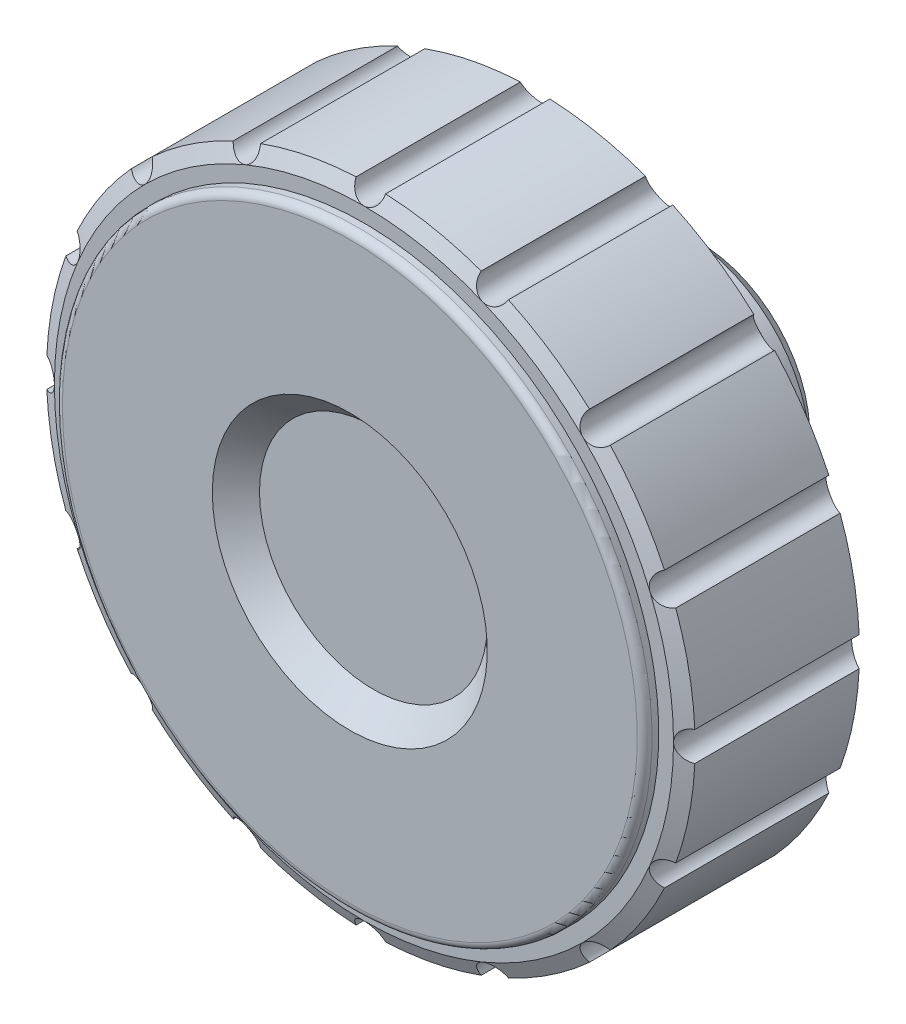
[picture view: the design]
ISO-10303-21;
HEADER;
FILE_DESCRIPTION(('STEP AP214'),'2;1');
FILE_NAME('part.step','',(''),(''),'','','');
FILE_SCHEMA(('AUTOMOTIVE_DESIGN { 1 0 10303 214 1 1 1 1 }'));
ENDSEC;
DATA;
#1=APPLICATION_CONTEXT('core data for automotive mechanical design processes');
#2=APPLICATION_PROTOCOL_DEFINITION('international standard','automotive_design',2000,#1);
#3=PRODUCT_CONTEXT('',#1,'mechanical');
#4=PRODUCT('Part','Part','',(#3));
#5=PRODUCT_RELATED_PRODUCT_CATEGORY('part','',(#4));
#6=PRODUCT_DEFINITION_FORMATION('','',#4);
#7=PRODUCT_DEFINITION_CONTEXT('part definition',#1,'design');
#8=PRODUCT_DEFINITION('design','',#6,#7);
#9=PRODUCT_DEFINITION_SHAPE('','',#8);
#10=(LENGTH_UNIT() NAMED_UNIT(*) SI_UNIT(.MILLI.,.METRE.));
#11=(NAMED_UNIT(*) PLANE_ANGLE_UNIT() SI_UNIT($,.RADIAN.));
#12=(NAMED_UNIT(*) SI_UNIT($,.STERADIAN.) SOLID_ANGLE_UNIT());
#13=UNCERTAINTY_MEASURE_WITH_UNIT(LENGTH_MEASURE(1.E-05),#10,'distance_accuracy_value','');
#14=(GEOMETRIC_REPRESENTATION_CONTEXT(3) GLOBAL_UNCERTAINTY_ASSIGNED_CONTEXT((#13)) GLOBAL_UNIT_ASSIGNED_CONTEXT((#10,
#11,#12)) REPRESENTATION_CONTEXT('',''));
#15=CARTESIAN_POINT('',(0.,0.,0.));
#16=DIRECTION('',(0.,0.,1.));
#17=DIRECTION('',(1.,0.,0.));
#18=AXIS2_PLACEMENT_3D('',#15,#16,#17);
#19=CARTESIAN_POINT('',(0.,4.,0.3));
#20=DIRECTION('',(0.,0.,-1.));
#21=DIRECTION('',(-1.,0.,0.));
#22=AXIS2_PLACEMENT_3D('',#19,#20,#21);
#23=PLANE('',#22);
#24=CARTESIAN_POINT('',(0.,0.,0.3));
#25=DIRECTION('',(0.,0.,-1.));
#26=DIRECTION('',(-1.,0.,0.));
#27=AXIS2_PLACEMENT_3D('',#24,#25,#26);
#28=CIRCLE('',#27,7.5);
#29=CARTESIAN_POINT('',(-7.5,0.,0.3));
#30=VERTEX_POINT('',#29);
#31=EDGE_CURVE('E690',#30,#30,#28,.T.);
#32=ORIENTED_EDGE('',*,*,#31,.T.);
#33=EDGE_LOOP('',(#32));
#34=FACE_BOUND('',#33,.T.);
#35=CARTESIAN_POINT('',(0.,0.,0.3));
#36=DIRECTION('',(0.,0.,-1.));
#37=DIRECTION('',(-1.,0.,0.));
#38=AXIS2_PLACEMENT_3D('',#35,#36,#37);
#39=CIRCLE('',#38,5.5);
#40=CARTESIAN_POINT('',(-5.5,0.,0.3));
#41=VERTEX_POINT('',#40);
#42=EDGE_CURVE('E2560',#41,#41,#39,.T.);
#43=ORIENTED_EDGE('',*,*,#42,.F.);
#44=EDGE_LOOP('',(#43));
#45=FACE_BOUND('',#44,.T.);
#46=ADVANCED_FACE('F14',(#34,#45),#23,.T.);
#47=CARTESIAN_POINT('',(0.,0.,10.96));
#48=DIRECTION('',(0.,0.,1.));
#49=DIRECTION('',(1.,0.,0.));
#50=AXIS2_PLACEMENT_3D('',#47,#48,#49);
#51=CONICAL_SURFACE('',#50,21.,1.13446401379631);
#52=CARTESIAN_POINT('',(0.,0.,11.4263076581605));
#53=DIRECTION('',(0.,0.,1.));
#54=DIRECTION('',(1.,0.,0.));
#55=AXIS2_PLACEMENT_3D('',#52,#53,#54);
#56=CIRCLE('',#55,22.0000000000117);
#57=CARTESIAN_POINT('',(14.833354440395,16.247202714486,11.4263076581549));
#58=VERTEX_POINT('',#57);
#59=CARTESIAN_POINT('',(9.3339790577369,19.921767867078,11.4263076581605));
#60=VERTEX_POINT('',#59);
#61=EDGE_CURVE('E805',#58,#60,#56,.T.);
#62=ORIENTED_EDGE('',*,*,#61,.F.);
#63=CARTESIAN_POINT('',(16.247402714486,14.8335456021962,11.4264366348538));
#64=CARTESIAN_POINT('',(16.2033896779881,14.7914358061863,11.398044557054));
#65=CARTESIAN_POINT('',(16.1555050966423,14.7533846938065,11.3695868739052));
#66=CARTESIAN_POINT('',(16.0532128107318,14.6863698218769,11.3132933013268));
#67=CARTESIAN_POINT('',(15.9987883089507,14.657430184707,11.2854592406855));
#68=CARTESIAN_POINT('',(15.8848006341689,14.6098067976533,11.2312852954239));
#69=CARTESIAN_POINT('',(15.8252302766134,14.5911376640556,11.2049475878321));
#70=CARTESIAN_POINT('',(15.7026960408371,14.5651390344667,11.1547661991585));
#71=CARTESIAN_POINT('',(15.639735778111,14.5577976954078,11.1309199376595));
#72=CARTESIAN_POINT('',(15.5157836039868,14.5553561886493,11.0879134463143));
#73=CARTESIAN_POINT('',(15.4548693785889,14.5596154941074,11.068569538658));
#74=CARTESIAN_POINT('',(15.333731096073,14.5795174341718,11.0339223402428));
#75=CARTESIAN_POINT('',(15.2735066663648,14.5951535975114,11.0186167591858));
#76=CARTESIAN_POINT('',(15.1621664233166,14.6356102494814,10.9942454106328));
#77=CARTESIAN_POINT('',(15.1107514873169,14.6593183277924,10.9846991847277));
#78=CARTESIAN_POINT('',(15.0122230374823,14.7154368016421,10.9700755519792));
#79=CARTESIAN_POINT('',(14.965106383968,14.7478407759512,10.9649948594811));
#80=CARTESIAN_POINT('',(14.8808692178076,14.8171371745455,10.9598350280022));
#81=CARTESIAN_POINT('',(14.8432324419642,14.8533746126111,10.9593514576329));
#82=CARTESIAN_POINT('',(14.7741351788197,14.9311724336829,10.9623566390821));
#83=CARTESIAN_POINT('',(14.7426735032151,14.9727317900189,10.965844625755));
#84=CARTESIAN_POINT('',(14.6875017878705,15.0587090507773,10.976473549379));
#85=CARTESIAN_POINT('',(14.6636089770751,15.1030224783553,10.9835155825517));
#86=CARTESIAN_POINT('',(14.6229025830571,15.1941749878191,11.0008840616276));
#87=CARTESIAN_POINT('',(14.6060900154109,15.2410144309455,11.0112109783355));
#88=CARTESIAN_POINT('',(14.5791223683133,15.3380152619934,11.0352479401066));
#89=CARTESIAN_POINT('',(14.5692840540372,15.3882329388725,11.049084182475));
#90=CARTESIAN_POINT('',(14.5573491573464,15.4887851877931,11.0793729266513));
#91=CARTESIAN_POINT('',(14.5552544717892,15.5391197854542,11.0958260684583));
#92=CARTESIAN_POINT('',(14.5586504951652,15.6431771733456,11.1323714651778));
#93=CARTESIAN_POINT('',(14.5648229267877,15.6968097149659,11.1526563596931));
#94=CARTESIAN_POINT('',(14.5854442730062,15.8017175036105,11.1950912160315));
#95=CARTESIAN_POINT('',(14.5999002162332,15.8529907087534,11.2172427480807));
#96=CARTESIAN_POINT('',(14.6382676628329,15.9569609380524,11.2650435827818));
#97=CARTESIAN_POINT('',(14.6629647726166,16.0093079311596,11.2908232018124));
#98=CARTESIAN_POINT('',(14.7207120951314,16.1086190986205,11.34316742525));
#99=CARTESIAN_POINT('',(14.7537491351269,16.1555915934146,11.3697307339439));
#100=CARTESIAN_POINT('',(14.8043214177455,16.2158335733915,11.4063769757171));
#101=CARTESIAN_POINT('',(14.8186842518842,16.2318614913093,11.4164124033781));
#102=CARTESIAN_POINT('',(14.8335456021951,16.247402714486,11.4264366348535));
#103=B_SPLINE_CURVE_WITH_KNOTS('',3,(#63,#64,#65,#66,#67,#68,#69,#70,#71,#72,#73,#74,#75,#76,
#77,#78,#79,#80,#81,#82,#83,#84,#85,#86,#87,#88,#89,#90,#91,#92,#93,#94,#95,#96,#97,#98,#99,
#100,#101,#102),.UNSPECIFIED.,.F.,.F.,(4,2,2,2,2,2,2,2,2,2,2,2,2,2,2,2,2,2,2,4),(0.,
0.201422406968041,0.403373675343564,0.605611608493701,0.807637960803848,0.998738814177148,
1.18973105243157,1.36104276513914,1.53222832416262,1.68819769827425,1.84413702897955,
1.99595814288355,2.14780102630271,2.30616203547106,2.46456183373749,2.63686071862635,
2.80930601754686,2.99859361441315,3.18758408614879,3.25877905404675),.UNSPECIFIED.);
#104=CARTESIAN_POINT('',(14.8492424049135,14.8492424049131,10.9599999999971));
#105=VERTEX_POINT('',#104);
#106=EDGE_CURVE('E562',#105,#58,#103,.T.);
#107=ORIENTED_EDGE('',*,*,#106,.F.);
#108=CARTESIAN_POINT('',(0.,0.,10.96));
#109=DIRECTION('',(0.,0.,-1.));
#110=DIRECTION('',(-1.,0.,0.));
#111=AXIS2_PLACEMENT_3D('',#108,#109,#110);
#112=CIRCLE('',#111,21.);
#113=CARTESIAN_POINT('',(8.03635207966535,19.4014701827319,10.9599999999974));
#114=VERTEX_POINT('',#113);
#115=EDGE_CURVE('E745',#114,#105,#112,.T.);
#116=ORIENTED_EDGE('',*,*,#115,.F.);
#117=CARTESIAN_POINT('',(9.3341790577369,19.9222215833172,11.4265388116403));
#118=CARTESIAN_POINT('',(9.30964258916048,19.8664672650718,11.3981461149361));
#119=CARTESIAN_POINT('',(9.27997543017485,19.8129803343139,11.3696873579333));
#120=CARTESIAN_POINT('',(9.21113560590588,19.7119044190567,11.313390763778));
#121=CARTESIAN_POINT('',(9.17193820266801,19.6643312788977,11.28555475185));
#122=CARTESIAN_POINT('',(9.08486965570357,19.5766923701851,11.231375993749));
#123=CARTESIAN_POINT('',(9.0369862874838,19.5366373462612,11.2050354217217));
#124=CARTESIAN_POINT('',(8.9337430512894,19.4657037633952,11.1548473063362));
#125=CARTESIAN_POINT('',(8.87839105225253,19.4348156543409,11.1309971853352));
#126=CARTESIAN_POINT('',(8.76481700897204,19.3851008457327,11.0879815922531));
#127=CARTESIAN_POINT('',(8.70691181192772,19.3657124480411,11.068632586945));
#128=CARTESIAN_POINT('',(8.58738031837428,19.3377165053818,11.0339746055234));
#129=CARTESIAN_POINT('',(8.52575615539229,19.3291028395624,11.0186633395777));
#130=CARTESIAN_POINT('',(8.4074052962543,19.3238482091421,10.9942807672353));
#131=CARTESIAN_POINT('',(8.35082820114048,19.3260650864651,10.984729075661));
#132=CARTESIAN_POINT('',(8.2383156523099,19.3401859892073,10.9700946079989));
#133=CARTESIAN_POINT('',(8.1823797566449,19.3520828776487,10.9650085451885));
#134=CARTESIAN_POINT('',(8.07802564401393,19.3838508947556,10.9598389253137));
#135=CARTESIAN_POINT('',(8.02938120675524,19.4029189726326,10.9593507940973));
#136=CARTESIAN_POINT('',(7.93576018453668,19.4483378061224,10.9623472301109));
#137=CARTESIAN_POINT('',(7.89078289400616,19.4746871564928,10.9658310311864));
#138=CARTESIAN_POINT('',(7.80689701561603,19.5329937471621,10.9764520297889));
#139=CARTESIAN_POINT('',(7.76785937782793,19.56478422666,10.9834901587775));
#140=CARTESIAN_POINT('',(7.69535702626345,19.6334088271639,11.0008512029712));
#141=CARTESIAN_POINT('',(7.66189311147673,19.6702436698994,11.0111745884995));
#142=CARTESIAN_POINT('',(7.59984488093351,19.749529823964,11.0352044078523));
#143=CARTESIAN_POINT('',(7.57153143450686,19.7921542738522,11.0490369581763));
#144=CARTESIAN_POINT('',(7.52201140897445,19.8804748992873,11.0793187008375));
#145=CARTESIAN_POINT('',(7.50080657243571,19.9261718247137,11.0957685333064));
#146=CARTESIAN_POINT('',(7.46410726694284,20.0235987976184,11.1323071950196));
#147=CARTESIAN_POINT('',(7.449276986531,20.075506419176,11.1525886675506));
#148=CARTESIAN_POINT('',(7.42816422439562,20.1803123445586,11.1950171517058));
#149=CARTESIAN_POINT('',(7.42188901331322,20.23321145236,11.2171657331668));
#150=CARTESIAN_POINT('',(7.41752793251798,20.343944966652,11.2649610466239));
#151=CARTESIAN_POINT('',(7.42030180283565,20.4017567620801,11.2907381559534));
#152=CARTESIAN_POINT('',(7.43562621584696,20.5156056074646,11.3430780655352));
#153=CARTESIAN_POINT('',(7.44816142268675,20.5716452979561,11.3696395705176));
#154=CARTESIAN_POINT('',(7.47182855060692,20.6467005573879,11.4063055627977));
#155=CARTESIAN_POINT('',(7.47897691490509,20.6670487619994,11.4163622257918));
#156=CARTESIAN_POINT('',(7.48677485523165,20.687137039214,11.4264076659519));
#157=B_SPLINE_CURVE_WITH_KNOTS('',3,(#117,#118,#119,#120,#121,#122,#123,#124,#125,#126,#127,
#128,#129,#130,#131,#132,#133,#134,#135,#136,#137,#138,#139,#140,#141,#142,#143,#144,#145,#146,
#147,#148,#149,#150,#151,#152,#153,#154,#155,#156),.UNSPECIFIED.,.F.,.F.,(4,2,2,2,2,2,2,2,2,2,2,
2,2,2,2,2,2,2,2,4),(0.,0.20142757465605,0.403383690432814,0.605626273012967,0.807657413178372,
0.99876840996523,1.18977079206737,1.36109333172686,1.53228967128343,1.68826466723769,
1.84420958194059,1.99602979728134,2.14787175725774,2.30622670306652,2.46462043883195,
2.6369102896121,2.80934647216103,2.99862495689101,3.1876066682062,3.25895217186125),.UNSPECIFIED.);
#158=EDGE_CURVE('E980',#60,#114,#157,.T.);
#159=ORIENTED_EDGE('',*,*,#158,.F.);
#160=EDGE_LOOP('',(#62,#107,#116,#159));
#161=FACE_BOUND('',#160,.T.);
#162=ADVANCED_FACE('F413',(#161),#51,.T.);
#163=CARTESIAN_POINT('',(7.4866972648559,20.686937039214,11.426307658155));
#164=VERTEX_POINT('',#163);
#165=EDGE_CURVE('E571',#114,#164,#157,.T.);
#166=ORIENTED_EDGE('',*,*,#165,.F.);
#167=CARTESIAN_POINT('',(6.40111010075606E-13,20.9999999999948,10.9599999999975));
#168=VERTEX_POINT('',#167);
#169=EDGE_CURVE('E744',#168,#114,#112,.T.);
#170=ORIENTED_EDGE('',*,*,#169,.F.);
#171=CARTESIAN_POINT('',(0.999746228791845,21.977472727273,11.4264009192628));
#172=CARTESIAN_POINT('',(0.998395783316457,21.9165753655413,11.3980090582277));
#173=CARTESIAN_POINT('',(0.991437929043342,21.8558106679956,11.3695517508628));
#174=CARTESIAN_POINT('',(0.966484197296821,21.7360950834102,11.3132592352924));
#175=CARTESIAN_POINT('',(0.948459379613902,21.6771493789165,11.2854258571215));
#176=CARTESIAN_POINT('',(0.90152444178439,21.5628770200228,11.231253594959));
#177=CARTESIAN_POINT('',(0.872598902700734,21.5075556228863,11.204916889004));
#178=CARTESIAN_POINT('',(0.804330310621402,21.4025322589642,11.1547378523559));
#179=CARTESIAN_POINT('',(0.764998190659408,21.3528244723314,11.1308929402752));
#180=CARTESIAN_POINT('',(0.679071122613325,21.2634574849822,11.0878896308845));
#181=CARTESIAN_POINT('',(0.632984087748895,21.2234001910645,11.0685475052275));
#182=CARTESIAN_POINT('',(0.533249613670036,21.1518232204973,11.0339040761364));
#183=CARTESIAN_POINT('',(0.479606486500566,21.1202987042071,11.0186004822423));
#184=CARTESIAN_POINT('',(0.372267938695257,21.0701845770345,10.9942330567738));
#185=CARTESIAN_POINT('',(0.319147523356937,21.0505968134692,10.9846887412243));
#186=CARTESIAN_POINT('',(0.209795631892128,21.0206162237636,10.9700688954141));
#187=CARTESIAN_POINT('',(0.153566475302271,21.0102166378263,10.9649900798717));
#188=CARTESIAN_POINT('',(0.0450029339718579,20.9996589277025,10.9598336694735));
#189=CARTESIAN_POINT('',(-0.00723343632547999,20.9986727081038,10.9593516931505));
#190=CARTESIAN_POINT('',(-0.111102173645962,21.0048311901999,10.9623599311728));
#191=CARTESIAN_POINT('',(-0.162734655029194,21.0119743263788,10.9658493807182));
#192=CARTESIAN_POINT('',(-0.262539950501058,21.0337628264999,10.9764810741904));
#193=CARTESIAN_POINT('',(-0.310768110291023,21.0482051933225,10.9835244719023));
#194=CARTESIAN_POINT('',(-0.404004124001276,21.083881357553,11.0008955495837));
#195=CARTESIAN_POINT('',(-0.4490115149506,21.1051161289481,11.0112237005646));
#196=CARTESIAN_POINT('',(-0.536667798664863,21.1546422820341,11.0352631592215));
#197=CARTESIAN_POINT('',(-0.579132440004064,21.1831975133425,11.0491006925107));
#198=CARTESIAN_POINT('',(-0.658669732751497,21.2458646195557,11.0793918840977));
#199=CARTESIAN_POINT('',(-0.695741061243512,21.2799778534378,11.0958461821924));
#200=CARTESIAN_POINT('',(-0.766915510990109,21.3559639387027,11.1323939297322));
#201=CARTESIAN_POINT('',(-0.800472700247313,21.3982550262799,11.1526800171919));
#202=CARTESIAN_POINT('',(-0.860067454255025,21.4870224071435,11.1951171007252));
#203=CARTESIAN_POINT('',(-0.886098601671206,21.533502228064,11.2172696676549));
#204=CARTESIAN_POINT('',(-0.93248090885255,21.6341545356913,11.2650724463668));
#205=CARTESIAN_POINT('',(-0.952029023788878,21.6886349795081,11.2908529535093));
#206=CARTESIAN_POINT('',(-0.981412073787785,21.7996956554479,11.3431986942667));
#207=CARTESIAN_POINT('',(-0.991262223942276,21.8562724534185,11.3697626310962));
#208=CARTESIAN_POINT('',(-0.998090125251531,21.9345827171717,11.4063866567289));
#209=CARTESIAN_POINT('',(-0.999264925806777,21.9560235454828,11.4163993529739));
#210=CARTESIAN_POINT('',(-0.999746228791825,21.977472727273,11.4264009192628));
#211=B_SPLINE_CURVE_WITH_KNOTS('',3,(#171,#172,#173,#174,#175,#176,#177,#178,#179,#180,#181,
#182,#183,#184,#185,#186,#187,#188,#189,#190,#191,#192,#193,#194,#195,#196,#197,#198,#199,#200,
#201,#202,#203,#204,#205,#206,#207,#208,#209,#210),.UNSPECIFIED.,.F.,.F.,(4,2,2,2,2,2,2,2,2,2,2,
2,2,2,2,2,2,2,2,4),(0.,0.201420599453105,0.403370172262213,0.60560647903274,0.807631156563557,
0.998728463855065,1.18971715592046,1.36102508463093,1.53220687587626,1.68817428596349,
1.84411166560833,1.99593309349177,2.14777630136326,2.30613943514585,2.46454134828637,
2.63684336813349,2.80929187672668,2.99858276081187,3.18757619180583,3.25861009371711),.UNSPECIFIED.);
#212=CARTESIAN_POINT('',(0.999741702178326,21.977272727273,11.4263076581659));
#213=VERTEX_POINT('',#212);
#214=EDGE_CURVE('E972',#213,#168,#211,.T.);
#215=ORIENTED_EDGE('',*,*,#214,.F.);
#216=CARTESIAN_POINT('',(0.,0.,11.4263076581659));
#217=DIRECTION('',(0.,0.,1.));
#218=DIRECTION('',(1.,0.,0.));
#219=AXIS2_PLACEMENT_3D('',#216,#217,#218);
#220=CIRCLE('',#219,22.0000000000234);
#221=EDGE_CURVE('E803',#164,#213,#220,.T.);
#222=ORIENTED_EDGE('',*,*,#221,.F.);
#223=EDGE_LOOP('',(#166,#170,#215,#222));
#224=FACE_BOUND('',#223,.T.);
#225=ADVANCED_FACE('F419',(#224),#51,.T.);
#226=CARTESIAN_POINT('',(16.247202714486,14.833354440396,11.4263076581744));
#227=VERTEX_POINT('',#226);
#228=EDGE_CURVE('E1006',#227,#105,#103,.T.);
#229=ORIENTED_EDGE('',*,*,#228,.F.);
#230=CARTESIAN_POINT('',(0.,0.,11.4263076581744));
#231=DIRECTION('',(0.,0.,1.));
#232=DIRECTION('',(1.,0.,0.));
#233=AXIS2_PLACEMENT_3D('',#230,#231,#232);
#234=CIRCLE('',#233,22.0000000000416);
#235=CARTESIAN_POINT('',(19.921767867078,9.3339790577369,11.4263076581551));
#236=VERTEX_POINT('',#235);
#237=EDGE_CURVE('E807',#236,#227,#234,.T.);
#238=ORIENTED_EDGE('',*,*,#237,.F.);
#239=CARTESIAN_POINT('',(20.687137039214,7.48677485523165,11.4264076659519));
#240=CARTESIAN_POINT('',(20.6303586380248,7.46471723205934,11.3980157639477));
#241=CARTESIAN_POINT('',(20.5715568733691,7.44789094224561,11.3695583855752));
#242=CARTESIAN_POINT('',(20.4514048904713,7.42513027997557,11.3132656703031));
#243=CARTESIAN_POINT('',(20.3900483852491,7.4192246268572,11.2854321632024));
#244=CARTESIAN_POINT('',(20.2665131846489,7.41885498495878,11.2312595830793));
#245=CARTESIAN_POINT('',(20.2043334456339,7.42440725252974,11.2049226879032));
#246=CARTESIAN_POINT('',(20.0811788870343,7.44728679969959,11.1547432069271));
#247=CARTESIAN_POINT('',(20.0202028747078,7.46460175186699,11.1308980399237));
#248=CARTESIAN_POINT('',(19.9047549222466,7.50978719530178,11.0878941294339));
#249=CARTESIAN_POINT('',(19.8501095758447,7.53703611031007,11.0685516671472));
#250=CARTESIAN_POINT('',(19.7458132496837,7.60178616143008,11.0339075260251));
#251=CARTESIAN_POINT('',(19.696159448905,7.63928146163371,11.0186035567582));
#252=CARTESIAN_POINT('',(19.608782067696,7.71927057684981,10.9942353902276));
#253=CARTESIAN_POINT('',(19.5703563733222,7.76085116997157,10.9846907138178));
#254=CARTESIAN_POINT('',(19.500809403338,7.85040550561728,10.9700701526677));
#255=CARTESIAN_POINT('',(19.4696827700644,7.89837451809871,10.9649909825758));
#256=CARTESIAN_POINT('',(19.4183819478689,7.99463357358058,10.9598339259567));
#257=CARTESIAN_POINT('',(19.3974801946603,8.04251614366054,10.9593516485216));
#258=CARTESIAN_POINT('',(19.3634198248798,8.14083495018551,10.9623593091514));
#259=CARTESIAN_POINT('',(19.3502597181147,8.19127069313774,10.9658484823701));
#260=CARTESIAN_POINT('',(19.3321946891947,8.29181681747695,10.9764796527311));
#261=CARTESIAN_POINT('',(19.3270810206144,8.3419006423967,10.9835227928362));
#262=CARTESIAN_POINT('',(19.3243605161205,8.44169217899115,11.0008933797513));
#263=CARTESIAN_POINT('',(19.326754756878,8.49139983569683,11.0112212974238));
#264=CARTESIAN_POINT('',(19.338965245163,8.59133660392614,11.0352602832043));
#265=CARTESIAN_POINT('',(19.3490957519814,8.64149646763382,11.0490975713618));
#266=CARTESIAN_POINT('',(19.3765538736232,8.73896118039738,11.0793883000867));
#267=CARTESIAN_POINT('',(19.3938832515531,8.78626532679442,11.0958423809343));
#268=CARTESIAN_POINT('',(19.4368468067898,8.88110089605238,11.1323896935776));
#269=CARTESIAN_POINT('',(19.4630763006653,8.92828800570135,11.1526755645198));
#270=CARTESIAN_POINT('',(19.5222795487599,9.01731665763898,11.1951122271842));
#271=CARTESIAN_POINT('',(19.5552590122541,9.0591536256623,11.2172645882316));
#272=CARTESIAN_POINT('',(19.6304986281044,9.14052389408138,11.2650669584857));
#273=CARTESIAN_POINT('',(19.673350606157,9.17943314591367,11.2908472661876));
#274=CARTESIAN_POINT('',(19.7647116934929,9.24908159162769,11.3431926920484));
#275=CARTESIAN_POINT('',(19.8132118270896,9.27983350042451,11.3697565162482));
#276=CARTESIAN_POINT('',(19.8830391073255,9.31615818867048,11.4064285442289));
#277=CARTESIAN_POINT('',(19.9024925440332,9.32549047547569,11.4164893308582));
#278=CARTESIAN_POINT('',(19.9222215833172,9.3341790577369,11.4265388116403));
#279=B_SPLINE_CURVE_WITH_KNOTS('',3,(#239,#240,#241,#242,#243,#244,#245,#246,#247,#248,#249,
#250,#251,#252,#253,#254,#255,#256,#257,#258,#259,#260,#261,#262,#263,#264,#265,#266,#267,#268,
#269,#270,#271,#272,#273,#274,#275,#276,#277,#278),.UNSPECIFIED.,.F.,.F.,(4,2,2,2,2,2,2,2,2,2,2,
2,2,2,2,2,2,2,2,4),(0.,0.201420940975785,0.403370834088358,0.605607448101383,0.807632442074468,
0.998730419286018,1.18971978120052,1.36102842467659,1.53221092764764,1.68817870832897,
1.84411645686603,1.9959378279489,2.14778097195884,2.30614369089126,2.46454521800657,
2.63684671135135,2.80929454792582,2.99858451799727,3.18757768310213,3.25895226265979),.UNSPECIFIED.);
#280=CARTESIAN_POINT('',(19.4014701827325,8.03635207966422,10.9599999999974));
#281=VERTEX_POINT('',#280);
#282=EDGE_CURVE('E553',#281,#236,#279,.T.);
#283=ORIENTED_EDGE('',*,*,#282,.F.);
#284=EDGE_CURVE('E747',#105,#281,#112,.T.);
#285=ORIENTED_EDGE('',*,*,#284,.F.);
#286=EDGE_LOOP('',(#229,#238,#283,#285));
#287=FACE_BOUND('',#286,.T.);
#288=ADVANCED_FACE('F2171',(#287),#51,.T.);
#289=CARTESIAN_POINT('',(20.686937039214,7.4866972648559,11.4263076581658));
#290=VERTEX_POINT('',#289);
#291=EDGE_CURVE('E1017',#290,#281,#279,.T.);
#292=ORIENTED_EDGE('',*,*,#291,.F.);
#293=CARTESIAN_POINT('',(0.,0.,11.4263076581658));
#294=DIRECTION('',(0.,0.,1.));
#295=DIRECTION('',(1.,0.,0.));
#296=AXIS2_PLACEMENT_3D('',#293,#294,#295);
#297=CIRCLE('',#296,22.0000000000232);
#298=CARTESIAN_POINT('',(21.977272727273,0.99974170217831,11.4263076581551));
#299=VERTEX_POINT('',#298);
#300=EDGE_CURVE('E809',#299,#290,#297,.T.);
#301=ORIENTED_EDGE('',*,*,#300,.F.);
#302=CARTESIAN_POINT('',(21.977472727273,-0.999746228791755,11.4264009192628));
#303=CARTESIAN_POINT('',(21.9165753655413,-0.998395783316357,11.3980090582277));
#304=CARTESIAN_POINT('',(21.8558106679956,-0.991437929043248,11.3695517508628));
#305=CARTESIAN_POINT('',(21.7360950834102,-0.966484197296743,11.3132592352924));
#306=CARTESIAN_POINT('',(21.6771493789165,-0.948459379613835,11.2854258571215));
#307=CARTESIAN_POINT('',(21.5628770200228,-0.901524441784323,11.231253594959));
#308=CARTESIAN_POINT('',(21.5075556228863,-0.872598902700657,11.204916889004));
#309=CARTESIAN_POINT('',(21.4025322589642,-0.804330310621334,11.1547378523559));
#310=CARTESIAN_POINT('',(21.3528244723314,-0.764998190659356,11.1308929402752));
#311=CARTESIAN_POINT('',(21.2634574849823,-0.67907112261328,11.0878896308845));
#312=CARTESIAN_POINT('',(21.2234001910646,-0.632984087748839,11.0685475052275));
#313=CARTESIAN_POINT('',(21.1518232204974,-0.533249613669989,11.0339040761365));
#314=CARTESIAN_POINT('',(21.1202987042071,-0.47960648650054,11.0186004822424));
#315=CARTESIAN_POINT('',(21.0701845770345,-0.372267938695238,10.9942330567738));
#316=CARTESIAN_POINT('',(21.0505968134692,-0.319147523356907,10.9846887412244));
#317=CARTESIAN_POINT('',(21.0206162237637,-0.2097956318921,10.9700688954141));
#318=CARTESIAN_POINT('',(21.0102166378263,-0.153566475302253,10.9649900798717));
#319=CARTESIAN_POINT('',(20.9996589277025,-0.0450029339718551,10.9598336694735));
#320=CARTESIAN_POINT('',(20.9986727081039,0.00723343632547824,10.9593516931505));
#321=CARTESIAN_POINT('',(21.0048311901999,0.111102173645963,10.9623599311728));
#322=CARTESIAN_POINT('',(21.0119743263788,0.162734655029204,10.9658493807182));
#323=CARTESIAN_POINT('',(21.0337628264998,0.262539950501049,10.9764810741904));
#324=CARTESIAN_POINT('',(21.0482051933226,0.310768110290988,10.9835244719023));
#325=CARTESIAN_POINT('',(21.083881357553,0.404004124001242,11.0008955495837));
#326=CARTESIAN_POINT('',(21.105116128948,0.449011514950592,11.0112237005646));
#327=CARTESIAN_POINT('',(21.1546422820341,0.536667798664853,11.0352631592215));
#328=CARTESIAN_POINT('',(21.1831975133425,0.579132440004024,11.0491006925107));
#329=CARTESIAN_POINT('',(21.2458646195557,0.658669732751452,11.0793918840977));
#330=CARTESIAN_POINT('',(21.2799778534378,0.695741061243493,11.0958461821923));
#331=CARTESIAN_POINT('',(21.3559639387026,0.766915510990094,11.1323939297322));
#332=CARTESIAN_POINT('',(21.3982550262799,0.800472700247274,11.1526800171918));
#333=CARTESIAN_POINT('',(21.4870224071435,0.860067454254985,11.1951171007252));
#334=CARTESIAN_POINT('',(21.5335022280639,0.886098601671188,11.2172696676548));
#335=CARTESIAN_POINT('',(21.6341545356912,0.932480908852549,11.2650724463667));
#336=CARTESIAN_POINT('',(21.688634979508,0.952029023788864,11.2908529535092));
#337=CARTESIAN_POINT('',(21.7996956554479,0.981412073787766,11.3431986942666));
#338=CARTESIAN_POINT('',(21.8562724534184,0.991262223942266,11.3697626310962));
#339=CARTESIAN_POINT('',(21.9345827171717,0.998090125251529,11.4063866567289));
#340=CARTESIAN_POINT('',(21.9560235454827,0.999264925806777,11.4163993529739));
#341=CARTESIAN_POINT('',(21.977472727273,0.999746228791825,11.4264009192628));
#342=B_SPLINE_CURVE_WITH_KNOTS('',3,(#302,#303,#304,#305,#306,#307,#308,#309,#310,#311,#312,
#313,#314,#315,#316,#317,#318,#319,#320,#321,#322,#323,#324,#325,#326,#327,#328,#329,#330,#331,
#332,#333,#334,#335,#336,#337,#338,#339,#340,#341),.UNSPECIFIED.,.F.,.F.,(4,2,2,2,2,2,2,2,2,2,2,
2,2,2,2,2,2,2,2,4),(0.,0.201420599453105,0.403370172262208,0.605606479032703,0.807631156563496,
0.998728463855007,1.1897171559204,1.36102508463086,1.53220687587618,1.6881742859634,
1.84411166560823,1.99593309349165,2.14777630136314,2.30613943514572,2.46454134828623,
2.63684336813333,2.8092918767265,2.99858276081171,3.18757619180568,3.25861009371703),.UNSPECIFIED.);
#343=CARTESIAN_POINT('',(20.9999999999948,-5.97058321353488E-13,10.9599999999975));
#344=VERTEX_POINT('',#343);
#345=EDGE_CURVE('E544',#344,#299,#342,.T.);
#346=ORIENTED_EDGE('',*,*,#345,.F.);
#347=EDGE_CURVE('E750',#281,#344,#112,.T.);
#348=ORIENTED_EDGE('',*,*,#347,.F.);
#349=EDGE_LOOP('',(#292,#301,#346,#348));
#350=FACE_BOUND('',#349,.T.);
#351=ADVANCED_FACE('F2182',(#350),#51,.T.);
#352=CARTESIAN_POINT('',(-0.99974170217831,21.977272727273,11.4263076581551));
#353=VERTEX_POINT('',#352);
#354=EDGE_CURVE('E580',#168,#353,#211,.T.);
#355=ORIENTED_EDGE('',*,*,#354,.F.);
#356=CARTESIAN_POINT('',(-8.03635207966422,19.4014701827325,10.9599999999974));
#357=VERTEX_POINT('',#356);
#358=EDGE_CURVE('E653',#357,#168,#112,.T.);
#359=ORIENTED_EDGE('',*,*,#358,.F.);
#360=CARTESIAN_POINT('',(-7.48677485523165,20.687137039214,11.4264076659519));
#361=CARTESIAN_POINT('',(-7.46471723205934,20.6303586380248,11.3980157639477));
#362=CARTESIAN_POINT('',(-7.4478909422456,20.5715568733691,11.3695583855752));
#363=CARTESIAN_POINT('',(-7.42513027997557,20.4514048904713,11.3132656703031));
#364=CARTESIAN_POINT('',(-7.4192246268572,20.3900483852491,11.2854321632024));
#365=CARTESIAN_POINT('',(-7.41885498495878,20.2665131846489,11.2312595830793));
#366=CARTESIAN_POINT('',(-7.42440725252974,20.2043334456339,11.2049226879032));
#367=CARTESIAN_POINT('',(-7.44728679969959,20.0811788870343,11.1547432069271));
#368=CARTESIAN_POINT('',(-7.46460175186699,20.0202028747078,11.1308980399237));
#369=CARTESIAN_POINT('',(-7.50978719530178,19.9047549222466,11.0878941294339));
#370=CARTESIAN_POINT('',(-7.53703611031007,19.8501095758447,11.0685516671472));
#371=CARTESIAN_POINT('',(-7.60178616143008,19.7458132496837,11.0339075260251));
#372=CARTESIAN_POINT('',(-7.63928146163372,19.696159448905,11.0186035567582));
#373=CARTESIAN_POINT('',(-7.71927057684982,19.608782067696,10.9942353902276));
#374=CARTESIAN_POINT('',(-7.76085116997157,19.5703563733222,10.9846907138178));
#375=CARTESIAN_POINT('',(-7.85040550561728,19.500809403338,10.9700701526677));
#376=CARTESIAN_POINT('',(-7.89837451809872,19.4696827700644,10.9649909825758));
#377=CARTESIAN_POINT('',(-7.99463357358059,19.4183819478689,10.9598339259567));
#378=CARTESIAN_POINT('',(-8.04251614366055,19.3974801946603,10.9593516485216));
#379=CARTESIAN_POINT('',(-8.14083495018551,19.3634198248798,10.9623593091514));
#380=CARTESIAN_POINT('',(-8.19127069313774,19.3502597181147,10.9658484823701));
#381=CARTESIAN_POINT('',(-8.29181681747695,19.3321946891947,10.9764796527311));
#382=CARTESIAN_POINT('',(-8.3419006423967,19.3270810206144,10.9835227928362));
#383=CARTESIAN_POINT('',(-8.44169217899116,19.3243605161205,11.0008933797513));
#384=CARTESIAN_POINT('',(-8.49139983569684,19.326754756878,11.0112212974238));
#385=CARTESIAN_POINT('',(-8.59133660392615,19.338965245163,11.0352602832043));
#386=CARTESIAN_POINT('',(-8.64149646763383,19.3490957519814,11.0490975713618));
#387=CARTESIAN_POINT('',(-8.73896118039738,19.3765538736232,11.0793883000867));
#388=CARTESIAN_POINT('',(-8.78626532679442,19.3938832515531,11.0958423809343));
#389=CARTESIAN_POINT('',(-8.88110089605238,19.4368468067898,11.1323896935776));
#390=CARTESIAN_POINT('',(-8.92828800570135,19.4630763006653,11.1526755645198));
#391=CARTESIAN_POINT('',(-9.01731665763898,19.5222795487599,11.1951122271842));
#392=CARTESIAN_POINT('',(-9.0591536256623,19.5552590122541,11.2172645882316));
#393=CARTESIAN_POINT('',(-9.14052389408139,19.6304986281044,11.2650669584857));
#394=CARTESIAN_POINT('',(-9.17943314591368,19.673350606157,11.2908472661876));
#395=CARTESIAN_POINT('',(-9.2490815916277,19.7647116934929,11.3431926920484));
#396=CARTESIAN_POINT('',(-9.27983350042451,19.8132118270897,11.3697565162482));
#397=CARTESIAN_POINT('',(-9.31615818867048,19.8830391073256,11.4064285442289));
#398=CARTESIAN_POINT('',(-9.32549047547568,19.9024925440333,11.4164893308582));
#399=CARTESIAN_POINT('',(-9.3341790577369,19.9222215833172,11.4265388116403));
#400=B_SPLINE_CURVE_WITH_KNOTS('',3,(#360,#361,#362,#363,#364,#365,#366,#367,#368,#369,#370,
#371,#372,#373,#374,#375,#376,#377,#378,#379,#380,#381,#382,#383,#384,#385,#386,#387,#388,#389,
#390,#391,#392,#393,#394,#395,#396,#397,#398,#399),.UNSPECIFIED.,.F.,.F.,(4,2,2,2,2,2,2,2,2,2,2,
2,2,2,2,2,2,2,2,4),(0.,0.201420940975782,0.403370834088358,0.605607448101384,0.807632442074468,
0.998730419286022,1.18971978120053,1.3610284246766,1.53221092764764,1.68817870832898,
1.84411645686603,1.9959378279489,2.14778097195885,2.30614369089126,2.46454521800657,
2.63684671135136,2.80929454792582,2.99858451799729,3.18757768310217,3.25895226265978),.UNSPECIFIED.);
#401=CARTESIAN_POINT('',(-7.4866972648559,20.686937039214,11.4263076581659));
#402=VERTEX_POINT('',#401);
#403=EDGE_CURVE('E594',#402,#357,#400,.T.);
#404=ORIENTED_EDGE('',*,*,#403,.F.);
#405=CARTESIAN_POINT('',(0.,0.,11.4263076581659));
#406=DIRECTION('',(0.,0.,1.));
#407=DIRECTION('',(1.,0.,0.));
#408=AXIS2_PLACEMENT_3D('',#405,#406,#407);
#409=CIRCLE('',#408,22.0000000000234);
#410=EDGE_CURVE('E741',#353,#402,#409,.T.);
#411=ORIENTED_EDGE('',*,*,#410,.F.);
#412=EDGE_LOOP('',(#355,#359,#404,#411));
#413=FACE_BOUND('',#412,.T.);
#414=ADVANCED_FACE('F740',(#413),#51,.T.);
#415=CARTESIAN_POINT('',(21.977272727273,-0.999741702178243,11.4263076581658));
#416=VERTEX_POINT('',#415);
#417=EDGE_CURVE('E1043',#416,#344,#342,.T.);
#418=ORIENTED_EDGE('',*,*,#417,.F.);
#419=CARTESIAN_POINT('',(0.,0.,11.4263076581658));
#420=DIRECTION('',(0.,0.,1.));
#421=DIRECTION('',(1.,0.,0.));
#422=AXIS2_PLACEMENT_3D('',#419,#420,#421);
#423=CIRCLE('',#422,22.0000000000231);
#424=CARTESIAN_POINT('',(20.686937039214,-7.4866972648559,11.426307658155));
#425=VERTEX_POINT('',#424);
#426=EDGE_CURVE('E811',#425,#416,#423,.T.);
#427=ORIENTED_EDGE('',*,*,#426,.F.);
#428=CARTESIAN_POINT('',(19.9222215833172,-9.334179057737,11.4265388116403));
#429=CARTESIAN_POINT('',(19.8664672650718,-9.30964258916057,11.3981461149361));
#430=CARTESIAN_POINT('',(19.8129803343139,-9.27997543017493,11.3696873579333));
#431=CARTESIAN_POINT('',(19.7119044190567,-9.21113560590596,11.313390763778));
#432=CARTESIAN_POINT('',(19.6643312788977,-9.17193820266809,11.28555475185));
#433=CARTESIAN_POINT('',(19.5766923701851,-9.08486965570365,11.231375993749));
#434=CARTESIAN_POINT('',(19.5366373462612,-9.03698628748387,11.2050354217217));
#435=CARTESIAN_POINT('',(19.4657037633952,-8.93374305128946,11.1548473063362));
#436=CARTESIAN_POINT('',(19.4348156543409,-8.87839105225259,11.1309971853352));
#437=CARTESIAN_POINT('',(19.3851008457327,-8.7648170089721,11.0879815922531));
#438=CARTESIAN_POINT('',(19.3657124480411,-8.70691181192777,11.068632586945));
#439=CARTESIAN_POINT('',(19.3377165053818,-8.58738031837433,11.0339746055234));
#440=CARTESIAN_POINT('',(19.3291028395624,-8.52575615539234,11.0186633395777));
#441=CARTESIAN_POINT('',(19.323848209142,-8.40740529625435,10.9942807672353));
#442=CARTESIAN_POINT('',(19.3260650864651,-8.35082820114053,10.9847290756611));
#443=CARTESIAN_POINT('',(19.3401859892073,-8.23831565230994,10.9700946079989));
#444=CARTESIAN_POINT('',(19.3520828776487,-8.18237975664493,10.9650085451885));
#445=CARTESIAN_POINT('',(19.3838508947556,-8.07802564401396,10.9598389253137));
#446=CARTESIAN_POINT('',(19.4029189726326,-8.02938120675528,10.9593507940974));
#447=CARTESIAN_POINT('',(19.4483378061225,-7.93576018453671,10.9623472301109));
#448=CARTESIAN_POINT('',(19.4746871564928,-7.89078289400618,10.9658310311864));
#449=CARTESIAN_POINT('',(19.5329937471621,-7.80689701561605,10.9764520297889));
#450=CARTESIAN_POINT('',(19.56478422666,-7.76785937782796,10.9834901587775));
#451=CARTESIAN_POINT('',(19.6334088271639,-7.69535702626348,11.0008512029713));
#452=CARTESIAN_POINT('',(19.6702436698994,-7.66189311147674,11.0111745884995));
#453=CARTESIAN_POINT('',(19.749529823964,-7.59984488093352,11.0352044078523));
#454=CARTESIAN_POINT('',(19.7921542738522,-7.57153143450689,11.0490369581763));
#455=CARTESIAN_POINT('',(19.8804748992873,-7.52201140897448,11.0793187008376));
#456=CARTESIAN_POINT('',(19.9261718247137,-7.50080657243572,11.0957685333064));
#457=CARTESIAN_POINT('',(20.0235987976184,-7.46410726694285,11.1323071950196));
#458=CARTESIAN_POINT('',(20.075506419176,-7.44927698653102,11.1525886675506));
#459=CARTESIAN_POINT('',(20.1803123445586,-7.42816422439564,11.1950171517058));
#460=CARTESIAN_POINT('',(20.23321145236,-7.42188901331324,11.2171657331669));
#461=CARTESIAN_POINT('',(20.343944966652,-7.41752793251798,11.2649610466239));
#462=CARTESIAN_POINT('',(20.4017567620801,-7.42030180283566,11.2907381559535));
#463=CARTESIAN_POINT('',(20.5156056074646,-7.43562621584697,11.3430780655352));
#464=CARTESIAN_POINT('',(20.5716452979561,-7.44816142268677,11.3696395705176));
#465=CARTESIAN_POINT('',(20.646700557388,-7.47182855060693,11.4063055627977));
#466=CARTESIAN_POINT('',(20.6670487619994,-7.4789769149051,11.4163622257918));
#467=CARTESIAN_POINT('',(20.687137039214,-7.48677485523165,11.4264076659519));
#468=B_SPLINE_CURVE_WITH_KNOTS('',3,(#428,#429,#430,#431,#432,#433,#434,#435,#436,#437,#438,
#439,#440,#441,#442,#443,#444,#445,#446,#447,#448,#449,#450,#451,#452,#453,#454,#455,#456,#457,
#458,#459,#460,#461,#462,#463,#464,#465,#466,#467),.UNSPECIFIED.,.F.,.F.,(4,2,2,2,2,2,2,2,2,2,2,
2,2,2,2,2,2,2,2,4),(0.,0.201427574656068,0.403383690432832,0.605626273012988,0.807657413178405,
0.998768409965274,1.18977079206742,1.36109333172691,1.5322896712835,1.68826466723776,
1.84420958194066,1.99602979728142,2.14787175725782,2.30622670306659,2.46462043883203,
2.63691028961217,2.80934647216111,2.99862495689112,3.18760666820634,3.25895217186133),.UNSPECIFIED.);
#469=CARTESIAN_POINT('',(19.4014701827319,-8.03635207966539,10.9599999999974));
#470=VERTEX_POINT('',#469);
#471=EDGE_CURVE('E535',#470,#425,#468,.T.);
#472=ORIENTED_EDGE('',*,*,#471,.F.);
#473=EDGE_CURVE('E753',#344,#470,#112,.T.);
#474=ORIENTED_EDGE('',*,*,#473,.F.);
#475=EDGE_LOOP('',(#418,#427,#472,#474));
#476=FACE_BOUND('',#475,.T.);
#477=ADVANCED_FACE('F2201',(#476),#51,.T.);
#478=CARTESIAN_POINT('',(19.921767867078,-9.333979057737,11.4263076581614));
#479=VERTEX_POINT('',#478);
#480=EDGE_CURVE('E1054',#479,#470,#468,.T.);
#481=ORIENTED_EDGE('',*,*,#480,.F.);
#482=CARTESIAN_POINT('',(0.,0.,11.4263076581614));
#483=DIRECTION('',(0.,0.,1.));
#484=DIRECTION('',(1.,0.,0.));
#485=AXIS2_PLACEMENT_3D('',#482,#483,#484);
#486=CIRCLE('',#485,22.0000000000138);
#487=CARTESIAN_POINT('',(16.247202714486,-14.833354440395,11.4263076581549));
#488=VERTEX_POINT('',#487);
#489=EDGE_CURVE('E813',#488,#479,#486,.T.);
#490=ORIENTED_EDGE('',*,*,#489,.F.);
#491=CARTESIAN_POINT('',(14.8335456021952,-16.247402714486,11.4264366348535));
#492=CARTESIAN_POINT('',(14.7914358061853,-16.2033896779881,11.3980445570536));
#493=CARTESIAN_POINT('',(14.7533846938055,-16.1555050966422,11.3695868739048));
#494=CARTESIAN_POINT('',(14.686369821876,-16.0532128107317,11.3132933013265));
#495=CARTESIAN_POINT('',(14.6574301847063,-15.9987883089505,11.2854592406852));
#496=CARTESIAN_POINT('',(14.6098067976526,-15.8848006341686,11.2312852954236));
#497=CARTESIAN_POINT('',(14.591137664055,-15.8252302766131,11.2049475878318));
#498=CARTESIAN_POINT('',(14.5651390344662,-15.7026960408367,11.1547661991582));
#499=CARTESIAN_POINT('',(14.5577976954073,-15.6397357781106,11.1309199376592));
#500=CARTESIAN_POINT('',(14.5553561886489,-15.5157836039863,11.087913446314));
#501=CARTESIAN_POINT('',(14.5596154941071,-15.4548693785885,11.0685695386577));
#502=CARTESIAN_POINT('',(14.5795174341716,-15.3337310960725,11.0339223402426));
#503=CARTESIAN_POINT('',(14.5951535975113,-15.2735066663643,11.0186167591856));
#504=CARTESIAN_POINT('',(14.6356102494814,-15.1621664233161,10.9942454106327));
#505=CARTESIAN_POINT('',(14.6593183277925,-15.1107514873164,10.9846991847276));
#506=CARTESIAN_POINT('',(14.7154368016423,-15.0122230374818,10.9700755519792));
#507=CARTESIAN_POINT('',(14.7478407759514,-14.9651063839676,10.964994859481));
#508=CARTESIAN_POINT('',(14.8171371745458,-14.8808692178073,10.9598350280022));
#509=CARTESIAN_POINT('',(14.8533746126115,-14.8432324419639,10.9593514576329));
#510=CARTESIAN_POINT('',(14.9311724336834,-14.7741351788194,10.9623566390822));
#511=CARTESIAN_POINT('',(14.9727317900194,-14.7426735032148,10.9658446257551));
#512=CARTESIAN_POINT('',(15.0587090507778,-14.6875017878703,10.9764735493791));
#513=CARTESIAN_POINT('',(15.1030224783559,-14.663608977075,10.9835155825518));
#514=CARTESIAN_POINT('',(15.1941749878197,-14.6229025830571,11.0008840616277));
#515=CARTESIAN_POINT('',(15.2410144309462,-14.6060900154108,11.0112109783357));
#516=CARTESIAN_POINT('',(15.3380152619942,-14.5791223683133,11.0352479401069));
#517=CARTESIAN_POINT('',(15.3882329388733,-14.5692840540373,11.0490841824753));
#518=CARTESIAN_POINT('',(15.488785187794,-14.5573491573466,11.0793729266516));
#519=CARTESIAN_POINT('',(15.5391197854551,-14.5552544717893,11.0958260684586));
#520=CARTESIAN_POINT('',(15.6431771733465,-14.5586504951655,11.1323714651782));
#521=CARTESIAN_POINT('',(15.6968097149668,-14.564822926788,11.1526563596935));
#522=CARTESIAN_POINT('',(15.8017175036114,-14.5854442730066,11.195091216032));
#523=CARTESIAN_POINT('',(15.8529907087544,-14.5999002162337,11.2172427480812));
#524=CARTESIAN_POINT('',(15.9569609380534,-14.6382676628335,11.2650435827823));
#525=CARTESIAN_POINT('',(16.0093079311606,-14.6629647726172,11.2908232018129));
#526=CARTESIAN_POINT('',(16.1086190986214,-14.7207120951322,11.3431674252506));
#527=CARTESIAN_POINT('',(16.1555915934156,-14.7537491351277,11.3697307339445));
#528=CARTESIAN_POINT('',(16.2158335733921,-14.8043214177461,11.4063769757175));
#529=CARTESIAN_POINT('',(16.2318614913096,-14.8186842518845,11.4164124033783));
#530=CARTESIAN_POINT('',(16.247402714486,-14.8335456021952,11.4264366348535));
#531=B_SPLINE_CURVE_WITH_KNOTS('',3,(#491,#492,#493,#494,#495,#496,#497,#498,#499,#500,#501,
#502,#503,#504,#505,#506,#507,#508,#509,#510,#511,#512,#513,#514,#515,#516,#517,#518,#519,#520,
#521,#522,#523,#524,#525,#526,#527,#528,#529,#530),.UNSPECIFIED.,.F.,.F.,(4,2,2,2,2,2,2,2,2,2,2,
2,2,2,2,2,2,2,2,4),(0.,0.201422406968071,0.403373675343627,0.605611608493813,0.807637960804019,
0.998738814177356,1.18973105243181,1.3610427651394,1.53222832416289,1.68819769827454,
1.84413702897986,1.99595814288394,2.14780102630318,2.30616203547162,2.46456183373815,
2.63686071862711,2.80930601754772,2.99859361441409,3.18758408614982,3.25877905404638),.UNSPECIFIED.);
#532=CARTESIAN_POINT('',(14.8492424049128,-14.8492424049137,10.9599999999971));
#533=VERTEX_POINT('',#532);
#534=EDGE_CURVE('E526',#533,#488,#531,.T.);
#535=ORIENTED_EDGE('',*,*,#534,.F.);
#536=EDGE_CURVE('E756',#470,#533,#112,.T.);
#537=ORIENTED_EDGE('',*,*,#536,.F.);
#538=EDGE_LOOP('',(#481,#490,#535,#537));
#539=FACE_BOUND('',#538,.T.);
#540=ADVANCED_FACE('F2209',(#539),#51,.T.);
#541=CARTESIAN_POINT('',(-9.3339790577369,19.921767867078,11.4263076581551));
#542=VERTEX_POINT('',#541);
#543=EDGE_CURVE('E588',#357,#542,#400,.T.);
#544=ORIENTED_EDGE('',*,*,#543,.F.);
#545=CARTESIAN_POINT('',(-14.8492424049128,14.8492424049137,10.9599999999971));
#546=VERTEX_POINT('',#545);
#547=EDGE_CURVE('E649',#546,#357,#112,.T.);
#548=ORIENTED_EDGE('',*,*,#547,.F.);
#549=CARTESIAN_POINT('',(-14.8335456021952,16.247402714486,11.4264366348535));
#550=CARTESIAN_POINT('',(-14.7914358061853,16.2033896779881,11.3980445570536));
#551=CARTESIAN_POINT('',(-14.7533846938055,16.1555050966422,11.3695868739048));
#552=CARTESIAN_POINT('',(-14.686369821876,16.0532128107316,11.3132933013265));
#553=CARTESIAN_POINT('',(-14.6574301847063,15.9987883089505,11.2854592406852));
#554=CARTESIAN_POINT('',(-14.6098067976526,15.8848006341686,11.2312852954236));
#555=CARTESIAN_POINT('',(-14.5911376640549,15.825230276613,11.2049475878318));
#556=CARTESIAN_POINT('',(-14.5651390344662,15.7026960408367,11.1547661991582));
#557=CARTESIAN_POINT('',(-14.5577976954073,15.6397357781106,11.1309199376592));
#558=CARTESIAN_POINT('',(-14.5553561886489,15.5157836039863,11.087913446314));
#559=CARTESIAN_POINT('',(-14.5596154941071,15.4548693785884,11.0685695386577));
#560=CARTESIAN_POINT('',(-14.5795174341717,15.3337310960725,11.0339223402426));
#561=CARTESIAN_POINT('',(-14.5951535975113,15.2735066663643,11.0186167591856));
#562=CARTESIAN_POINT('',(-14.6356102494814,15.162166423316,10.9942454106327));
#563=CARTESIAN_POINT('',(-14.6593183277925,15.1107514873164,10.9846991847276));
#564=CARTESIAN_POINT('',(-14.7154368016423,15.0122230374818,10.9700755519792));
#565=CARTESIAN_POINT('',(-14.7478407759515,14.9651063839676,10.964994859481));
#566=CARTESIAN_POINT('',(-14.8171371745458,14.8808692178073,10.9598350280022));
#567=CARTESIAN_POINT('',(-14.8533746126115,14.8432324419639,10.9593514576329));
#568=CARTESIAN_POINT('',(-14.9311724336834,14.7741351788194,10.9623566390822));
#569=CARTESIAN_POINT('',(-14.9727317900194,14.7426735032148,10.9658446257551));
#570=CARTESIAN_POINT('',(-15.0587090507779,14.6875017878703,10.9764735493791));
#571=CARTESIAN_POINT('',(-15.1030224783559,14.663608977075,10.9835155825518));
#572=CARTESIAN_POINT('',(-15.1941749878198,14.622902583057,11.0008840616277));
#573=CARTESIAN_POINT('',(-15.2410144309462,14.6060900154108,11.0112109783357));
#574=CARTESIAN_POINT('',(-15.3380152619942,14.5791223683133,11.0352479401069));
#575=CARTESIAN_POINT('',(-15.3882329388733,14.5692840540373,11.0490841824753));
#576=CARTESIAN_POINT('',(-15.488785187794,14.5573491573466,11.0793729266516));
#577=CARTESIAN_POINT('',(-15.5391197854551,14.5552544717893,11.0958260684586));
#578=CARTESIAN_POINT('',(-15.6431771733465,14.5586504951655,11.1323714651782));
#579=CARTESIAN_POINT('',(-15.6968097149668,14.564822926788,11.1526563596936));
#580=CARTESIAN_POINT('',(-15.8017175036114,14.5854442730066,11.195091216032));
#581=CARTESIAN_POINT('',(-15.8529907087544,14.5999002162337,11.2172427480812));
#582=CARTESIAN_POINT('',(-15.9569609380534,14.6382676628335,11.2650435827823));
#583=CARTESIAN_POINT('',(-16.0093079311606,14.6629647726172,11.2908232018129));
#584=CARTESIAN_POINT('',(-16.1086190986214,14.7207120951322,11.3431674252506));
#585=CARTESIAN_POINT('',(-16.1555915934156,14.7537491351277,11.3697307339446));
#586=CARTESIAN_POINT('',(-16.2158335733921,14.8043214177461,11.4063769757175));
#587=CARTESIAN_POINT('',(-16.2318614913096,14.8186842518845,11.4164124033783));
#588=CARTESIAN_POINT('',(-16.247402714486,14.8335456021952,11.4264366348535));
#589=B_SPLINE_CURVE_WITH_KNOTS('',3,(#549,#550,#551,#552,#553,#554,#555,#556,#557,#558,#559,
#560,#561,#562,#563,#564,#565,#566,#567,#568,#569,#570,#571,#572,#573,#574,#575,#576,#577,#578,
#579,#580,#581,#582,#583,#584,#585,#586,#587,#588),.UNSPECIFIED.,.F.,.F.,(4,2,2,2,2,2,2,2,2,2,2,
2,2,2,2,2,2,2,2,4),(0.,0.201422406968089,0.403373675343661,0.605611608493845,0.807637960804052,
0.998738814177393,1.18973105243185,1.36104276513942,1.53222832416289,1.68819769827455,
1.84413702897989,1.99595814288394,2.14780102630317,2.30616203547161,2.46456183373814,
2.63686071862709,2.8093060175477,2.99859361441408,3.18758408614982,3.25877905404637),.UNSPECIFIED.);
#590=CARTESIAN_POINT('',(-14.833354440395,16.247202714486,11.4263076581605));
#591=VERTEX_POINT('',#590);
#592=EDGE_CURVE('E347',#591,#546,#589,.T.);
#593=ORIENTED_EDGE('',*,*,#592,.F.);
#594=CARTESIAN_POINT('',(0.,0.,11.4263076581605));
#595=DIRECTION('',(0.,0.,1.));
#596=DIRECTION('',(1.,0.,0.));
#597=AXIS2_PLACEMENT_3D('',#594,#595,#596);
#598=CIRCLE('',#597,22.0000000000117);
#599=EDGE_CURVE('E800',#542,#591,#598,.T.);
#600=ORIENTED_EDGE('',*,*,#599,.F.);
#601=EDGE_LOOP('',(#544,#548,#593,#600));
#602=FACE_BOUND('',#601,.T.);
#603=ADVANCED_FACE('F650',(#602),#51,.T.);
#604=CARTESIAN_POINT('',(14.833354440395,-16.247202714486,11.4263076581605));
#605=VERTEX_POINT('',#604);
#606=EDGE_CURVE('E1080',#605,#533,#531,.T.);
#607=ORIENTED_EDGE('',*,*,#606,.F.);
#608=CARTESIAN_POINT('',(0.,0.,11.4263076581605));
#609=DIRECTION('',(0.,0.,1.));
#610=DIRECTION('',(1.,0.,0.));
#611=AXIS2_PLACEMENT_3D('',#608,#609,#610);
#612=CIRCLE('',#611,22.0000000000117);
#613=CARTESIAN_POINT('',(9.3339790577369,-19.921767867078,11.4263076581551));
#614=VERTEX_POINT('',#613);
#615=EDGE_CURVE('E815',#614,#605,#612,.T.);
#616=ORIENTED_EDGE('',*,*,#615,.F.);
#617=CARTESIAN_POINT('',(7.48677485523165,-20.687137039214,11.4264076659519));
#618=CARTESIAN_POINT('',(7.46471723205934,-20.6303586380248,11.3980157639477));
#619=CARTESIAN_POINT('',(7.44789094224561,-20.5715568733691,11.3695583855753));
#620=CARTESIAN_POINT('',(7.42513027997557,-20.4514048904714,11.3132656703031));
#621=CARTESIAN_POINT('',(7.4192246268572,-20.3900483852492,11.2854321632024));
#622=CARTESIAN_POINT('',(7.41885498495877,-20.2665131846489,11.2312595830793));
#623=CARTESIAN_POINT('',(7.42440725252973,-20.2043334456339,11.2049226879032));
#624=CARTESIAN_POINT('',(7.44728679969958,-20.0811788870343,11.1547432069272));
#625=CARTESIAN_POINT('',(7.46460175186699,-20.0202028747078,11.1308980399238));
#626=CARTESIAN_POINT('',(7.50978719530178,-19.9047549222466,11.0878941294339));
#627=CARTESIAN_POINT('',(7.53703611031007,-19.8501095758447,11.0685516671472));
#628=CARTESIAN_POINT('',(7.60178616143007,-19.7458132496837,11.0339075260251));
#629=CARTESIAN_POINT('',(7.63928146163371,-19.696159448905,11.0186035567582));
#630=CARTESIAN_POINT('',(7.71927057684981,-19.608782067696,10.9942353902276));
#631=CARTESIAN_POINT('',(7.76085116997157,-19.5703563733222,10.9846907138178));
#632=CARTESIAN_POINT('',(7.85040550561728,-19.500809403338,10.9700701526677));
#633=CARTESIAN_POINT('',(7.89837451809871,-19.4696827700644,10.9649909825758));
#634=CARTESIAN_POINT('',(7.99463357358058,-19.4183819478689,10.9598339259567));
#635=CARTESIAN_POINT('',(8.04251614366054,-19.3974801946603,10.9593516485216));
#636=CARTESIAN_POINT('',(8.1408349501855,-19.3634198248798,10.9623593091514));
#637=CARTESIAN_POINT('',(8.19127069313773,-19.3502597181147,10.9658484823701));
#638=CARTESIAN_POINT('',(8.29181681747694,-19.3321946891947,10.9764796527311));
#639=CARTESIAN_POINT('',(8.34190064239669,-19.3270810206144,10.9835227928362));
#640=CARTESIAN_POINT('',(8.44169217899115,-19.3243605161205,11.0008933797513));
#641=CARTESIAN_POINT('',(8.49139983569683,-19.326754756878,11.0112212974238));
#642=CARTESIAN_POINT('',(8.59133660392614,-19.338965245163,11.0352602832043));
#643=CARTESIAN_POINT('',(8.64149646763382,-19.3490957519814,11.0490975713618));
#644=CARTESIAN_POINT('',(8.73896118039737,-19.3765538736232,11.0793883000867));
#645=CARTESIAN_POINT('',(8.78626532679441,-19.3938832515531,11.0958423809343));
#646=CARTESIAN_POINT('',(8.88110089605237,-19.4368468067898,11.1323896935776));
#647=CARTESIAN_POINT('',(8.92828800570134,-19.4630763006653,11.1526755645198));
#648=CARTESIAN_POINT('',(9.01731665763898,-19.5222795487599,11.1951122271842));
#649=CARTESIAN_POINT('',(9.0591536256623,-19.5552590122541,11.2172645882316));
#650=CARTESIAN_POINT('',(9.14052389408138,-19.6304986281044,11.2650669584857));
#651=CARTESIAN_POINT('',(9.17943314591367,-19.673350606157,11.2908472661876));
#652=CARTESIAN_POINT('',(9.24908159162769,-19.7647116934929,11.3431926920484));
#653=CARTESIAN_POINT('',(9.27983350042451,-19.8132118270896,11.3697565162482));
#654=CARTESIAN_POINT('',(9.31615818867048,-19.8830391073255,11.4064285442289));
#655=CARTESIAN_POINT('',(9.32549047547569,-19.9024925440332,11.4164893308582));
#656=CARTESIAN_POINT('',(9.3341790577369,-19.9222215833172,11.4265388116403));
#657=B_SPLINE_CURVE_WITH_KNOTS('',3,(#617,#618,#619,#620,#621,#622,#623,#624,#625,#626,#627,
#628,#629,#630,#631,#632,#633,#634,#635,#636,#637,#638,#639,#640,#641,#642,#643,#644,#645,#646,
#647,#648,#649,#650,#651,#652,#653,#654,#655,#656),.UNSPECIFIED.,.F.,.F.,(4,2,2,2,2,2,2,2,2,2,2,
2,2,2,2,2,2,2,2,4),(0.,0.201420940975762,0.403370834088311,0.60560744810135,0.807632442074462,
0.998730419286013,1.18971978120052,1.36102842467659,1.53221092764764,1.68817870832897,
1.84411645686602,1.9959378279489,2.14778097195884,2.30614369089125,2.46454521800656,
2.63684671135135,2.80929454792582,2.99858451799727,3.18757768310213,3.25895226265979),.UNSPECIFIED.);
#658=CARTESIAN_POINT('',(8.03635207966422,-19.4014701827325,10.9599999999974));
#659=VERTEX_POINT('',#658);
#660=EDGE_CURVE('E517',#659,#614,#657,.T.);
#661=ORIENTED_EDGE('',*,*,#660,.F.);
#662=EDGE_CURVE('E759',#533,#659,#112,.T.);
#663=ORIENTED_EDGE('',*,*,#662,.F.);
#664=EDGE_LOOP('',(#607,#616,#661,#663));
#665=FACE_BOUND('',#664,.T.);
#666=ADVANCED_FACE('F1183',(#665),#51,.T.);
#667=CARTESIAN_POINT('',(7.48669726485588,-20.686937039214,11.4263076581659));
#668=VERTEX_POINT('',#667);
#669=EDGE_CURVE('E1091',#668,#659,#657,.T.);
#670=ORIENTED_EDGE('',*,*,#669,.F.);
#671=CARTESIAN_POINT('',(0.,0.,11.4263076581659));
#672=DIRECTION('',(0.,0.,1.));
#673=DIRECTION('',(1.,0.,0.));
#674=AXIS2_PLACEMENT_3D('',#671,#672,#673);
#675=CIRCLE('',#674,22.0000000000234);
#676=CARTESIAN_POINT('',(0.99974170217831,-21.977272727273,11.4263076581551));
#677=VERTEX_POINT('',#676);
#678=EDGE_CURVE('E817',#677,#668,#675,.T.);
#679=ORIENTED_EDGE('',*,*,#678,.F.);
#680=CARTESIAN_POINT('',(-0.999746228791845,-21.977472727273,11.4264009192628));
#681=CARTESIAN_POINT('',(-0.998395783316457,-21.9165753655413,11.3980090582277));
#682=CARTESIAN_POINT('',(-0.991437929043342,-21.8558106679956,11.3695517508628));
#683=CARTESIAN_POINT('',(-0.966484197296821,-21.7360950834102,11.3132592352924));
#684=CARTESIAN_POINT('',(-0.948459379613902,-21.6771493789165,11.2854258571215));
#685=CARTESIAN_POINT('',(-0.90152444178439,-21.5628770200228,11.231253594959));
#686=CARTESIAN_POINT('',(-0.872598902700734,-21.5075556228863,11.204916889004));
#687=CARTESIAN_POINT('',(-0.804330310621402,-21.4025322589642,11.1547378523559));
#688=CARTESIAN_POINT('',(-0.764998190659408,-21.3528244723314,11.1308929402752));
#689=CARTESIAN_POINT('',(-0.679071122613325,-21.2634574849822,11.0878896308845));
#690=CARTESIAN_POINT('',(-0.632984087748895,-21.2234001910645,11.0685475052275));
#691=CARTESIAN_POINT('',(-0.533249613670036,-21.1518232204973,11.0339040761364));
#692=CARTESIAN_POINT('',(-0.479606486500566,-21.1202987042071,11.0186004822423));
#693=CARTESIAN_POINT('',(-0.372267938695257,-21.0701845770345,10.9942330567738));
#694=CARTESIAN_POINT('',(-0.319147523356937,-21.0505968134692,10.9846887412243));
#695=CARTESIAN_POINT('',(-0.209795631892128,-21.0206162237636,10.9700688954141));
#696=CARTESIAN_POINT('',(-0.153566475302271,-21.0102166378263,10.9649900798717));
#697=CARTESIAN_POINT('',(-0.0450029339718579,-20.9996589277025,10.9598336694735));
#698=CARTESIAN_POINT('',(0.00723343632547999,-20.9986727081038,10.9593516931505));
#699=CARTESIAN_POINT('',(0.111102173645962,-21.0048311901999,10.9623599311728));
#700=CARTESIAN_POINT('',(0.162734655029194,-21.0119743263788,10.9658493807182));
#701=CARTESIAN_POINT('',(0.262539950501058,-21.0337628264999,10.9764810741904));
#702=CARTESIAN_POINT('',(0.310768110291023,-21.0482051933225,10.9835244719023));
#703=CARTESIAN_POINT('',(0.404004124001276,-21.083881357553,11.0008955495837));
#704=CARTESIAN_POINT('',(0.4490115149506,-21.1051161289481,11.0112237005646));
#705=CARTESIAN_POINT('',(0.536667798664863,-21.1546422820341,11.0352631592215));
#706=CARTESIAN_POINT('',(0.579132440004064,-21.1831975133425,11.0491006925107));
#707=CARTESIAN_POINT('',(0.658669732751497,-21.2458646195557,11.0793918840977));
#708=CARTESIAN_POINT('',(0.695741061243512,-21.2799778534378,11.0958461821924));
#709=CARTESIAN_POINT('',(0.766915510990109,-21.3559639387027,11.1323939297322));
#710=CARTESIAN_POINT('',(0.800472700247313,-21.3982550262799,11.1526800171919));
#711=CARTESIAN_POINT('',(0.860067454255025,-21.4870224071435,11.1951171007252));
#712=CARTESIAN_POINT('',(0.886098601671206,-21.533502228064,11.2172696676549));
#713=CARTESIAN_POINT('',(0.93248090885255,-21.6341545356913,11.2650724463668));
#714=CARTESIAN_POINT('',(0.952029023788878,-21.6886349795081,11.2908529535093));
#715=CARTESIAN_POINT('',(0.981412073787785,-21.7996956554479,11.3431986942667));
#716=CARTESIAN_POINT('',(0.991262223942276,-21.8562724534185,11.3697626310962));
#717=CARTESIAN_POINT('',(0.998090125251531,-21.9345827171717,11.4063866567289));
#718=CARTESIAN_POINT('',(0.999264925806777,-21.9560235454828,11.4163993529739));
#719=CARTESIAN_POINT('',(0.999746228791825,-21.977472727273,11.4264009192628));
#720=B_SPLINE_CURVE_WITH_KNOTS('',3,(#680,#681,#682,#683,#684,#685,#686,#687,#688,#689,#690,
#691,#692,#693,#694,#695,#696,#697,#698,#699,#700,#701,#702,#703,#704,#705,#706,#707,#708,#709,
#710,#711,#712,#713,#714,#715,#716,#717,#718,#719),.UNSPECIFIED.,.F.,.F.,(4,2,2,2,2,2,2,2,2,2,2,
2,2,2,2,2,2,2,2,4),(0.,0.201420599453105,0.403370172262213,0.60560647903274,0.807631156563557,
0.998728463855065,1.18971715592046,1.36102508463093,1.53220687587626,1.68817428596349,
1.84411166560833,1.99593309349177,2.14777630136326,2.30613943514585,2.46454134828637,
2.63684336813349,2.80929187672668,2.99858276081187,3.18757619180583,3.25861009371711),.UNSPECIFIED.);
#721=CARTESIAN_POINT('',(-6.40111010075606E-13,-20.9999999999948,10.9599999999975));
#722=VERTEX_POINT('',#721);
#723=EDGE_CURVE('E508',#722,#677,#720,.T.);
#724=ORIENTED_EDGE('',*,*,#723,.F.);
#725=EDGE_CURVE('E762',#659,#722,#112,.T.);
#726=ORIENTED_EDGE('',*,*,#725,.F.);
#727=EDGE_LOOP('',(#670,#679,#724,#726));
#728=FACE_BOUND('',#727,.T.);
#729=ADVANCED_FACE('F1178',(#728),#51,.T.);
#730=CARTESIAN_POINT('',(-16.247202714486,14.833354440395,11.4263076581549));
#731=VERTEX_POINT('',#730);
#732=EDGE_CURVE('E355',#546,#731,#589,.T.);
#733=ORIENTED_EDGE('',*,*,#732,.F.);
#734=CARTESIAN_POINT('',(-19.4014701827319,8.0363520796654,10.9599999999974));
#735=VERTEX_POINT('',#734);
#736=EDGE_CURVE('E643',#735,#546,#112,.T.);
#737=ORIENTED_EDGE('',*,*,#736,.F.);
#738=CARTESIAN_POINT('',(-19.9222215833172,9.334179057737,11.4265388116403));
#739=CARTESIAN_POINT('',(-19.8664672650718,9.30964258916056,11.3981461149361));
#740=CARTESIAN_POINT('',(-19.8129803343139,9.27997543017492,11.3696873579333));
#741=CARTESIAN_POINT('',(-19.7119044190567,9.21113560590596,11.313390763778));
#742=CARTESIAN_POINT('',(-19.6643312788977,9.1719382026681,11.28555475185));
#743=CARTESIAN_POINT('',(-19.576692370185,9.08486965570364,11.231375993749));
#744=CARTESIAN_POINT('',(-19.5366373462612,9.03698628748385,11.2050354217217));
#745=CARTESIAN_POINT('',(-19.4657037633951,8.93374305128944,11.1548473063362));
#746=CARTESIAN_POINT('',(-19.4348156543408,8.87839105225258,11.1309971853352));
#747=CARTESIAN_POINT('',(-19.3851008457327,8.76481700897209,11.0879815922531));
#748=CARTESIAN_POINT('',(-19.3657124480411,8.70691181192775,11.068632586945));
#749=CARTESIAN_POINT('',(-19.3377165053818,8.58738031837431,11.0339746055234));
#750=CARTESIAN_POINT('',(-19.3291028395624,8.52575615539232,11.0186633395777));
#751=CARTESIAN_POINT('',(-19.323848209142,8.40740529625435,10.9942807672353));
#752=CARTESIAN_POINT('',(-19.3260650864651,8.35082820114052,10.9847290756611));
#753=CARTESIAN_POINT('',(-19.3401859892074,8.23831565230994,10.9700946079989));
#754=CARTESIAN_POINT('',(-19.3520828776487,8.18237975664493,10.9650085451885));
#755=CARTESIAN_POINT('',(-19.3838508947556,8.07802564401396,10.9598389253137));
#756=CARTESIAN_POINT('',(-19.4029189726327,8.02938120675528,10.9593507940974));
#757=CARTESIAN_POINT('',(-19.4483378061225,7.93576018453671,10.9623472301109));
#758=CARTESIAN_POINT('',(-19.4746871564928,7.89078289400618,10.9658310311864));
#759=CARTESIAN_POINT('',(-19.5329937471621,7.80689701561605,10.9764520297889));
#760=CARTESIAN_POINT('',(-19.56478422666,7.76785937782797,10.9834901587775));
#761=CARTESIAN_POINT('',(-19.6334088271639,7.69535702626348,11.0008512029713));
#762=CARTESIAN_POINT('',(-19.6702436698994,7.66189311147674,11.0111745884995));
#763=CARTESIAN_POINT('',(-19.749529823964,7.59984488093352,11.0352044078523));
#764=CARTESIAN_POINT('',(-19.7921542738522,7.5715314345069,11.0490369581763));
#765=CARTESIAN_POINT('',(-19.8804748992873,7.52201140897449,11.0793187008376));
#766=CARTESIAN_POINT('',(-19.9261718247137,7.50080657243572,11.0957685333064));
#767=CARTESIAN_POINT('',(-20.0235987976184,7.46410726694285,11.1323071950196));
#768=CARTESIAN_POINT('',(-20.075506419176,7.44927698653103,11.1525886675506));
#769=CARTESIAN_POINT('',(-20.1803123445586,7.42816422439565,11.1950171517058));
#770=CARTESIAN_POINT('',(-20.23321145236,7.42188901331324,11.2171657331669));
#771=CARTESIAN_POINT('',(-20.343944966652,7.41752793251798,11.2649610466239));
#772=CARTESIAN_POINT('',(-20.4017567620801,7.42030180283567,11.2907381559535));
#773=CARTESIAN_POINT('',(-20.5156056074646,7.43562621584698,11.3430780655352));
#774=CARTESIAN_POINT('',(-20.5716452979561,7.44816142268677,11.3696395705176));
#775=CARTESIAN_POINT('',(-20.646700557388,7.47182855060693,11.4063055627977));
#776=CARTESIAN_POINT('',(-20.6670487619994,7.4789769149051,11.4163622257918));
#777=CARTESIAN_POINT('',(-20.687137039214,7.48677485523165,11.4264076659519));
#778=B_SPLINE_CURVE_WITH_KNOTS('',3,(#738,#739,#740,#741,#742,#743,#744,#745,#746,#747,#748,
#749,#750,#751,#752,#753,#754,#755,#756,#757,#758,#759,#760,#761,#762,#763,#764,#765,#766,#767,
#768,#769,#770,#771,#772,#773,#774,#775,#776,#777),.UNSPECIFIED.,.F.,.F.,(4,2,2,2,2,2,2,2,2,2,2,
2,2,2,2,2,2,2,2,4),(0.,0.201427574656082,0.403383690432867,0.605626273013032,0.807657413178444,
0.998768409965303,1.18977079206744,1.36109333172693,1.53228967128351,1.68826466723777,
1.84420958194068,1.99602979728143,2.14787175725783,2.3062267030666,2.46462043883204,
2.63691028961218,2.80934647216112,2.99862495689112,3.18760666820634,3.25895217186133),.UNSPECIFIED.);
#779=CARTESIAN_POINT('',(-19.921767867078,9.333979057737,11.4263076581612));
#780=VERTEX_POINT('',#779);
#781=EDGE_CURVE('E345',#780,#735,#778,.T.);
#782=ORIENTED_EDGE('',*,*,#781,.F.);
#783=CARTESIAN_POINT('',(0.,0.,11.4263076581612));
#784=DIRECTION('',(0.,0.,1.));
#785=DIRECTION('',(1.,0.,0.));
#786=AXIS2_PLACEMENT_3D('',#783,#784,#785);
#787=CIRCLE('',#786,22.0000000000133);
#788=EDGE_CURVE('E645',#731,#780,#787,.T.);
#789=ORIENTED_EDGE('',*,*,#788,.F.);
#790=EDGE_LOOP('',(#733,#737,#782,#789));
#791=FACE_BOUND('',#790,.T.);
#792=ADVANCED_FACE('F640',(#791),#51,.T.);
#793=CARTESIAN_POINT('',(-0.999741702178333,-21.977272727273,11.4263076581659));
#794=VERTEX_POINT('',#793);
#795=EDGE_CURVE('E1117',#794,#722,#720,.T.);
#796=ORIENTED_EDGE('',*,*,#795,.F.);
#797=CARTESIAN_POINT('',(0.,0.,11.4263076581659));
#798=DIRECTION('',(0.,0.,1.));
#799=DIRECTION('',(1.,0.,0.));
#800=AXIS2_PLACEMENT_3D('',#797,#798,#799);
#801=CIRCLE('',#800,22.0000000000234);
#802=CARTESIAN_POINT('',(-7.4866972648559,-20.686937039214,11.426307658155));
#803=VERTEX_POINT('',#802);
#804=EDGE_CURVE('E819',#803,#794,#801,.T.);
#805=ORIENTED_EDGE('',*,*,#804,.F.);
#806=CARTESIAN_POINT('',(-9.334179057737,-19.9222215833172,11.4265388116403));
#807=CARTESIAN_POINT('',(-9.30964258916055,-19.8664672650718,11.3981461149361));
#808=CARTESIAN_POINT('',(-9.27997543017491,-19.8129803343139,11.3696873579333));
#809=CARTESIAN_POINT('',(-9.21113560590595,-19.7119044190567,11.313390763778));
#810=CARTESIAN_POINT('',(-9.17193820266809,-19.6643312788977,11.28555475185));
#811=CARTESIAN_POINT('',(-9.08486965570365,-19.576692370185,11.231375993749));
#812=CARTESIAN_POINT('',(-9.03698628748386,-19.5366373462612,11.2050354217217));
#813=CARTESIAN_POINT('',(-8.93374305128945,-19.4657037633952,11.1548473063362));
#814=CARTESIAN_POINT('',(-8.87839105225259,-19.4348156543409,11.1309971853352));
#815=CARTESIAN_POINT('',(-8.7648170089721,-19.3851008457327,11.0879815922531));
#816=CARTESIAN_POINT('',(-8.70691181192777,-19.3657124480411,11.068632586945));
#817=CARTESIAN_POINT('',(-8.58738031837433,-19.3377165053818,11.0339746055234));
#818=CARTESIAN_POINT('',(-8.52575615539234,-19.3291028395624,11.0186633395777));
#819=CARTESIAN_POINT('',(-8.40740529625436,-19.323848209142,10.9942807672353));
#820=CARTESIAN_POINT('',(-8.35082820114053,-19.3260650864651,10.9847290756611));
#821=CARTESIAN_POINT('',(-8.23831565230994,-19.3401859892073,10.9700946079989));
#822=CARTESIAN_POINT('',(-8.18237975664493,-19.3520828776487,10.9650085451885));
#823=CARTESIAN_POINT('',(-8.07802564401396,-19.3838508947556,10.9598389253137));
#824=CARTESIAN_POINT('',(-8.02938120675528,-19.4029189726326,10.9593507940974));
#825=CARTESIAN_POINT('',(-7.93576018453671,-19.4483378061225,10.9623472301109));
#826=CARTESIAN_POINT('',(-7.89078289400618,-19.4746871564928,10.9658310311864));
#827=CARTESIAN_POINT('',(-7.80689701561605,-19.5329937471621,10.9764520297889));
#828=CARTESIAN_POINT('',(-7.76785937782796,-19.56478422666,10.9834901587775));
#829=CARTESIAN_POINT('',(-7.69535702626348,-19.6334088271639,11.0008512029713));
#830=CARTESIAN_POINT('',(-7.66189311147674,-19.6702436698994,11.0111745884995));
#831=CARTESIAN_POINT('',(-7.59984488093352,-19.749529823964,11.0352044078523));
#832=CARTESIAN_POINT('',(-7.57153143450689,-19.7921542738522,11.0490369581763));
#833=CARTESIAN_POINT('',(-7.52201140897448,-19.8804748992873,11.0793187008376));
#834=CARTESIAN_POINT('',(-7.50080657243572,-19.9261718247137,11.0957685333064));
#835=CARTESIAN_POINT('',(-7.46410726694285,-20.0235987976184,11.1323071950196));
#836=CARTESIAN_POINT('',(-7.44927698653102,-20.075506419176,11.1525886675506));
#837=CARTESIAN_POINT('',(-7.42816422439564,-20.1803123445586,11.1950171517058));
#838=CARTESIAN_POINT('',(-7.42188901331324,-20.23321145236,11.2171657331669));
#839=CARTESIAN_POINT('',(-7.41752793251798,-20.343944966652,11.2649610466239));
#840=CARTESIAN_POINT('',(-7.42030180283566,-20.4017567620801,11.2907381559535));
#841=CARTESIAN_POINT('',(-7.43562621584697,-20.5156056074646,11.3430780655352));
#842=CARTESIAN_POINT('',(-7.44816142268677,-20.5716452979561,11.3696395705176));
#843=CARTESIAN_POINT('',(-7.47182855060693,-20.646700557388,11.4063055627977));
#844=CARTESIAN_POINT('',(-7.4789769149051,-20.6670487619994,11.4163622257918));
#845=CARTESIAN_POINT('',(-7.48677485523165,-20.687137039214,11.4264076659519));
#846=B_SPLINE_CURVE_WITH_KNOTS('',3,(#806,#807,#808,#809,#810,#811,#812,#813,#814,#815,#816,
#817,#818,#819,#820,#821,#822,#823,#824,#825,#826,#827,#828,#829,#830,#831,#832,#833,#834,#835,
#836,#837,#838,#839,#840,#841,#842,#843,#844,#845),.UNSPECIFIED.,.F.,.F.,(4,2,2,2,2,2,2,2,2,2,2,
2,2,2,2,2,2,2,2,4),(0.,0.201427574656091,0.403383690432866,0.605626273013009,0.807657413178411,
0.998768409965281,1.18977079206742,1.36109333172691,1.5322896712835,1.68826466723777,
1.84420958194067,1.99602979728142,2.14787175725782,2.3062267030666,2.46462043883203,
2.63691028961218,2.80934647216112,2.99862495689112,3.18760666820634,3.25895217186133),.UNSPECIFIED.);
#847=CARTESIAN_POINT('',(-8.03635207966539,-19.4014701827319,10.9599999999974));
#848=VERTEX_POINT('',#847);
#849=EDGE_CURVE('E499',#848,#803,#846,.T.);
#850=ORIENTED_EDGE('',*,*,#849,.F.);
#851=EDGE_CURVE('E765',#722,#848,#112,.T.);
#852=ORIENTED_EDGE('',*,*,#851,.F.);
#853=EDGE_LOOP('',(#796,#805,#850,#852));
#854=FACE_BOUND('',#853,.T.);
#855=ADVANCED_FACE('F1171',(#854),#51,.T.);
#856=CARTESIAN_POINT('',(-9.333979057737,-19.921767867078,11.4263076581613));
#857=VERTEX_POINT('',#856);
#858=EDGE_CURVE('E1128',#857,#848,#846,.T.);
#859=ORIENTED_EDGE('',*,*,#858,.F.);
#860=CARTESIAN_POINT('',(0.,0.,11.4263076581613));
#861=DIRECTION('',(0.,0.,1.));
#862=DIRECTION('',(1.,0.,0.));
#863=AXIS2_PLACEMENT_3D('',#860,#861,#862);
#864=CIRCLE('',#863,22.0000000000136);
#865=CARTESIAN_POINT('',(-14.833354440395,-16.247202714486,11.4263076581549));
#866=VERTEX_POINT('',#865);
#867=EDGE_CURVE('E821',#866,#857,#864,.T.);
#868=ORIENTED_EDGE('',*,*,#867,.F.);
#869=CARTESIAN_POINT('',(-16.247402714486,-14.8335456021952,11.4264366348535));
#870=CARTESIAN_POINT('',(-16.2033896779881,-14.7914358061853,11.3980445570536));
#871=CARTESIAN_POINT('',(-16.1555050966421,-14.7533846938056,11.3695868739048));
#872=CARTESIAN_POINT('',(-16.0532128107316,-14.6863698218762,11.3132933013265));
#873=CARTESIAN_POINT('',(-15.9987883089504,-14.6574301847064,11.2854592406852));
#874=CARTESIAN_POINT('',(-15.8848006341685,-14.6098067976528,11.2312852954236));
#875=CARTESIAN_POINT('',(-15.8252302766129,-14.5911376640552,11.2049475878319));
#876=CARTESIAN_POINT('',(-15.7026960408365,-14.5651390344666,11.1547661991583));
#877=CARTESIAN_POINT('',(-15.6397357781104,-14.5577976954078,11.1309199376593));
#878=CARTESIAN_POINT('',(-15.5157836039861,-14.5553561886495,11.0879134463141));
#879=CARTESIAN_POINT('',(-15.4548693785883,-14.5596154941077,11.0685695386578));
#880=CARTESIAN_POINT('',(-15.3337310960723,-14.5795174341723,11.0339223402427));
#881=CARTESIAN_POINT('',(-15.2735066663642,-14.595153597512,11.0186167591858));
#882=CARTESIAN_POINT('',(-15.162166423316,-14.6356102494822,10.9942454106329));
#883=CARTESIAN_POINT('',(-15.1107514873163,-14.6593183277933,10.9846991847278));
#884=CARTESIAN_POINT('',(-15.0122230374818,-14.7154368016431,10.9700755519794));
#885=CARTESIAN_POINT('',(-14.9651063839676,-14.7478407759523,10.9649948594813));
#886=CARTESIAN_POINT('',(-14.8808692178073,-14.8171371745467,10.9598350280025));
#887=CARTESIAN_POINT('',(-14.843232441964,-14.8533746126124,10.9593514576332));
#888=CARTESIAN_POINT('',(-14.7741351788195,-14.9311724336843,10.9623566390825));
#889=CARTESIAN_POINT('',(-14.742673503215,-14.9727317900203,10.9658446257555));
#890=CARTESIAN_POINT('',(-14.6875017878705,-15.0587090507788,10.9764735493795));
#891=CARTESIAN_POINT('',(-14.6636089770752,-15.1030224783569,10.9835155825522));
#892=CARTESIAN_POINT('',(-14.6229025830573,-15.1941749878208,11.0008840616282));
#893=CARTESIAN_POINT('',(-14.6060900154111,-15.2410144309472,11.0112109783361));
#894=CARTESIAN_POINT('',(-14.5791223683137,-15.3380152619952,11.0352479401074));
#895=CARTESIAN_POINT('',(-14.5692840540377,-15.3882329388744,11.0490841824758));
#896=CARTESIAN_POINT('',(-14.557349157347,-15.4887851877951,11.0793729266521));
#897=CARTESIAN_POINT('',(-14.5552544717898,-15.5391197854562,11.0958260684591));
#898=CARTESIAN_POINT('',(-14.558650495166,-15.6431771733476,11.1323714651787));
#899=CARTESIAN_POINT('',(-14.5648229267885,-15.696809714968,11.1526563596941));
#900=CARTESIAN_POINT('',(-14.5854442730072,-15.8017175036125,11.1950912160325));
#901=CARTESIAN_POINT('',(-14.5999002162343,-15.8529907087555,11.2172427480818));
#902=CARTESIAN_POINT('',(-14.6382676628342,-15.9569609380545,11.2650435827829));
#903=CARTESIAN_POINT('',(-14.662964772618,-16.0093079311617,11.2908232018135));
#904=CARTESIAN_POINT('',(-14.720712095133,-16.1086190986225,11.3431674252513));
#905=CARTESIAN_POINT('',(-14.7537491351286,-16.1555915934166,11.3697307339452));
#906=CARTESIAN_POINT('',(-14.8043214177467,-16.2158335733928,11.4063769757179));
#907=CARTESIAN_POINT('',(-14.8186842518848,-16.2318614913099,11.4164124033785));
#908=CARTESIAN_POINT('',(-14.8335456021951,-16.247402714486,11.4264366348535));
#909=B_SPLINE_CURVE_WITH_KNOTS('',3,(#869,#870,#871,#872,#873,#874,#875,#876,#877,#878,#879,
#880,#881,#882,#883,#884,#885,#886,#887,#888,#889,#890,#891,#892,#893,#894,#895,#896,#897,#898,
#899,#900,#901,#902,#903,#904,#905,#906,#907,#908),.UNSPECIFIED.,.F.,.F.,(4,2,2,2,2,2,2,2,2,2,2,
2,2,2,2,2,2,2,2,4),(0.,0.201422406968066,0.403373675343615,0.605611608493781,0.807637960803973,
0.998738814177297,1.18973105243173,1.36104276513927,1.53222832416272,1.68819769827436,
1.84413702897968,1.99595814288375,2.147801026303,2.30616203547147,2.46456183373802,
2.63686071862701,2.80930601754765,2.99859361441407,3.18758408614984,3.25877905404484),.UNSPECIFIED.);
#910=CARTESIAN_POINT('',(-14.8492424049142,-14.8492424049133,10.9599999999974));
#911=VERTEX_POINT('',#910);
#912=EDGE_CURVE('E490',#911,#866,#909,.T.);
#913=ORIENTED_EDGE('',*,*,#912,.F.);
#914=EDGE_CURVE('E768',#848,#911,#112,.T.);
#915=ORIENTED_EDGE('',*,*,#914,.F.);
#916=EDGE_LOOP('',(#859,#868,#913,#915));
#917=FACE_BOUND('',#916,.T.);
#918=ADVANCED_FACE('F1163',(#917),#51,.T.);
#919=CARTESIAN_POINT('',(-20.686937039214,7.4866972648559,11.426307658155));
#920=VERTEX_POINT('',#919);
#921=EDGE_CURVE('E342',#735,#920,#778,.T.);
#922=ORIENTED_EDGE('',*,*,#921,.F.);
#923=CARTESIAN_POINT('',(-21.,0.,10.96));
#924=VERTEX_POINT('',#923);
#925=EDGE_CURVE('E658',#924,#735,#112,.T.);
#926=ORIENTED_EDGE('',*,*,#925,.F.);
#927=CARTESIAN_POINT('',(-21.977472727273,0.999746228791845,11.4264009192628));
#928=CARTESIAN_POINT('',(-21.9165753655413,0.998395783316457,11.3980090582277));
#929=CARTESIAN_POINT('',(-21.8558106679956,0.991437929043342,11.3695517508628));
#930=CARTESIAN_POINT('',(-21.7360950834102,0.966484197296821,11.3132592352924));
#931=CARTESIAN_POINT('',(-21.6771493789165,0.948459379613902,11.2854258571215));
#932=CARTESIAN_POINT('',(-21.5628770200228,0.90152444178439,11.231253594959));
#933=CARTESIAN_POINT('',(-21.5075556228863,0.872598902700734,11.204916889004));
#934=CARTESIAN_POINT('',(-21.4025322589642,0.804330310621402,11.1547378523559));
#935=CARTESIAN_POINT('',(-21.3528244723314,0.764998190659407,11.1308929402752));
#936=CARTESIAN_POINT('',(-21.2634574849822,0.679071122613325,11.0878896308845));
#937=CARTESIAN_POINT('',(-21.2234001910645,0.632984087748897,11.0685475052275));
#938=CARTESIAN_POINT('',(-21.1518232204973,0.533249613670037,11.0339040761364));
#939=CARTESIAN_POINT('',(-21.1202987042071,0.479606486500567,11.0186004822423));
#940=CARTESIAN_POINT('',(-21.0701845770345,0.372267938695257,10.9942330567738));
#941=CARTESIAN_POINT('',(-21.0505968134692,0.319147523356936,10.9846887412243));
#942=CARTESIAN_POINT('',(-21.0206162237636,0.209795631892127,10.9700688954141));
#943=CARTESIAN_POINT('',(-21.0102166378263,0.153566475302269,10.9649900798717));
#944=CARTESIAN_POINT('',(-20.9996589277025,0.0450029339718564,10.9598336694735));
#945=CARTESIAN_POINT('',(-20.9986727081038,-0.00723343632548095,10.9593516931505));
#946=CARTESIAN_POINT('',(-21.0048311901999,-0.111102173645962,10.9623599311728));
#947=CARTESIAN_POINT('',(-21.0119743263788,-0.162734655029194,10.9658493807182));
#948=CARTESIAN_POINT('',(-21.0337628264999,-0.262539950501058,10.9764810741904));
#949=CARTESIAN_POINT('',(-21.0482051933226,-0.310768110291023,10.9835244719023));
#950=CARTESIAN_POINT('',(-21.083881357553,-0.404004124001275,11.0008955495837));
#951=CARTESIAN_POINT('',(-21.1051161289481,-0.449011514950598,11.0112237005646));
#952=CARTESIAN_POINT('',(-21.1546422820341,-0.536667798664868,11.0352631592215));
#953=CARTESIAN_POINT('',(-21.1831975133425,-0.579132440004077,11.0491006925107));
#954=CARTESIAN_POINT('',(-21.2458646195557,-0.658669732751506,11.0793918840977));
#955=CARTESIAN_POINT('',(-21.2799778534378,-0.69574106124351,11.0958461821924));
#956=CARTESIAN_POINT('',(-21.3559639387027,-0.766915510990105,11.1323939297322));
#957=CARTESIAN_POINT('',(-21.3982550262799,-0.800472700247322,11.1526800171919));
#958=CARTESIAN_POINT('',(-21.4870224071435,-0.860067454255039,11.1951171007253));
#959=CARTESIAN_POINT('',(-21.533502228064,-0.88609860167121,11.2172696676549));
#960=CARTESIAN_POINT('',(-21.6341545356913,-0.932480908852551,11.2650724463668));
#961=CARTESIAN_POINT('',(-21.6886349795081,-0.952029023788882,11.2908529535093));
#962=CARTESIAN_POINT('',(-21.799695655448,-0.981412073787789,11.3431986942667));
#963=CARTESIAN_POINT('',(-21.8562724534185,-0.991262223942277,11.3697626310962));
#964=CARTESIAN_POINT('',(-21.9345827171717,-0.998090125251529,11.4063866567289));
#965=CARTESIAN_POINT('',(-21.9560235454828,-0.999264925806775,11.4163993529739));
#966=CARTESIAN_POINT('',(-21.977472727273,-0.999746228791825,11.4264009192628));
#967=B_SPLINE_CURVE_WITH_KNOTS('',3,(#927,#928,#929,#930,#931,#932,#933,#934,#935,#936,#937,
#938,#939,#940,#941,#942,#943,#944,#945,#946,#947,#948,#949,#950,#951,#952,#953,#954,#955,#956,
#957,#958,#959,#960,#961,#962,#963,#964,#965,#966),.UNSPECIFIED.,.F.,.F.,(4,2,2,2,2,2,2,2,2,2,2,
2,2,2,2,2,2,2,2,4),(0.,0.201420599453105,0.403370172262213,0.60560647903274,0.807631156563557,
0.998728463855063,1.18971715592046,1.36102508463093,1.53220687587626,1.68817428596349,
1.84411166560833,1.99593309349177,2.14777630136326,2.30613943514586,2.4645413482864,
2.63684336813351,2.80929187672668,2.99858276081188,3.18757619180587,3.25861009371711),.UNSPECIFIED.);
#968=CARTESIAN_POINT('',(-21.977272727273,0.99974170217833,11.4263076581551));
#969=VERTEX_POINT('',#968);
#970=EDGE_CURVE('E29',#969,#924,#967,.T.);
#971=ORIENTED_EDGE('',*,*,#970,.F.);
#972=CARTESIAN_POINT('',(0.,0.,11.426307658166));
#973=DIRECTION('',(0.,0.,1.));
#974=DIRECTION('',(1.,0.,0.));
#975=AXIS2_PLACEMENT_3D('',#972,#973,#974);
#976=CIRCLE('',#975,22.0000000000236);
#977=EDGE_CURVE('E331',#920,#969,#976,.T.);
#978=ORIENTED_EDGE('',*,*,#977,.F.);
#979=EDGE_LOOP('',(#922,#926,#971,#978));
#980=FACE_BOUND('',#979,.T.);
#981=ADVANCED_FACE('F832',(#980),#51,.T.);
#982=CARTESIAN_POINT('',(-16.247202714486,-14.833354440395,11.4263076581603));
#983=VERTEX_POINT('',#982);
#984=EDGE_CURVE('E1152',#983,#911,#909,.T.);
#985=ORIENTED_EDGE('',*,*,#984,.F.);
#986=CARTESIAN_POINT('',(0.,0.,11.4263076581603));
#987=DIRECTION('',(0.,0.,1.));
#988=DIRECTION('',(1.,0.,0.));
#989=AXIS2_PLACEMENT_3D('',#986,#987,#988);
#990=CIRCLE('',#989,22.0000000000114);
#991=CARTESIAN_POINT('',(-19.921767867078,-9.3339790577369,11.4263076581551));
#992=VERTEX_POINT('',#991);
#993=EDGE_CURVE('E823',#992,#983,#990,.T.);
#994=ORIENTED_EDGE('',*,*,#993,.F.);
#995=CARTESIAN_POINT('',(-20.687137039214,-7.48677485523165,11.4264076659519));
#996=CARTESIAN_POINT('',(-20.6303586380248,-7.46471723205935,11.3980157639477));
#997=CARTESIAN_POINT('',(-20.5715568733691,-7.44789094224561,11.3695583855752));
#998=CARTESIAN_POINT('',(-20.4514048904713,-7.42513027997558,11.3132656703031));
#999=CARTESIAN_POINT('',(-20.3900483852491,-7.41922462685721,11.2854321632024));
#1000=CARTESIAN_POINT('',(-20.2665131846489,-7.41885498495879,11.2312595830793));
#1001=CARTESIAN_POINT('',(-20.2043334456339,-7.42440725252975,11.2049226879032));
#1002=CARTESIAN_POINT('',(-20.0811788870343,-7.44728679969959,11.1547432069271));
#1003=CARTESIAN_POINT('',(-20.0202028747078,-7.46460175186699,11.1308980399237));
#1004=CARTESIAN_POINT('',(-19.9047549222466,-7.50978719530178,11.0878941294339));
#1005=CARTESIAN_POINT('',(-19.8501095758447,-7.53703611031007,11.0685516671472));
#1006=CARTESIAN_POINT('',(-19.7458132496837,-7.60178616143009,11.0339075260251));
#1007=CARTESIAN_POINT('',(-19.696159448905,-7.63928146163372,11.0186035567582));
#1008=CARTESIAN_POINT('',(-19.608782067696,-7.71927057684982,10.9942353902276));
#1009=CARTESIAN_POINT('',(-19.5703563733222,-7.76085116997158,10.9846907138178));
#1010=CARTESIAN_POINT('',(-19.500809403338,-7.85040550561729,10.9700701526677));
#1011=CARTESIAN_POINT('',(-19.4696827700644,-7.89837451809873,10.9649909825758));
#1012=CARTESIAN_POINT('',(-19.4183819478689,-7.9946335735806,10.9598339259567));
#1013=CARTESIAN_POINT('',(-19.3974801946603,-8.04251614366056,10.9593516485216));
#1014=CARTESIAN_POINT('',(-19.3634198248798,-8.14083495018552,10.9623593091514));
#1015=CARTESIAN_POINT('',(-19.3502597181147,-8.19127069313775,10.9658484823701));
#1016=CARTESIAN_POINT('',(-19.3321946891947,-8.29181681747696,10.9764796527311));
#1017=CARTESIAN_POINT('',(-19.3270810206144,-8.34190064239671,10.9835227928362));
#1018=CARTESIAN_POINT('',(-19.3243605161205,-8.44169217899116,11.0008933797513));
#1019=CARTESIAN_POINT('',(-19.326754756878,-8.49139983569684,11.0112212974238));
#1020=CARTESIAN_POINT('',(-19.338965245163,-8.59133660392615,11.0352602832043));
#1021=CARTESIAN_POINT('',(-19.3490957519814,-8.64149646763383,11.0490975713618));
#1022=CARTESIAN_POINT('',(-19.3765538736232,-8.73896118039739,11.0793883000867));
#1023=CARTESIAN_POINT('',(-19.3938832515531,-8.78626532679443,11.0958423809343));
#1024=CARTESIAN_POINT('',(-19.4368468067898,-8.8811008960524,11.1323896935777));
#1025=CARTESIAN_POINT('',(-19.4630763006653,-8.92828800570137,11.1526755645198));
#1026=CARTESIAN_POINT('',(-19.5222795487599,-9.01731665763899,11.1951122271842));
#1027=CARTESIAN_POINT('',(-19.5552590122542,-9.05915362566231,11.2172645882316));
#1028=CARTESIAN_POINT('',(-19.6304986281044,-9.14052389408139,11.2650669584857));
#1029=CARTESIAN_POINT('',(-19.673350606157,-9.1794331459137,11.2908472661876));
#1030=CARTESIAN_POINT('',(-19.7647116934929,-9.24908159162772,11.3431926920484));
#1031=CARTESIAN_POINT('',(-19.8132118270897,-9.27983350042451,11.3697565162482));
#1032=CARTESIAN_POINT('',(-19.8830391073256,-9.31615818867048,11.4064285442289));
#1033=CARTESIAN_POINT('',(-19.9024925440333,-9.32549047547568,11.4164893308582));
#1034=CARTESIAN_POINT('',(-19.9222215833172,-9.3341790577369,11.4265388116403));
#1035=B_SPLINE_CURVE_WITH_KNOTS('',3,(#995,#996,#997,#998,#999,#1000,#1001,#1002,#1003,#1004,
#1005,#1006,#1007,#1008,#1009,#1010,#1011,#1012,#1013,#1014,#1015,#1016,#1017,#1018,#1019,#1020,
#1021,#1022,#1023,#1024,#1025,#1026,#1027,#1028,#1029,#1030,#1031,#1032,#1033,#1034),
.UNSPECIFIED.,.F.,.F.,(4,2,2,2,2,2,2,2,2,2,2,2,2,2,2,2,2,2,2,4),(0.,0.201420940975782,
0.403370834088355,0.60560744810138,0.807632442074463,0.998730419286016,1.18971978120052,
1.36102842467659,1.53221092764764,1.68817870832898,1.84411645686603,1.9959378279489,
2.14778097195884,2.30614369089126,2.46454521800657,2.63684671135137,2.80929454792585,
2.9985845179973,3.18757768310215,3.25895226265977),.UNSPECIFIED.);
#1036=CARTESIAN_POINT('',(-19.4014701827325,-8.03635207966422,10.9599999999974));
#1037=VERTEX_POINT('',#1036);
#1038=EDGE_CURVE('E481',#1037,#992,#1035,.T.);
#1039=ORIENTED_EDGE('',*,*,#1038,.F.);
#1040=EDGE_CURVE('E771',#911,#1037,#112,.T.);
#1041=ORIENTED_EDGE('',*,*,#1040,.F.);
#1042=EDGE_LOOP('',(#985,#994,#1039,#1041));
#1043=FACE_BOUND('',#1042,.T.);
#1044=ADVANCED_FACE('F429',(#1043),#51,.T.);
#1045=CARTESIAN_POINT('',(0.,0.,0.3));
#1046=DIRECTION('',(0.,0.,1.));
#1047=DIRECTION('',(1.,0.,0.));
#1048=AXIS2_PLACEMENT_3D('',#1045,#1046,#1047);
#1049=CONICAL_SURFACE('',#1048,7.5,0.78539816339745);
#1050=CARTESIAN_POINT('',(0.,0.,1.3));
#1051=DIRECTION('',(0.,0.,-1.));
#1052=DIRECTION('',(-1.,0.,0.));
#1053=AXIS2_PLACEMENT_3D('',#1050,#1051,#1052);
#1054=CIRCLE('',#1053,8.5);
#1055=CARTESIAN_POINT('',(-8.5,0.,1.3));
#1056=VERTEX_POINT('',#1055);
#1057=EDGE_CURVE('E687',#1056,#1056,#1054,.T.);
#1058=ORIENTED_EDGE('',*,*,#1057,.T.);
#1059=EDGE_LOOP('',(#1058));
#1060=FACE_BOUND('',#1059,.T.);
#1061=ORIENTED_EDGE('',*,*,#31,.F.);
#1062=EDGE_LOOP('',(#1061));
#1063=FACE_BOUND('',#1062,.T.);
#1064=ADVANCED_FACE('F425',(#1060,#1063),#1049,.T.);
#1065=CARTESIAN_POINT('',(0.,0.,24.));
#1066=DIRECTION('',(0.,0.,-1.));
#1067=DIRECTION('',(-1.,0.,0.));
#1068=AXIS2_PLACEMENT_3D('',#1065,#1066,#1067);
#1069=CYLINDRICAL_SURFACE('',#1068,8.5);
#1070=CARTESIAN_POINT('',(0.,0.,19.));
#1071=DIRECTION('',(0.,0.,-1.));
#1072=DIRECTION('',(-1.,0.,0.));
#1073=AXIS2_PLACEMENT_3D('',#1070,#1071,#1072);
#1074=CIRCLE('',#1073,8.5);
#1075=CARTESIAN_POINT('',(-8.5,0.,19.));
#1076=VERTEX_POINT('',#1075);
#1077=EDGE_CURVE('E684',#1076,#1076,#1074,.T.);
#1078=ORIENTED_EDGE('',*,*,#1077,.T.);
#1079=EDGE_LOOP('',(#1078));
#1080=FACE_BOUND('',#1079,.T.);
#1081=ORIENTED_EDGE('',*,*,#1057,.F.);
#1082=EDGE_LOOP('',(#1081));
#1083=FACE_BOUND('',#1082,.T.);
#1084=ADVANCED_FACE('F428',(#1080,#1083),#1069,.T.);
#1085=CARTESIAN_POINT('',(0.,0.,19.0000000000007));
#1086=DIRECTION('',(0.,0.,-1.));
#1087=DIRECTION('',(-1.,0.,0.));
#1088=AXIS2_PLACEMENT_3D('',#1085,#1086,#1087);
#1089=TOROIDAL_SURFACE('',#1088,9.4999999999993,0.999999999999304);
#1090=CARTESIAN_POINT('',(0.,0.,20.));
#1091=DIRECTION('',(0.,0.,-1.));
#1092=DIRECTION('',(-1.,0.,0.));
#1093=AXIS2_PLACEMENT_3D('',#1090,#1091,#1092);
#1094=CIRCLE('',#1093,9.5);
#1095=CARTESIAN_POINT('',(-9.5,0.,20.));
#1096=VERTEX_POINT('',#1095);
#1097=EDGE_CURVE('E681',#1096,#1096,#1094,.T.);
#1098=ORIENTED_EDGE('',*,*,#1097,.T.);
#1099=EDGE_LOOP('',(#1098));
#1100=FACE_BOUND('',#1099,.T.);
#1101=ORIENTED_EDGE('',*,*,#1077,.F.);
#1102=EDGE_LOOP('',(#1101));
#1103=FACE_BOUND('',#1102,.T.);
#1104=ADVANCED_FACE('F433',(#1100,#1103),#1089,.F.);
#1105=CARTESIAN_POINT('',(0.,9.5,20.));
#1106=DIRECTION('',(0.,0.,-1.));
#1107=DIRECTION('',(-1.,0.,0.));
#1108=AXIS2_PLACEMENT_3D('',#1105,#1106,#1107);
#1109=PLANE('',#1108);
#1110=CARTESIAN_POINT('',(0.,0.,20.));
#1111=DIRECTION('',(0.,0.,-1.));
#1112=DIRECTION('',(-1.,0.,0.));
#1113=AXIS2_PLACEMENT_3D('',#1110,#1111,#1112);
#1114=CIRCLE('',#1113,15.923076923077);
#1115=CARTESIAN_POINT('',(-15.923076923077,0.,20.));
#1116=VERTEX_POINT('',#1115);
#1117=EDGE_CURVE('E678',#1116,#1116,#1114,.T.);
#1118=ORIENTED_EDGE('',*,*,#1117,.T.);
#1119=EDGE_LOOP('',(#1118));
#1120=FACE_BOUND('',#1119,.T.);
#1121=ORIENTED_EDGE('',*,*,#1097,.F.);
#1122=EDGE_LOOP('',(#1121));
#1123=FACE_BOUND('',#1122,.T.);
#1124=ADVANCED_FACE('F437',(#1120,#1123),#1109,.T.);
#1125=CARTESIAN_POINT('',(0.,0.,19.));
#1126=DIRECTION('',(0.,0.,-1.));
#1127=DIRECTION('',(-1.,0.,0.));
#1128=AXIS2_PLACEMENT_3D('',#1125,#1126,#1127);
#1129=TOROIDAL_SURFACE('',#1128,15.9230769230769,1.00000000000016);
#1130=CARTESIAN_POINT('',(0.,0.,19.));
#1131=DIRECTION('',(0.,0.,-1.));
#1132=DIRECTION('',(-1.,0.,0.));
#1133=AXIS2_PLACEMENT_3D('',#1130,#1131,#1132);
#1134=CIRCLE('',#1133,16.923076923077);
#1135=CARTESIAN_POINT('',(-16.923076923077,0.,19.));
#1136=VERTEX_POINT('',#1135);
#1137=EDGE_CURVE('E675',#1136,#1136,#1134,.T.);
#1138=ORIENTED_EDGE('',*,*,#1137,.T.);
#1139=EDGE_LOOP('',(#1138));
#1140=FACE_BOUND('',#1139,.T.);
#1141=ORIENTED_EDGE('',*,*,#1117,.F.);
#1142=EDGE_LOOP('',(#1141));
#1143=FACE_BOUND('',#1142,.T.);
#1144=ADVANCED_FACE('F441',(#1140,#1143),#1129,.F.);
#1145=CARTESIAN_POINT('',(0.,0.,24.));
#1146=DIRECTION('',(0.,0.,-1.));
#1147=DIRECTION('',(-1.,0.,0.));
#1148=AXIS2_PLACEMENT_3D('',#1145,#1146,#1147);
#1149=CYLINDRICAL_SURFACE('',#1148,16.923076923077);
#1150=CARTESIAN_POINT('',(0.,0.,10.));
#1151=DIRECTION('',(0.,0.,-1.));
#1152=DIRECTION('',(-1.,0.,0.));
#1153=AXIS2_PLACEMENT_3D('',#1150,#1151,#1152);
#1154=CIRCLE('',#1153,16.923076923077);
#1155=CARTESIAN_POINT('',(-16.923076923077,0.,10.));
#1156=VERTEX_POINT('',#1155);
#1157=EDGE_CURVE('E672',#1156,#1156,#1154,.T.);
#1158=ORIENTED_EDGE('',*,*,#1157,.T.);
#1159=EDGE_LOOP('',(#1158));
#1160=FACE_BOUND('',#1159,.T.);
#1161=ORIENTED_EDGE('',*,*,#1137,.F.);
#1162=EDGE_LOOP('',(#1161));
#1163=FACE_BOUND('',#1162,.T.);
#1164=ADVANCED_FACE('F445',(#1160,#1163),#1149,.F.);
#1165=CARTESIAN_POINT('',(0.,16.923076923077,10.));
#1166=DIRECTION('',(0.,0.,-1.));
#1167=DIRECTION('',(-1.,0.,0.));
#1168=AXIS2_PLACEMENT_3D('',#1165,#1166,#1167);
#1169=PLANE('',#1168);
#1170=CARTESIAN_POINT('',(0.,0.,10.));
#1171=DIRECTION('',(0.,0.,-1.));
#1172=DIRECTION('',(-1.,0.,0.));
#1173=AXIS2_PLACEMENT_3D('',#1170,#1171,#1172);
#1174=CIRCLE('',#1173,19.5);
#1175=CARTESIAN_POINT('',(-19.5,0.,10.));
#1176=VERTEX_POINT('',#1175);
#1177=EDGE_CURVE('E669',#1176,#1176,#1174,.T.);
#1178=ORIENTED_EDGE('',*,*,#1177,.T.);
#1179=EDGE_LOOP('',(#1178));
#1180=FACE_BOUND('',#1179,.T.);
#1181=ORIENTED_EDGE('',*,*,#1157,.F.);
#1182=EDGE_LOOP('',(#1181));
#1183=FACE_BOUND('',#1182,.T.);
#1184=ADVANCED_FACE('F449',(#1180,#1183),#1169,.T.);
#1185=CARTESIAN_POINT('',(0.,0.,10.5000000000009));
#1186=DIRECTION('',(0.,0.,-1.));
#1187=DIRECTION('',(-1.,0.,0.));
#1188=AXIS2_PLACEMENT_3D('',#1185,#1186,#1187);
#1189=TOROIDAL_SURFACE('',#1188,19.499999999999,0.500000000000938);
#1190=CARTESIAN_POINT('',(0.,0.,10.5));
#1191=DIRECTION('',(0.,0.,-1.));
#1192=DIRECTION('',(-1.,0.,0.));
#1193=AXIS2_PLACEMENT_3D('',#1190,#1191,#1192);
#1194=CIRCLE('',#1193,20.);
#1195=CARTESIAN_POINT('',(-20.,0.,10.5));
#1196=VERTEX_POINT('',#1195);
#1197=EDGE_CURVE('E666',#1196,#1196,#1194,.T.);
#1198=ORIENTED_EDGE('',*,*,#1197,.T.);
#1199=EDGE_LOOP('',(#1198));
#1200=FACE_BOUND('',#1199,.T.);
#1201=ORIENTED_EDGE('',*,*,#1177,.F.);
#1202=EDGE_LOOP('',(#1201));
#1203=FACE_BOUND('',#1202,.T.);
#1204=ADVANCED_FACE('F453',(#1200,#1203),#1189,.T.);
#1205=CARTESIAN_POINT('',(0.,0.,24.));
#1206=DIRECTION('',(0.,0.,-1.));
#1207=DIRECTION('',(-1.,0.,0.));
#1208=AXIS2_PLACEMENT_3D('',#1205,#1206,#1207);
#1209=CYLINDRICAL_SURFACE('',#1208,20.);
#1210=CARTESIAN_POINT('',(0.,0.,10.96));
#1211=DIRECTION('',(0.,0.,-1.));
#1212=DIRECTION('',(-1.,0.,0.));
#1213=AXIS2_PLACEMENT_3D('',#1210,#1211,#1212);
#1214=CIRCLE('',#1213,20.);
#1215=CARTESIAN_POINT('',(-20.,0.,10.96));
#1216=VERTEX_POINT('',#1215);
#1217=EDGE_CURVE('E659',#1216,#1216,#1214,.T.);
#1218=ORIENTED_EDGE('',*,*,#1217,.T.);
#1219=EDGE_LOOP('',(#1218));
#1220=FACE_BOUND('',#1219,.T.);
#1221=ORIENTED_EDGE('',*,*,#1197,.F.);
#1222=EDGE_LOOP('',(#1221));
#1223=FACE_BOUND('',#1222,.T.);
#1224=ADVANCED_FACE('F457',(#1220,#1223),#1209,.T.);
#1225=CARTESIAN_POINT('',(0.,20.,10.96));
#1226=DIRECTION('',(0.,0.,-1.));
#1227=DIRECTION('',(-1.,0.,0.));
#1228=AXIS2_PLACEMENT_3D('',#1225,#1226,#1227);
#1229=PLANE('',#1228);
#1230=ORIENTED_EDGE('',*,*,#925,.T.);
#1231=ORIENTED_EDGE('',*,*,#736,.T.);
#1232=ORIENTED_EDGE('',*,*,#547,.T.);
#1233=ORIENTED_EDGE('',*,*,#358,.T.);
#1234=ORIENTED_EDGE('',*,*,#169,.T.);
#1235=ORIENTED_EDGE('',*,*,#115,.T.);
#1236=ORIENTED_EDGE('',*,*,#284,.T.);
#1237=ORIENTED_EDGE('',*,*,#347,.T.);
#1238=ORIENTED_EDGE('',*,*,#473,.T.);
#1239=ORIENTED_EDGE('',*,*,#536,.T.);
#1240=ORIENTED_EDGE('',*,*,#662,.T.);
#1241=ORIENTED_EDGE('',*,*,#725,.T.);
#1242=ORIENTED_EDGE('',*,*,#851,.T.);
#1243=ORIENTED_EDGE('',*,*,#914,.T.);
#1244=ORIENTED_EDGE('',*,*,#1040,.T.);
#1245=EDGE_CURVE('E660',#1037,#924,#112,.T.);
#1246=ORIENTED_EDGE('',*,*,#1245,.T.);
#1247=EDGE_LOOP('',(#1230,#1231,#1232,#1233,#1234,#1235,#1236,#1237,#1238,#1239,#1240,#1241,
#1242,#1243,#1244,#1246));
#1248=FACE_BOUND('',#1247,.T.);
#1249=ORIENTED_EDGE('',*,*,#1217,.F.);
#1250=EDGE_LOOP('',(#1249));
#1251=FACE_BOUND('',#1250,.T.);
#1252=ADVANCED_FACE('F461',(#1248,#1251),#1229,.T.);
#1253=CARTESIAN_POINT('',(-20.686937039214,-7.4866972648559,11.426307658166));
#1254=VERTEX_POINT('',#1253);
#1255=EDGE_CURVE('E875',#1254,#1037,#1035,.T.);
#1256=ORIENTED_EDGE('',*,*,#1255,.F.);
#1257=CARTESIAN_POINT('',(0.,0.,11.426307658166));
#1258=DIRECTION('',(0.,0.,1.));
#1259=DIRECTION('',(1.,0.,0.));
#1260=AXIS2_PLACEMENT_3D('',#1257,#1258,#1259);
#1261=CIRCLE('',#1260,22.0000000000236);
#1262=CARTESIAN_POINT('',(-21.977272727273,-0.99974170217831,11.4263076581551));
#1263=VERTEX_POINT('',#1262);
#1264=EDGE_CURVE('E824',#1263,#1254,#1261,.T.);
#1265=ORIENTED_EDGE('',*,*,#1264,.F.);
#1266=EDGE_CURVE('E471',#924,#1263,#967,.T.);
#1267=ORIENTED_EDGE('',*,*,#1266,.F.);
#1268=ORIENTED_EDGE('',*,*,#1245,.F.);
#1269=EDGE_LOOP('',(#1256,#1265,#1267,#1268));
#1270=FACE_BOUND('',#1269,.T.);
#1271=ADVANCED_FACE('F421',(#1270),#51,.T.);
#1272=CARTESIAN_POINT('',(2.31186597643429E-11,-5.15386344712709E-12,24.));
#1273=DIRECTION('',(0.,0.,-1.));
#1274=DIRECTION('',(-1.,0.,0.));
#1275=AXIS2_PLACEMENT_3D('',#1272,#1273,#1274);
#1276=CYLINDRICAL_SURFACE('',#1275,22.0000000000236);
#1277=ORIENTED_EDGE('',*,*,#977,.T.);
#1278=DIRECTION('',(0.,0.,-1.));
#1279=VECTOR('',#1278,1.);
#1280=CARTESIAN_POINT('',(-21.977272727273,0.99974170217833,24.));
#1281=LINE('',#1280,#1279);
#1282=CARTESIAN_POINT('',(-21.977272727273,0.99974170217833,22.5736923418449));
#1283=VERTEX_POINT('',#1282);
#1284=EDGE_CURVE('E319',#1283,#969,#1281,.T.);
#1285=ORIENTED_EDGE('',*,*,#1284,.F.);
#1286=CARTESIAN_POINT('',(0.,0.,22.573692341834));
#1287=DIRECTION('',(0.,0.,-1.));
#1288=DIRECTION('',(-1.,0.,0.));
#1289=AXIS2_PLACEMENT_3D('',#1286,#1287,#1288);
#1290=CIRCLE('',#1289,22.0000000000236);
#1291=CARTESIAN_POINT('',(-20.686937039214,7.4866972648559,22.5736923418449));
#1292=VERTEX_POINT('',#1291);
#1293=EDGE_CURVE('E9',#1283,#1292,#1290,.T.);
#1294=ORIENTED_EDGE('',*,*,#1293,.T.);
#1295=DIRECTION('',(0.,0.,-1.));
#1296=VECTOR('',#1295,1.);
#1297=CARTESIAN_POINT('',(-20.686937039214,7.4866972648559,24.));
#1298=LINE('',#1297,#1296);
#1299=EDGE_CURVE('E324',#1292,#920,#1298,.T.);
#1300=ORIENTED_EDGE('',*,*,#1299,.T.);
#1301=EDGE_LOOP('',(#1277,#1285,#1294,#1300));
#1302=FACE_BOUND('',#1301,.T.);
#1303=ADVANCED_FACE('F327',(#1302),#1276,.T.);
#1304=CARTESIAN_POINT('',(-20.3253497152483,8.41903551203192,24.));
#1305=DIRECTION('',(0.,0.,-1.));
#1306=DIRECTION('',(-1.,0.,0.));
#1307=AXIS2_PLACEMENT_3D('',#1304,#1305,#1306);
#1308=CYLINDRICAL_SURFACE('',#1307,0.999999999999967);
#1309=ORIENTED_EDGE('',*,*,#781,.T.);
#1310=ORIENTED_EDGE('',*,*,#921,.T.);
#1311=ORIENTED_EDGE('',*,*,#1299,.F.);
#1312=CARTESIAN_POINT('',(-20.687137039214,7.48677485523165,22.5735923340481));
#1313=CARTESIAN_POINT('',(-20.6303586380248,7.46471723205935,22.6019842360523));
#1314=CARTESIAN_POINT('',(-20.5715568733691,7.44789094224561,22.6304416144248));
#1315=CARTESIAN_POINT('',(-20.4514048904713,7.42513027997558,22.6867343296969));
#1316=CARTESIAN_POINT('',(-20.3900483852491,7.41922462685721,22.7145678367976));
#1317=CARTESIAN_POINT('',(-20.2665131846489,7.4188549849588,22.7687404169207));
#1318=CARTESIAN_POINT('',(-20.2043334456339,7.42440725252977,22.7950773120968));
#1319=CARTESIAN_POINT('',(-20.0811788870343,7.44728679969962,22.8452567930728));
#1320=CARTESIAN_POINT('',(-20.0202028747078,7.46460175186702,22.8691019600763));
#1321=CARTESIAN_POINT('',(-19.9047549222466,7.50978719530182,22.9121058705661));
#1322=CARTESIAN_POINT('',(-19.8501095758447,7.53703611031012,22.9314483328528));
#1323=CARTESIAN_POINT('',(-19.7458132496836,7.60178616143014,22.9660924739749));
#1324=CARTESIAN_POINT('',(-19.6961594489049,7.63928146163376,22.9813964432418));
#1325=CARTESIAN_POINT('',(-19.608782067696,7.71927057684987,23.0057646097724));
#1326=CARTESIAN_POINT('',(-19.5703563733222,7.76085116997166,23.0153092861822));
#1327=CARTESIAN_POINT('',(-19.500809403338,7.85040550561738,23.0299298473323));
#1328=CARTESIAN_POINT('',(-19.4696827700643,7.89837451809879,23.0350090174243));
#1329=CARTESIAN_POINT('',(-19.4183819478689,7.99463357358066,23.0401660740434));
#1330=CARTESIAN_POINT('',(-19.3974801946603,8.04251614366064,23.0406483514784));
#1331=CARTESIAN_POINT('',(-19.3634198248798,8.1408349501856,23.0376406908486));
#1332=CARTESIAN_POINT('',(-19.3502597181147,8.19127069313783,23.0341515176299));
#1333=CARTESIAN_POINT('',(-19.3321946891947,8.29181681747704,23.0235203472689));
#1334=CARTESIAN_POINT('',(-19.3270810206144,8.34190064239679,23.0164772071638));
#1335=CARTESIAN_POINT('',(-19.3243605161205,8.44169217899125,22.9991066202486));
#1336=CARTESIAN_POINT('',(-19.326754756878,8.49139983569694,22.9887787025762));
#1337=CARTESIAN_POINT('',(-19.338965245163,8.59133660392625,22.9647397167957));
#1338=CARTESIAN_POINT('',(-19.3490957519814,8.64149646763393,22.9509024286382));
#1339=CARTESIAN_POINT('',(-19.3765538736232,8.73896118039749,22.9206116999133));
#1340=CARTESIAN_POINT('',(-19.3938832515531,8.78626532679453,22.9041576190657));
#1341=CARTESIAN_POINT('',(-19.4368468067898,8.88110089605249,22.8676103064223));
#1342=CARTESIAN_POINT('',(-19.4630763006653,8.92828800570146,22.8473244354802));
#1343=CARTESIAN_POINT('',(-19.5222795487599,9.01731665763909,22.8048877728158));
#1344=CARTESIAN_POINT('',(-19.5552590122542,9.05915362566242,22.7827354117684));
#1345=CARTESIAN_POINT('',(-19.6304986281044,9.1405238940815,22.7349330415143));
#1346=CARTESIAN_POINT('',(-19.673350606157,9.17943314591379,22.7091527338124));
#1347=CARTESIAN_POINT('',(-19.7647116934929,9.24908159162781,22.6568073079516));
#1348=CARTESIAN_POINT('',(-19.8132118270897,9.27983350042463,22.6302434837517));
#1349=CARTESIAN_POINT('',(-19.8830391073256,9.3161581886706,22.5935714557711));
#1350=CARTESIAN_POINT('',(-19.9024925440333,9.32549047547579,22.5835106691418));
#1351=CARTESIAN_POINT('',(-19.9222215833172,9.334179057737,22.5734611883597));
#1352=B_SPLINE_CURVE_WITH_KNOTS('',3,(#1312,#1313,#1314,#1315,#1316,#1317,#1318,#1319,#1320,
#1321,#1322,#1323,#1324,#1325,#1326,#1327,#1328,#1329,#1330,#1331,#1332,#1333,#1334,#1335,#1336,
#1337,#1338,#1339,#1340,#1341,#1342,#1343,#1344,#1345,#1346,#1347,#1348,#1349,#1350,#1351),
.UNSPECIFIED.,.F.,.F.,(4,2,2,2,2,2,2,2,2,2,2,2,2,2,2,2,2,2,2,4),(0.,0.201420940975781,
0.403370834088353,0.605607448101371,0.80763244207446,0.998730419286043,1.18971978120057,
1.36102842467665,1.5322109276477,1.68817870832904,1.84411645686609,1.99593782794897,
2.14778097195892,2.30614369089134,2.46454521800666,2.63684671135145,2.80929454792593,
2.99858451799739,3.18757768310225,3.25895226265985),.UNSPECIFIED.);
#1353=CARTESIAN_POINT('',(-19.4014701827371,8.03635207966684,23.04));
#1354=VERTEX_POINT('',#1353);
#1355=EDGE_CURVE('E337',#1292,#1354,#1352,.T.);
#1356=ORIENTED_EDGE('',*,*,#1355,.T.);
#1357=CARTESIAN_POINT('',(-19.921767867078,9.333979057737,22.5736923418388));
#1358=VERTEX_POINT('',#1357);
#1359=EDGE_CURVE('E343',#1354,#1358,#1352,.T.);
#1360=ORIENTED_EDGE('',*,*,#1359,.T.);
#1361=DIRECTION('',(0.,0.,-1.));
#1362=VECTOR('',#1361,1.);
#1363=CARTESIAN_POINT('',(-19.921767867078,9.333979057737,24.));
#1364=LINE('',#1363,#1362);
#1365=EDGE_CURVE('E723',#1358,#780,#1364,.T.);
#1366=ORIENTED_EDGE('',*,*,#1365,.T.);
#1367=EDGE_LOOP('',(#1309,#1310,#1311,#1356,#1360,#1366));
#1368=FACE_BOUND('',#1367,.T.);
#1369=ADVANCED_FACE('F371',(#1368),#1308,.F.);
#1370=CARTESIAN_POINT('',(1.00319058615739E-11,-9.16454412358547E-12,24.));
#1371=DIRECTION('',(0.,0.,-1.));
#1372=DIRECTION('',(-1.,0.,0.));
#1373=AXIS2_PLACEMENT_3D('',#1370,#1371,#1372);
#1374=CYLINDRICAL_SURFACE('',#1373,22.0000000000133);
#1375=ORIENTED_EDGE('',*,*,#788,.T.);
#1376=ORIENTED_EDGE('',*,*,#1365,.F.);
#1377=CARTESIAN_POINT('',(0.,0.,22.5736923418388));
#1378=DIRECTION('',(0.,0.,-1.));
#1379=DIRECTION('',(-1.,0.,0.));
#1380=AXIS2_PLACEMENT_3D('',#1377,#1378,#1379);
#1381=CIRCLE('',#1380,22.0000000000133);
#1382=CARTESIAN_POINT('',(-16.247202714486,14.833354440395,22.5736923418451));
#1383=VERTEX_POINT('',#1382);
#1384=EDGE_CURVE('E22',#1358,#1383,#1381,.T.);
#1385=ORIENTED_EDGE('',*,*,#1384,.T.);
#1386=DIRECTION('',(0.,0.,-1.));
#1387=VECTOR('',#1386,1.);
#1388=CARTESIAN_POINT('',(-16.247202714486,14.833354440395,24.));
#1389=LINE('',#1388,#1387);
#1390=EDGE_CURVE('E721',#1383,#731,#1389,.T.);
#1391=ORIENTED_EDGE('',*,*,#1390,.T.);
#1392=EDGE_LOOP('',(#1375,#1376,#1385,#1391));
#1393=FACE_BOUND('',#1392,.T.);
#1394=ADVANCED_FACE('F376',(#1393),#1374,.T.);
#1395=CARTESIAN_POINT('',(-15.5563491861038,15.5563491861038,24.));
#1396=DIRECTION('',(0.,0.,-1.));
#1397=DIRECTION('',(-1.,0.,0.));
#1398=AXIS2_PLACEMENT_3D('',#1395,#1396,#1397);
#1399=CYLINDRICAL_SURFACE('',#1398,1.00000000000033);
#1400=ORIENTED_EDGE('',*,*,#592,.T.);
#1401=ORIENTED_EDGE('',*,*,#732,.T.);
#1402=ORIENTED_EDGE('',*,*,#1390,.F.);
#1403=CARTESIAN_POINT('',(-16.247402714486,14.8335456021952,22.5735633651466));
#1404=CARTESIAN_POINT('',(-16.2033896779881,14.7914358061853,22.6019554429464));
#1405=CARTESIAN_POINT('',(-16.1555050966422,14.7533846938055,22.6304131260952));
#1406=CARTESIAN_POINT('',(-16.0532128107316,14.686369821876,22.6867066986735));
#1407=CARTESIAN_POINT('',(-15.9987883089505,14.6574301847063,22.7145407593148));
#1408=CARTESIAN_POINT('',(-15.8848006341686,14.6098067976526,22.7687147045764));
#1409=CARTESIAN_POINT('',(-15.825230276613,14.5911376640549,22.7950524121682));
#1410=CARTESIAN_POINT('',(-15.7026960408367,14.5651390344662,22.8452338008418));
#1411=CARTESIAN_POINT('',(-15.6397357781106,14.5577976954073,22.8690800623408));
#1412=CARTESIAN_POINT('',(-15.5157836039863,14.5553561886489,22.912086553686));
#1413=CARTESIAN_POINT('',(-15.4548693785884,14.5596154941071,22.9314304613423));
#1414=CARTESIAN_POINT('',(-15.3337310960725,14.5795174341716,22.9660776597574));
#1415=CARTESIAN_POINT('',(-15.2735066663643,14.5951535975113,22.9813832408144));
#1416=CARTESIAN_POINT('',(-15.1621664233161,14.6356102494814,23.0057545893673));
#1417=CARTESIAN_POINT('',(-15.1107514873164,14.6593183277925,23.0153008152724));
#1418=CARTESIAN_POINT('',(-15.0122230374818,14.7154368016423,23.0299244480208));
#1419=CARTESIAN_POINT('',(-14.9651063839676,14.7478407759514,23.035005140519));
#1420=CARTESIAN_POINT('',(-14.8808692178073,14.8171371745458,23.0401649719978));
#1421=CARTESIAN_POINT('',(-14.8432324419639,14.8533746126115,23.0406485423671));
#1422=CARTESIAN_POINT('',(-14.7741351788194,14.9311724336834,23.0376433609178));
#1423=CARTESIAN_POINT('',(-14.7426735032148,14.9727317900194,23.0341553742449));
#1424=CARTESIAN_POINT('',(-14.6875017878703,15.0587090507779,23.0235264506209));
#1425=CARTESIAN_POINT('',(-14.663608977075,15.1030224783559,23.0164844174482));
#1426=CARTESIAN_POINT('',(-14.622902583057,15.1941749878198,22.9991159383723));
#1427=CARTESIAN_POINT('',(-14.6060900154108,15.2410144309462,22.9887890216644));
#1428=CARTESIAN_POINT('',(-14.5791223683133,15.3380152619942,22.9647520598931));
#1429=CARTESIAN_POINT('',(-14.5692840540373,15.3882329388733,22.9509158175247));
#1430=CARTESIAN_POINT('',(-14.5573491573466,15.488785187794,22.9206270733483));
#1431=CARTESIAN_POINT('',(-14.5552544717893,15.5391197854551,22.9041739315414));
#1432=CARTESIAN_POINT('',(-14.5586504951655,15.6431771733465,22.8676285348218));
#1433=CARTESIAN_POINT('',(-14.564822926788,15.6968097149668,22.8473436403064));
#1434=CARTESIAN_POINT('',(-14.5854442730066,15.8017175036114,22.804908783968));
#1435=CARTESIAN_POINT('',(-14.5999002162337,15.8529907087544,22.7827572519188));
#1436=CARTESIAN_POINT('',(-14.6382676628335,15.9569609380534,22.7349564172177));
#1437=CARTESIAN_POINT('',(-14.6629647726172,16.0093079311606,22.7091767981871));
#1438=CARTESIAN_POINT('',(-14.7207120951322,16.1086190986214,22.6568325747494));
#1439=CARTESIAN_POINT('',(-14.7537491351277,16.1555915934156,22.6302692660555));
#1440=CARTESIAN_POINT('',(-14.8043214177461,16.2158335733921,22.5936230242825));
#1441=CARTESIAN_POINT('',(-14.8186842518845,16.2318614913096,22.5835875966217));
#1442=CARTESIAN_POINT('',(-14.8335456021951,16.247402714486,22.5735633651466));
#1443=B_SPLINE_CURVE_WITH_KNOTS('',3,(#1403,#1404,#1405,#1406,#1407,#1408,#1409,#1410,#1411,
#1412,#1413,#1414,#1415,#1416,#1417,#1418,#1419,#1420,#1421,#1422,#1423,#1424,#1425,#1426,#1427,
#1428,#1429,#1430,#1431,#1432,#1433,#1434,#1435,#1436,#1437,#1438,#1439,#1440,#1441,#1442),
.UNSPECIFIED.,.F.,.F.,(4,2,2,2,2,2,2,2,2,2,2,2,2,2,2,2,2,2,2,4),(0.,0.20142240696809,
0.403373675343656,0.605611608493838,0.807637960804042,0.998738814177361,1.18973105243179,
1.36104276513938,1.53222832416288,1.68819769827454,1.84413702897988,1.99595814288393,
2.14780102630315,2.3061620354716,2.46456183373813,2.63686071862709,2.80930601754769,
2.99859361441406,3.18758408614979,3.25877905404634),.UNSPECIFIED.);
#1444=CARTESIAN_POINT('',(-14.849242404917,14.849242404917,23.04));
#1445=VERTEX_POINT('',#1444);
#1446=EDGE_CURVE('E646',#1383,#1445,#1443,.T.);
#1447=ORIENTED_EDGE('',*,*,#1446,.T.);
#1448=CARTESIAN_POINT('',(-14.833354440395,16.247202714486,22.5736923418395));
#1449=VERTEX_POINT('',#1448);
#1450=EDGE_CURVE('E601',#1445,#1449,#1443,.T.);
#1451=ORIENTED_EDGE('',*,*,#1450,.T.);
#1452=DIRECTION('',(0.,0.,-1.));
#1453=VECTOR('',#1452,1.);
#1454=CARTESIAN_POINT('',(-14.833354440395,16.247202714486,24.));
#1455=LINE('',#1454,#1453);
#1456=EDGE_CURVE('E633',#1449,#591,#1455,.T.);
#1457=ORIENTED_EDGE('',*,*,#1456,.T.);
#1458=EDGE_LOOP('',(#1400,#1401,#1402,#1447,#1451,#1457));
#1459=FACE_BOUND('',#1458,.T.);
#1460=ADVANCED_FACE('F616',(#1459),#1399,.F.);
#1461=CARTESIAN_POINT('',(8.16881284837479E-12,-8.79157857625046E-12,24.));
#1462=DIRECTION('',(0.,0.,-1.));
#1463=DIRECTION('',(-1.,0.,0.));
#1464=AXIS2_PLACEMENT_3D('',#1461,#1462,#1463);
#1465=CYLINDRICAL_SURFACE('',#1464,22.0000000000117);
#1466=ORIENTED_EDGE('',*,*,#599,.T.);
#1467=ORIENTED_EDGE('',*,*,#1456,.F.);
#1468=CARTESIAN_POINT('',(0.,0.,22.5736923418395));
#1469=DIRECTION('',(0.,0.,-1.));
#1470=DIRECTION('',(-1.,0.,0.));
#1471=AXIS2_PLACEMENT_3D('',#1468,#1469,#1470);
#1472=CIRCLE('',#1471,22.0000000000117);
#1473=CARTESIAN_POINT('',(-9.3339790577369,19.921767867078,22.5736923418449));
#1474=VERTEX_POINT('',#1473);
#1475=EDGE_CURVE('E718',#1449,#1474,#1472,.T.);
#1476=ORIENTED_EDGE('',*,*,#1475,.T.);
#1477=DIRECTION('',(0.,0.,-1.));
#1478=VECTOR('',#1477,1.);
#1479=CARTESIAN_POINT('',(-9.3339790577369,19.921767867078,24.));
#1480=LINE('',#1479,#1478);
#1481=EDGE_CURVE('E963',#1474,#542,#1480,.T.);
#1482=ORIENTED_EDGE('',*,*,#1481,.T.);
#1483=EDGE_LOOP('',(#1466,#1467,#1476,#1482));
#1484=FACE_BOUND('',#1483,.T.);
#1485=ADVANCED_FACE('F612',(#1484),#1465,.T.);
#1486=CARTESIAN_POINT('',(-8.41903551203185,20.3253497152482,24.));
#1487=DIRECTION('',(0.,0.,-1.));
#1488=DIRECTION('',(-1.,0.,0.));
#1489=AXIS2_PLACEMENT_3D('',#1486,#1487,#1488);
#1490=CYLINDRICAL_SURFACE('',#1489,0.999999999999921);
#1491=ORIENTED_EDGE('',*,*,#403,.T.);
#1492=ORIENTED_EDGE('',*,*,#543,.T.);
#1493=ORIENTED_EDGE('',*,*,#1481,.F.);
#1494=CARTESIAN_POINT('',(-9.3341790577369,19.9222215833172,22.5734611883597));
#1495=CARTESIAN_POINT('',(-9.30964258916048,19.8664672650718,22.6018538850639));
#1496=CARTESIAN_POINT('',(-9.27997543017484,19.8129803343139,22.6303126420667));
#1497=CARTESIAN_POINT('',(-9.21113560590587,19.7119044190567,22.686609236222));
#1498=CARTESIAN_POINT('',(-9.171938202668,19.6643312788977,22.71444524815));
#1499=CARTESIAN_POINT('',(-9.08486965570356,19.5766923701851,22.768624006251));
#1500=CARTESIAN_POINT('',(-9.03698628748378,19.5366373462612,22.7949645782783));
#1501=CARTESIAN_POINT('',(-8.93374305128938,19.4657037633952,22.8451526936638));
#1502=CARTESIAN_POINT('',(-8.87839105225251,19.4348156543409,22.8690028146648));
#1503=CARTESIAN_POINT('',(-8.76481700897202,19.3851008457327,22.9120184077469));
#1504=CARTESIAN_POINT('',(-8.7069118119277,19.3657124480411,22.931367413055));
#1505=CARTESIAN_POINT('',(-8.58738031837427,19.3377165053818,22.9660253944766));
#1506=CARTESIAN_POINT('',(-8.52575615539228,19.3291028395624,22.9813366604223));
#1507=CARTESIAN_POINT('',(-8.40740529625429,19.3238482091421,23.0057192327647));
#1508=CARTESIAN_POINT('',(-8.35082820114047,19.3260650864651,23.0152709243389));
#1509=CARTESIAN_POINT('',(-8.23831565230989,19.3401859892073,23.0299053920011));
#1510=CARTESIAN_POINT('',(-8.18237975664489,19.3520828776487,23.0349914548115));
#1511=CARTESIAN_POINT('',(-8.07802564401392,19.3838508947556,23.0401610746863));
#1512=CARTESIAN_POINT('',(-8.02938120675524,19.4029189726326,23.0406492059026));
#1513=CARTESIAN_POINT('',(-7.93576018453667,19.4483378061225,23.0376527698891));
#1514=CARTESIAN_POINT('',(-7.89078289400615,19.4746871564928,23.0341689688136));
#1515=CARTESIAN_POINT('',(-7.80689701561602,19.5329937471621,23.0235479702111));
#1516=CARTESIAN_POINT('',(-7.76785937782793,19.56478422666,23.0165098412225));
#1517=CARTESIAN_POINT('',(-7.69535702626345,19.6334088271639,22.9991487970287));
#1518=CARTESIAN_POINT('',(-7.66189311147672,19.6702436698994,22.9888254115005));
#1519=CARTESIAN_POINT('',(-7.5998448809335,19.749529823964,22.9647955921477));
#1520=CARTESIAN_POINT('',(-7.57153143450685,19.7921542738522,22.9509630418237));
#1521=CARTESIAN_POINT('',(-7.52201140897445,19.8804748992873,22.9206812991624));
#1522=CARTESIAN_POINT('',(-7.50080657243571,19.9261718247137,22.9042314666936));
#1523=CARTESIAN_POINT('',(-7.46410726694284,20.0235987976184,22.8676928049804));
#1524=CARTESIAN_POINT('',(-7.449276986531,20.075506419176,22.8474113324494));
#1525=CARTESIAN_POINT('',(-7.42816422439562,20.1803123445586,22.8049828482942));
#1526=CARTESIAN_POINT('',(-7.42188901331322,20.23321145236,22.7828342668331));
#1527=CARTESIAN_POINT('',(-7.41752793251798,20.343944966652,22.7350389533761));
#1528=CARTESIAN_POINT('',(-7.42030180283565,20.4017567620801,22.7092618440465));
#1529=CARTESIAN_POINT('',(-7.43562621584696,20.5156056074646,22.6569219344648));
#1530=CARTESIAN_POINT('',(-7.44816142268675,20.5716452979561,22.6303604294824));
#1531=CARTESIAN_POINT('',(-7.47182855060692,20.6467005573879,22.5936944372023));
#1532=CARTESIAN_POINT('',(-7.47897691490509,20.6670487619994,22.5836377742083));
#1533=CARTESIAN_POINT('',(-7.48677485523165,20.687137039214,22.5735923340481));
#1534=B_SPLINE_CURVE_WITH_KNOTS('',3,(#1494,#1495,#1496,#1497,#1498,#1499,#1500,#1501,#1502,
#1503,#1504,#1505,#1506,#1507,#1508,#1509,#1510,#1511,#1512,#1513,#1514,#1515,#1516,#1517,#1518,
#1519,#1520,#1521,#1522,#1523,#1524,#1525,#1526,#1527,#1528,#1529,#1530,#1531,#1532,#1533),
.UNSPECIFIED.,.F.,.F.,(4,2,2,2,2,2,2,2,2,2,2,2,2,2,2,2,2,2,2,4),(0.,0.201427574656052,
0.403383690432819,0.605626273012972,0.807657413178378,0.998768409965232,1.18977079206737,
1.36109333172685,1.53228967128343,1.68826466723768,1.84420958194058,1.99602979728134,
2.14787175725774,2.30622670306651,2.46462043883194,2.63691028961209,2.80934647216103,
2.998624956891,3.18760666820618,3.25895217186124),.UNSPECIFIED.);
#1535=CARTESIAN_POINT('',(-8.0363520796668,19.4014701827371,23.04));
#1536=VERTEX_POINT('',#1535);
#1537=EDGE_CURVE('E595',#1474,#1536,#1534,.T.);
#1538=ORIENTED_EDGE('',*,*,#1537,.T.);
#1539=CARTESIAN_POINT('',(-7.4866972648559,20.686937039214,22.5736923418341));
#1540=VERTEX_POINT('',#1539);
#1541=EDGE_CURVE('E596',#1536,#1540,#1534,.T.);
#1542=ORIENTED_EDGE('',*,*,#1541,.T.);
#1543=DIRECTION('',(0.,0.,-1.));
#1544=VECTOR('',#1543,1.);
#1545=CARTESIAN_POINT('',(-7.4866972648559,20.686937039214,24.));
#1546=LINE('',#1545,#1544);
#1547=EDGE_CURVE('E736',#1540,#402,#1546,.T.);
#1548=ORIENTED_EDGE('',*,*,#1547,.T.);
#1549=EDGE_LOOP('',(#1491,#1492,#1493,#1538,#1542,#1548));
#1550=FACE_BOUND('',#1549,.T.);
#1551=ADVANCED_FACE('F606',(#1550),#1490,.F.);
#1552=CARTESIAN_POINT('',(5.10355646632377E-12,-2.29365137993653E-11,24.));
#1553=DIRECTION('',(0.,0.,-1.));
#1554=DIRECTION('',(-1.,0.,0.));
#1555=AXIS2_PLACEMENT_3D('',#1552,#1553,#1554);
#1556=CYLINDRICAL_SURFACE('',#1555,22.0000000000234);
#1557=ORIENTED_EDGE('',*,*,#410,.T.);
#1558=ORIENTED_EDGE('',*,*,#1547,.F.);
#1559=CARTESIAN_POINT('',(0.,0.,22.5736923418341));
#1560=DIRECTION('',(0.,0.,-1.));
#1561=DIRECTION('',(-1.,0.,0.));
#1562=AXIS2_PLACEMENT_3D('',#1559,#1560,#1561);
#1563=CIRCLE('',#1562,22.0000000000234);
#1564=CARTESIAN_POINT('',(-0.99974170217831,21.977272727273,22.5736923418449));
#1565=VERTEX_POINT('',#1564);
#1566=EDGE_CURVE('E716',#1540,#1565,#1563,.T.);
#1567=ORIENTED_EDGE('',*,*,#1566,.T.);
#1568=DIRECTION('',(0.,0.,-1.));
#1569=VECTOR('',#1568,1.);
#1570=CARTESIAN_POINT('',(-0.99974170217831,21.977272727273,24.));
#1571=LINE('',#1570,#1569);
#1572=EDGE_CURVE('E959',#1565,#353,#1571,.T.);
#1573=ORIENTED_EDGE('',*,*,#1572,.T.);
#1574=EDGE_LOOP('',(#1557,#1558,#1567,#1573));
#1575=FACE_BOUND('',#1574,.T.);
#1576=ADVANCED_FACE('F611',(#1575),#1556,.T.);
#1577=CARTESIAN_POINT('',(0.,22.,24.));
#1578=DIRECTION('',(0.,0.,-1.));
#1579=DIRECTION('',(-1.,0.,0.));
#1580=AXIS2_PLACEMENT_3D('',#1577,#1578,#1579);
#1581=CYLINDRICAL_SURFACE('',#1580,1.);
#1582=ORIENTED_EDGE('',*,*,#214,.T.);
#1583=ORIENTED_EDGE('',*,*,#354,.T.);
#1584=ORIENTED_EDGE('',*,*,#1572,.F.);
#1585=CARTESIAN_POINT('',(-0.999746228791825,21.977472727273,22.5735990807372));
#1586=CARTESIAN_POINT('',(-0.998395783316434,21.9165753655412,22.6019909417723));
#1587=CARTESIAN_POINT('',(-0.991437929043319,21.8558106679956,22.6304482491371));
#1588=CARTESIAN_POINT('',(-0.966484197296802,21.7360950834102,22.6867407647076));
#1589=CARTESIAN_POINT('',(-0.948459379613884,21.6771493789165,22.7145741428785));
#1590=CARTESIAN_POINT('',(-0.901524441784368,21.5628770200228,22.7687464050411));
#1591=CARTESIAN_POINT('',(-0.872598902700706,21.5075556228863,22.795083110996));
#1592=CARTESIAN_POINT('',(-0.804330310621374,21.4025322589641,22.8452621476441));
#1593=CARTESIAN_POINT('',(-0.764998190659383,21.3528244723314,22.8691070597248));
#1594=CARTESIAN_POINT('',(-0.679071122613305,21.2634574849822,22.9121103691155));
#1595=CARTESIAN_POINT('',(-0.632984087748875,21.2234001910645,22.9314524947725));
#1596=CARTESIAN_POINT('',(-0.533249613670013,21.1518232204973,22.9660959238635));
#1597=CARTESIAN_POINT('',(-0.479606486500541,21.1202987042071,22.9813995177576));
#1598=CARTESIAN_POINT('',(-0.37226793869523,21.0701845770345,23.0057669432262));
#1599=CARTESIAN_POINT('',(-0.31914752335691,21.0505968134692,23.0153112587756));
#1600=CARTESIAN_POINT('',(-0.209795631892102,21.0206162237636,23.0299311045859));
#1601=CARTESIAN_POINT('',(-0.153566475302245,21.0102166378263,23.0350099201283));
#1602=CARTESIAN_POINT('',(-0.0450029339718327,20.9996589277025,23.0401663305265));
#1603=CARTESIAN_POINT('',(0.00723343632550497,20.9986727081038,23.0406483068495));
#1604=CARTESIAN_POINT('',(0.111102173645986,21.0048311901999,23.0376400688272));
#1605=CARTESIAN_POINT('',(0.162734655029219,21.0119743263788,23.0341506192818));
#1606=CARTESIAN_POINT('',(0.262539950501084,21.0337628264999,23.0235189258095));
#1607=CARTESIAN_POINT('',(0.310768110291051,21.0482051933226,23.0164755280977));
#1608=CARTESIAN_POINT('',(0.404004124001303,21.083881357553,22.9991044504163));
#1609=CARTESIAN_POINT('',(0.449011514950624,21.1051161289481,22.9887762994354));
#1610=CARTESIAN_POINT('',(0.536667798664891,21.1546422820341,22.9647368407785));
#1611=CARTESIAN_POINT('',(0.579132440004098,21.1831975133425,22.9508993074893));
#1612=CARTESIAN_POINT('',(0.658669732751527,21.2458646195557,22.9206081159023));
#1613=CARTESIAN_POINT('',(0.695741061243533,21.2799778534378,22.9041538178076));
#1614=CARTESIAN_POINT('',(0.766915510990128,21.3559639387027,22.8676060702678));
#1615=CARTESIAN_POINT('',(0.800472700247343,21.3982550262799,22.8473199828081));
#1616=CARTESIAN_POINT('',(0.860067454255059,21.4870224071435,22.8048828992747));
#1617=CARTESIAN_POINT('',(0.886098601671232,21.533502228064,22.7827303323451));
#1618=CARTESIAN_POINT('',(0.932480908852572,21.6341545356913,22.7349275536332));
#1619=CARTESIAN_POINT('',(0.952029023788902,21.6886349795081,22.7091470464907));
#1620=CARTESIAN_POINT('',(0.981412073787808,21.799695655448,22.6568013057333));
#1621=CARTESIAN_POINT('',(0.991262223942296,21.8562724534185,22.6302373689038));
#1622=CARTESIAN_POINT('',(0.998090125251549,21.9345827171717,22.5936133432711));
#1623=CARTESIAN_POINT('',(0.999264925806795,21.9560235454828,22.5836006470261));
#1624=CARTESIAN_POINT('',(0.999746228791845,21.977472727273,22.5735990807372));
#1625=B_SPLINE_CURVE_WITH_KNOTS('',3,(#1585,#1586,#1587,#1588,#1589,#1590,#1591,#1592,#1593,
#1594,#1595,#1596,#1597,#1598,#1599,#1600,#1601,#1602,#1603,#1604,#1605,#1606,#1607,#1608,#1609,
#1610,#1611,#1612,#1613,#1614,#1615,#1616,#1617,#1618,#1619,#1620,#1621,#1622,#1623,#1624),
.UNSPECIFIED.,.F.,.F.,(4,2,2,2,2,2,2,2,2,2,2,2,2,2,2,2,2,2,2,4),(0.,0.201420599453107,
0.403370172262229,0.605606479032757,0.807631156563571,0.998728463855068,1.18971715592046,
1.36102508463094,1.53220687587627,1.6881742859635,1.84411166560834,1.99593309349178,
2.14777630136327,2.30613943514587,2.4645413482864,2.63684336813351,2.80929187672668,
2.99858276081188,3.18757619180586,3.25861009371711),.UNSPECIFIED.);
#1626=CARTESIAN_POINT('',(0.,21.,23.04));
#1627=VERTEX_POINT('',#1626);
#1628=EDGE_CURVE('E975',#1565,#1627,#1625,.T.);
#1629=ORIENTED_EDGE('',*,*,#1628,.T.);
#1630=CARTESIAN_POINT('',(0.999741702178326,21.977272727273,22.5736923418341));
#1631=VERTEX_POINT('',#1630);
#1632=EDGE_CURVE('E977',#1627,#1631,#1625,.T.);
#1633=ORIENTED_EDGE('',*,*,#1632,.T.);
#1634=DIRECTION('',(0.,0.,-1.));
#1635=VECTOR('',#1634,1.);
#1636=CARTESIAN_POINT('',(0.999741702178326,21.977272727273,24.));
#1637=LINE('',#1636,#1635);
#1638=EDGE_CURVE('E956',#1631,#213,#1637,.T.);
#1639=ORIENTED_EDGE('',*,*,#1638,.T.);
#1640=EDGE_LOOP('',(#1582,#1583,#1584,#1629,#1633,#1639));
#1641=FACE_BOUND('',#1640,.T.);
#1642=ADVANCED_FACE('F985',(#1641),#1581,.F.);
#1643=CARTESIAN_POINT('',(-5.11353112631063E-12,-2.29712082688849E-11,24.));
#1644=DIRECTION('',(0.,0.,-1.));
#1645=DIRECTION('',(-1.,0.,0.));
#1646=AXIS2_PLACEMENT_3D('',#1643,#1644,#1645);
#1647=CYLINDRICAL_SURFACE('',#1646,22.0000000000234);
#1648=ORIENTED_EDGE('',*,*,#221,.T.);
#1649=ORIENTED_EDGE('',*,*,#1638,.F.);
#1650=CARTESIAN_POINT('',(0.,0.,22.5736923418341));
#1651=DIRECTION('',(0.,0.,-1.));
#1652=DIRECTION('',(-1.,0.,0.));
#1653=AXIS2_PLACEMENT_3D('',#1650,#1651,#1652);
#1654=CIRCLE('',#1653,22.0000000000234);
#1655=CARTESIAN_POINT('',(7.4866972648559,20.686937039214,22.5736923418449));
#1656=VERTEX_POINT('',#1655);
#1657=EDGE_CURVE('E714',#1631,#1656,#1654,.T.);
#1658=ORIENTED_EDGE('',*,*,#1657,.T.);
#1659=DIRECTION('',(0.,0.,-1.));
#1660=VECTOR('',#1659,1.);
#1661=CARTESIAN_POINT('',(7.4866972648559,20.686937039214,24.));
#1662=LINE('',#1661,#1660);
#1663=EDGE_CURVE('E953',#1656,#164,#1662,.T.);
#1664=ORIENTED_EDGE('',*,*,#1663,.T.);
#1665=EDGE_LOOP('',(#1648,#1649,#1658,#1664));
#1666=FACE_BOUND('',#1665,.T.);
#1667=ADVANCED_FACE('F989',(#1666),#1647,.T.);
#1668=CARTESIAN_POINT('',(8.41903551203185,20.3253497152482,24.));
#1669=DIRECTION('',(0.,0.,-1.));
#1670=DIRECTION('',(-1.,0.,0.));
#1671=AXIS2_PLACEMENT_3D('',#1668,#1669,#1670);
#1672=CYLINDRICAL_SURFACE('',#1671,0.999999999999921);
#1673=ORIENTED_EDGE('',*,*,#158,.T.);
#1674=ORIENTED_EDGE('',*,*,#165,.T.);
#1675=ORIENTED_EDGE('',*,*,#1663,.F.);
#1676=CARTESIAN_POINT('',(7.48677485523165,20.687137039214,22.5735923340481));
#1677=CARTESIAN_POINT('',(7.46471723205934,20.6303586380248,22.6019842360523));
#1678=CARTESIAN_POINT('',(7.4478909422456,20.5715568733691,22.6304416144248));
#1679=CARTESIAN_POINT('',(7.42513027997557,20.4514048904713,22.6867343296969));
#1680=CARTESIAN_POINT('',(7.4192246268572,20.3900483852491,22.7145678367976));
#1681=CARTESIAN_POINT('',(7.41885498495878,20.2665131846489,22.7687404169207));
#1682=CARTESIAN_POINT('',(7.42440725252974,20.2043334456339,22.7950773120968));
#1683=CARTESIAN_POINT('',(7.44728679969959,20.0811788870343,22.8452567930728));
#1684=CARTESIAN_POINT('',(7.46460175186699,20.0202028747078,22.8691019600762));
#1685=CARTESIAN_POINT('',(7.50978719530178,19.9047549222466,22.9121058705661));
#1686=CARTESIAN_POINT('',(7.53703611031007,19.8501095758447,22.9314483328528));
#1687=CARTESIAN_POINT('',(7.60178616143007,19.7458132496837,22.9660924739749));
#1688=CARTESIAN_POINT('',(7.63928146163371,19.696159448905,22.9813964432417));
#1689=CARTESIAN_POINT('',(7.71927057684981,19.608782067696,23.0057646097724));
#1690=CARTESIAN_POINT('',(7.76085116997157,19.5703563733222,23.0153092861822));
#1691=CARTESIAN_POINT('',(7.85040550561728,19.500809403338,23.0299298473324));
#1692=CARTESIAN_POINT('',(7.89837451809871,19.4696827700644,23.0350090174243));
#1693=CARTESIAN_POINT('',(7.99463357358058,19.4183819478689,23.0401660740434));
#1694=CARTESIAN_POINT('',(8.04251614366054,19.3974801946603,23.0406483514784));
#1695=CARTESIAN_POINT('',(8.1408349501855,19.3634198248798,23.0376406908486));
#1696=CARTESIAN_POINT('',(8.19127069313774,19.3502597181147,23.0341515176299));
#1697=CARTESIAN_POINT('',(8.29181681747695,19.3321946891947,23.0235203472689));
#1698=CARTESIAN_POINT('',(8.3419006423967,19.3270810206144,23.0164772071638));
#1699=CARTESIAN_POINT('',(8.44169217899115,19.3243605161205,22.9991066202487));
#1700=CARTESIAN_POINT('',(8.49139983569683,19.326754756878,22.9887787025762));
#1701=CARTESIAN_POINT('',(8.59133660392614,19.338965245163,22.9647397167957));
#1702=CARTESIAN_POINT('',(8.64149646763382,19.3490957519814,22.9509024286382));
#1703=CARTESIAN_POINT('',(8.73896118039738,19.3765538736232,22.9206116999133));
#1704=CARTESIAN_POINT('',(8.78626532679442,19.3938832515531,22.9041576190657));
#1705=CARTESIAN_POINT('',(8.88110089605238,19.4368468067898,22.8676103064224));
#1706=CARTESIAN_POINT('',(8.92828800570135,19.4630763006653,22.8473244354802));
#1707=CARTESIAN_POINT('',(9.01731665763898,19.5222795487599,22.8048877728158));
#1708=CARTESIAN_POINT('',(9.0591536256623,19.5552590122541,22.7827354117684));
#1709=CARTESIAN_POINT('',(9.14052389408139,19.6304986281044,22.7349330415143));
#1710=CARTESIAN_POINT('',(9.17943314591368,19.673350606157,22.7091527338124));
#1711=CARTESIAN_POINT('',(9.2490815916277,19.7647116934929,22.6568073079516));
#1712=CARTESIAN_POINT('',(9.2798335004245,19.8132118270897,22.6302434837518));
#1713=CARTESIAN_POINT('',(9.31615818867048,19.8830391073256,22.5935714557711));
#1714=CARTESIAN_POINT('',(9.32549047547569,19.9024925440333,22.5835106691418));
#1715=CARTESIAN_POINT('',(9.33417905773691,19.9222215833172,22.5734611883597));
#1716=B_SPLINE_CURVE_WITH_KNOTS('',3,(#1676,#1677,#1678,#1679,#1680,#1681,#1682,#1683,#1684,
#1685,#1686,#1687,#1688,#1689,#1690,#1691,#1692,#1693,#1694,#1695,#1696,#1697,#1698,#1699,#1700,
#1701,#1702,#1703,#1704,#1705,#1706,#1707,#1708,#1709,#1710,#1711,#1712,#1713,#1714,#1715),
.UNSPECIFIED.,.F.,.F.,(4,2,2,2,2,2,2,2,2,2,2,2,2,2,2,2,2,2,2,4),(0.,0.201420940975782,
0.403370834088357,0.605607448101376,0.807632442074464,0.99873041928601,1.18971978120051,
1.36102842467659,1.53221092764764,1.68817870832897,1.84411645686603,1.9959378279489,
2.14778097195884,2.30614369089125,2.46454521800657,2.63684671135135,2.80929454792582,
2.99858451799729,3.18757768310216,3.25895226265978),.UNSPECIFIED.);
#1717=CARTESIAN_POINT('',(8.0363520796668,19.4014701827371,23.04));
#1718=VERTEX_POINT('',#1717);
#1719=EDGE_CURVE('E1005',#1656,#1718,#1716,.T.);
#1720=ORIENTED_EDGE('',*,*,#1719,.T.);
#1721=CARTESIAN_POINT('',(9.3339790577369,19.921767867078,22.5736923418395));
#1722=VERTEX_POINT('',#1721);
#1723=EDGE_CURVE('E1000',#1718,#1722,#1716,.T.);
#1724=ORIENTED_EDGE('',*,*,#1723,.T.);
#1725=DIRECTION('',(0.,0.,-1.));
#1726=VECTOR('',#1725,1.);
#1727=CARTESIAN_POINT('',(9.3339790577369,19.921767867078,24.));
#1728=LINE('',#1727,#1726);
#1729=EDGE_CURVE('E950',#1722,#60,#1728,.T.);
#1730=ORIENTED_EDGE('',*,*,#1729,.T.);
#1731=EDGE_LOOP('',(#1673,#1674,#1675,#1720,#1724,#1730));
#1732=FACE_BOUND('',#1731,.T.);
#1733=ADVANCED_FACE('F992',(#1732),#1672,.F.);
#1734=CARTESIAN_POINT('',(-8.16881284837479E-12,-8.79504802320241E-12,24.));
#1735=DIRECTION('',(0.,0.,-1.));
#1736=DIRECTION('',(-1.,0.,0.));
#1737=AXIS2_PLACEMENT_3D('',#1734,#1735,#1736);
#1738=CYLINDRICAL_SURFACE('',#1737,22.0000000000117);
#1739=ORIENTED_EDGE('',*,*,#61,.T.);
#1740=ORIENTED_EDGE('',*,*,#1729,.F.);
#1741=CARTESIAN_POINT('',(0.,0.,22.5736923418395));
#1742=DIRECTION('',(0.,0.,-1.));
#1743=DIRECTION('',(-1.,0.,0.));
#1744=AXIS2_PLACEMENT_3D('',#1741,#1742,#1743);
#1745=CIRCLE('',#1744,22.0000000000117);
#1746=CARTESIAN_POINT('',(14.833354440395,16.247202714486,22.5736923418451));
#1747=VERTEX_POINT('',#1746);
#1748=EDGE_CURVE('E712',#1722,#1747,#1745,.T.);
#1749=ORIENTED_EDGE('',*,*,#1748,.T.);
#1750=DIRECTION('',(0.,0.,-1.));
#1751=VECTOR('',#1750,1.);
#1752=CARTESIAN_POINT('',(14.833354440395,16.247202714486,24.));
#1753=LINE('',#1752,#1751);
#1754=EDGE_CURVE('E947',#1747,#58,#1753,.T.);
#1755=ORIENTED_EDGE('',*,*,#1754,.T.);
#1756=EDGE_LOOP('',(#1739,#1740,#1749,#1755));
#1757=FACE_BOUND('',#1756,.T.);
#1758=ADVANCED_FACE('F997',(#1757),#1738,.T.);
#1759=CARTESIAN_POINT('',(15.5563491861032,15.5563491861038,24.));
#1760=DIRECTION('',(0.,0.,-1.));
#1761=DIRECTION('',(-1.,0.,0.));
#1762=AXIS2_PLACEMENT_3D('',#1759,#1760,#1761);
#1763=CYLINDRICAL_SURFACE('',#1762,0.999999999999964);
#1764=ORIENTED_EDGE('',*,*,#228,.T.);
#1765=ORIENTED_EDGE('',*,*,#106,.T.);
#1766=ORIENTED_EDGE('',*,*,#1754,.F.);
#1767=CARTESIAN_POINT('',(14.8335456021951,16.247402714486,22.5735633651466));
#1768=CARTESIAN_POINT('',(14.7914358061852,16.2033896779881,22.6019554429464));
#1769=CARTESIAN_POINT('',(14.7533846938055,16.1555050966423,22.6304131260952));
#1770=CARTESIAN_POINT('',(14.686369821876,16.0532128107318,22.6867066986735));
#1771=CARTESIAN_POINT('',(14.6574301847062,15.9987883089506,22.7145407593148));
#1772=CARTESIAN_POINT('',(14.6098067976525,15.8848006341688,22.7687147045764));
#1773=CARTESIAN_POINT('',(14.5911376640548,15.8252302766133,22.7950524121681));
#1774=CARTESIAN_POINT('',(14.565139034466,15.702696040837,22.8452338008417));
#1775=CARTESIAN_POINT('',(14.5577976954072,15.6397357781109,22.8690800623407));
#1776=CARTESIAN_POINT('',(14.5553561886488,15.5157836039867,22.912086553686));
#1777=CARTESIAN_POINT('',(14.5596154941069,15.4548693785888,22.9314304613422));
#1778=CARTESIAN_POINT('',(14.5795174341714,15.3337310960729,22.9660776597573));
#1779=CARTESIAN_POINT('',(14.5951535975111,15.2735066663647,22.9813832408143));
#1780=CARTESIAN_POINT('',(14.6356102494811,15.1621664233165,23.0057545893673));
#1781=CARTESIAN_POINT('',(14.6593183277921,15.1107514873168,23.0153008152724));
#1782=CARTESIAN_POINT('',(14.7154368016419,15.0122230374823,23.0299244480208));
#1783=CARTESIAN_POINT('',(14.747840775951,14.965106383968,23.0350051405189));
#1784=CARTESIAN_POINT('',(14.8171371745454,14.8808692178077,23.0401649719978));
#1785=CARTESIAN_POINT('',(14.853374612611,14.8432324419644,23.0406485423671));
#1786=CARTESIAN_POINT('',(14.9311724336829,14.7741351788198,23.0376433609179));
#1787=CARTESIAN_POINT('',(14.9727317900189,14.7426735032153,23.0341553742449));
#1788=CARTESIAN_POINT('',(15.0587090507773,14.6875017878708,23.0235264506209));
#1789=CARTESIAN_POINT('',(15.1030224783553,14.6636089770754,23.0164844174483));
#1790=CARTESIAN_POINT('',(15.1941749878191,14.6229025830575,22.9991159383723));
#1791=CARTESIAN_POINT('',(15.2410144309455,14.6060900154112,22.9887890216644));
#1792=CARTESIAN_POINT('',(15.3380152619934,14.5791223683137,22.9647520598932));
#1793=CARTESIAN_POINT('',(15.3882329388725,14.5692840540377,22.9509158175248));
#1794=CARTESIAN_POINT('',(15.4887851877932,14.5573491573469,22.9206270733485));
#1795=CARTESIAN_POINT('',(15.5391197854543,14.5552544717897,22.9041739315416));
#1796=CARTESIAN_POINT('',(15.6431771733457,14.5586504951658,22.867628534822));
#1797=CARTESIAN_POINT('',(15.696809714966,14.5648229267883,22.8473436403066));
#1798=CARTESIAN_POINT('',(15.8017175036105,14.5854442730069,22.8049087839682));
#1799=CARTESIAN_POINT('',(15.8529907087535,14.5999002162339,22.782757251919));
#1800=CARTESIAN_POINT('',(15.9569609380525,14.6382676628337,22.7349564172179));
#1801=CARTESIAN_POINT('',(16.0093079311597,14.6629647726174,22.7091767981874));
#1802=CARTESIAN_POINT('',(16.1086190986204,14.7207120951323,22.6568325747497));
#1803=CARTESIAN_POINT('',(16.1555915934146,14.7537491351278,22.6302692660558));
#1804=CARTESIAN_POINT('',(16.2158335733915,14.8043214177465,22.5936230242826));
#1805=CARTESIAN_POINT('',(16.2318614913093,14.8186842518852,22.5835875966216));
#1806=CARTESIAN_POINT('',(16.247402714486,14.8335456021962,22.5735633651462));
#1807=B_SPLINE_CURVE_WITH_KNOTS('',3,(#1767,#1768,#1769,#1770,#1771,#1772,#1773,#1774,#1775,
#1776,#1777,#1778,#1779,#1780,#1781,#1782,#1783,#1784,#1785,#1786,#1787,#1788,#1789,#1790,#1791,
#1792,#1793,#1794,#1795,#1796,#1797,#1798,#1799,#1800,#1801,#1802,#1803,#1804,#1805,#1806),
.UNSPECIFIED.,.F.,.F.,(4,2,2,2,2,2,2,2,2,2,2,2,2,2,2,2,2,2,2,4),(0.,0.201422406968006,
0.403373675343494,0.605611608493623,0.807637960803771,0.998738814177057,1.18973105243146,
1.36104276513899,1.53222832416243,1.68819769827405,1.84413702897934,1.99595814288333,
2.14780102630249,2.30616203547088,2.46456183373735,2.63686071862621,2.80930601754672,
2.99859361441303,3.18758408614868,3.25877905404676),.UNSPECIFIED.);
#1808=CARTESIAN_POINT('',(14.8492424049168,14.8492424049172,23.04));
#1809=VERTEX_POINT('',#1808);
#1810=EDGE_CURVE('E1012',#1747,#1809,#1807,.T.);
#1811=ORIENTED_EDGE('',*,*,#1810,.T.);
#1812=CARTESIAN_POINT('',(16.247202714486,14.833354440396,22.5736923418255));
#1813=VERTEX_POINT('',#1812);
#1814=EDGE_CURVE('E1014',#1809,#1813,#1807,.T.);
#1815=ORIENTED_EDGE('',*,*,#1814,.T.);
#1816=DIRECTION('',(0.,0.,-1.));
#1817=VECTOR('',#1816,1.);
#1818=CARTESIAN_POINT('',(16.247202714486,14.833354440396,24.));
#1819=LINE('',#1818,#1817);
#1820=EDGE_CURVE('E944',#1813,#227,#1819,.T.);
#1821=ORIENTED_EDGE('',*,*,#1820,.T.);
#1822=EDGE_LOOP('',(#1764,#1765,#1766,#1811,#1815,#1821));
#1823=FACE_BOUND('',#1822,.T.);
#1824=ADVANCED_FACE('F1022',(#1823),#1763,.F.);
#1825=CARTESIAN_POINT('',(-3.49460044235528E-11,-2.29469221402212E-11,24.));
#1826=DIRECTION('',(0.,0.,-1.));
#1827=DIRECTION('',(-1.,0.,0.));
#1828=AXIS2_PLACEMENT_3D('',#1825,#1826,#1827);
#1829=CYLINDRICAL_SURFACE('',#1828,22.0000000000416);
#1830=ORIENTED_EDGE('',*,*,#237,.T.);
#1831=ORIENTED_EDGE('',*,*,#1820,.F.);
#1832=CARTESIAN_POINT('',(0.,0.,22.5736923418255));
#1833=DIRECTION('',(0.,0.,-1.));
#1834=DIRECTION('',(-1.,0.,0.));
#1835=AXIS2_PLACEMENT_3D('',#1832,#1833,#1834);
#1836=CIRCLE('',#1835,22.0000000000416);
#1837=CARTESIAN_POINT('',(19.921767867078,9.3339790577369,22.5736923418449));
#1838=VERTEX_POINT('',#1837);
#1839=EDGE_CURVE('E710',#1813,#1838,#1836,.T.);
#1840=ORIENTED_EDGE('',*,*,#1839,.T.);
#1841=DIRECTION('',(0.,0.,-1.));
#1842=VECTOR('',#1841,1.);
#1843=CARTESIAN_POINT('',(19.921767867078,9.3339790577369,24.));
#1844=LINE('',#1843,#1842);
#1845=EDGE_CURVE('E941',#1838,#236,#1844,.T.);
#1846=ORIENTED_EDGE('',*,*,#1845,.T.);
#1847=EDGE_LOOP('',(#1830,#1831,#1840,#1846));
#1848=FACE_BOUND('',#1847,.T.);
#1849=ADVANCED_FACE('F1026',(#1848),#1829,.T.);
#1850=CARTESIAN_POINT('',(20.3253497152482,8.41903551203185,24.));
#1851=DIRECTION('',(0.,0.,-1.));
#1852=DIRECTION('',(-1.,0.,0.));
#1853=AXIS2_PLACEMENT_3D('',#1850,#1851,#1852);
#1854=CYLINDRICAL_SURFACE('',#1853,0.99999999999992);
#1855=ORIENTED_EDGE('',*,*,#291,.T.);
#1856=ORIENTED_EDGE('',*,*,#282,.T.);
#1857=ORIENTED_EDGE('',*,*,#1845,.F.);
#1858=CARTESIAN_POINT('',(19.9222215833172,9.3341790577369,22.5734611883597));
#1859=CARTESIAN_POINT('',(19.8664672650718,9.30964258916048,22.6018538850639));
#1860=CARTESIAN_POINT('',(19.8129803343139,9.27997543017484,22.6303126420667));
#1861=CARTESIAN_POINT('',(19.7119044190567,9.21113560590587,22.686609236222));
#1862=CARTESIAN_POINT('',(19.6643312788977,9.171938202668,22.71444524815));
#1863=CARTESIAN_POINT('',(19.5766923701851,9.08486965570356,22.768624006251));
#1864=CARTESIAN_POINT('',(19.5366373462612,9.03698628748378,22.7949645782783));
#1865=CARTESIAN_POINT('',(19.4657037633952,8.93374305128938,22.8451526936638));
#1866=CARTESIAN_POINT('',(19.4348156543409,8.87839105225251,22.8690028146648));
#1867=CARTESIAN_POINT('',(19.3851008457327,8.76481700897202,22.9120184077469));
#1868=CARTESIAN_POINT('',(19.3657124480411,8.7069118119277,22.931367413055));
#1869=CARTESIAN_POINT('',(19.3377165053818,8.58738031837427,22.9660253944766));
#1870=CARTESIAN_POINT('',(19.3291028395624,8.52575615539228,22.9813366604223));
#1871=CARTESIAN_POINT('',(19.3238482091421,8.40740529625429,23.0057192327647));
#1872=CARTESIAN_POINT('',(19.3260650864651,8.35082820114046,23.0152709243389));
#1873=CARTESIAN_POINT('',(19.3401859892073,8.23831565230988,23.0299053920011));
#1874=CARTESIAN_POINT('',(19.3520828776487,8.18237975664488,23.0349914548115));
#1875=CARTESIAN_POINT('',(19.3838508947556,8.07802564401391,23.0401610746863));
#1876=CARTESIAN_POINT('',(19.4029189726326,8.02938120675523,23.0406492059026));
#1877=CARTESIAN_POINT('',(19.4483378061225,7.93576018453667,23.0376527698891));
#1878=CARTESIAN_POINT('',(19.4746871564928,7.89078289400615,23.0341689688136));
#1879=CARTESIAN_POINT('',(19.5329937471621,7.80689701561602,23.0235479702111));
#1880=CARTESIAN_POINT('',(19.56478422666,7.76785937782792,23.0165098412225));
#1881=CARTESIAN_POINT('',(19.6334088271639,7.69535702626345,22.9991487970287));
#1882=CARTESIAN_POINT('',(19.6702436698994,7.66189311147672,22.9888254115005));
#1883=CARTESIAN_POINT('',(19.749529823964,7.5998448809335,22.9647955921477));
#1884=CARTESIAN_POINT('',(19.7921542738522,7.57153143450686,22.9509630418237));
#1885=CARTESIAN_POINT('',(19.8804748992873,7.52201140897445,22.9206812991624));
#1886=CARTESIAN_POINT('',(19.9261718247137,7.5008065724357,22.9042314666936));
#1887=CARTESIAN_POINT('',(20.0235987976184,7.46410726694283,22.8676928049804));
#1888=CARTESIAN_POINT('',(20.075506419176,7.44927698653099,22.8474113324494));
#1889=CARTESIAN_POINT('',(20.1803123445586,7.42816422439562,22.8049828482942));
#1890=CARTESIAN_POINT('',(20.23321145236,7.42188901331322,22.7828342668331));
#1891=CARTESIAN_POINT('',(20.343944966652,7.41752793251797,22.7350389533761));
#1892=CARTESIAN_POINT('',(20.4017567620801,7.42030180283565,22.7092618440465));
#1893=CARTESIAN_POINT('',(20.5156056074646,7.43562621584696,22.6569219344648));
#1894=CARTESIAN_POINT('',(20.5716452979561,7.44816142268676,22.6303604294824));
#1895=CARTESIAN_POINT('',(20.6467005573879,7.47182855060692,22.5936944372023));
#1896=CARTESIAN_POINT('',(20.6670487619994,7.47897691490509,22.5836377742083));
#1897=CARTESIAN_POINT('',(20.687137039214,7.48677485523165,22.5735923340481));
#1898=B_SPLINE_CURVE_WITH_KNOTS('',3,(#1858,#1859,#1860,#1861,#1862,#1863,#1864,#1865,#1866,
#1867,#1868,#1869,#1870,#1871,#1872,#1873,#1874,#1875,#1876,#1877,#1878,#1879,#1880,#1881,#1882,
#1883,#1884,#1885,#1886,#1887,#1888,#1889,#1890,#1891,#1892,#1893,#1894,#1895,#1896,#1897),
.UNSPECIFIED.,.F.,.F.,(4,2,2,2,2,2,2,2,2,2,2,2,2,2,2,2,2,2,2,4),(0.,0.201427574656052,
0.403383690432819,0.605626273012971,0.807657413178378,0.998768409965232,1.18977079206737,
1.36109333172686,1.53228967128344,1.68826466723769,1.84420958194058,1.99602979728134,
2.14787175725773,2.30622670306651,2.46462043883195,2.63691028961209,2.80934647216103,
2.998624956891,3.18760666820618,3.25895217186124),.UNSPECIFIED.);
#1899=CARTESIAN_POINT('',(19.4014701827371,8.0363520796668,23.04));
#1900=VERTEX_POINT('',#1899);
#1901=EDGE_CURVE('E1042',#1838,#1900,#1898,.T.);
#1902=ORIENTED_EDGE('',*,*,#1901,.T.);
#1903=CARTESIAN_POINT('',(20.686937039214,7.4866972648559,22.5736923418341));
#1904=VERTEX_POINT('',#1903);
#1905=EDGE_CURVE('E1037',#1900,#1904,#1898,.T.);
#1906=ORIENTED_EDGE('',*,*,#1905,.T.);
#1907=DIRECTION('',(0.,0.,-1.));
#1908=VECTOR('',#1907,1.);
#1909=CARTESIAN_POINT('',(20.686937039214,7.4866972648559,24.));
#1910=LINE('',#1909,#1908);
#1911=EDGE_CURVE('E938',#1904,#290,#1910,.T.);
#1912=ORIENTED_EDGE('',*,*,#1911,.T.);
#1913=EDGE_LOOP('',(#1855,#1856,#1857,#1902,#1906,#1912));
#1914=FACE_BOUND('',#1913,.T.);
#1915=ADVANCED_FACE('F1029',(#1914),#1854,.F.);
#1916=CARTESIAN_POINT('',(-2.27855928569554E-11,-5.06279046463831E-12,24.));
#1917=DIRECTION('',(0.,0.,-1.));
#1918=DIRECTION('',(-1.,0.,0.));
#1919=AXIS2_PLACEMENT_3D('',#1916,#1917,#1918);
#1920=CYLINDRICAL_SURFACE('',#1919,22.0000000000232);
#1921=ORIENTED_EDGE('',*,*,#300,.T.);
#1922=ORIENTED_EDGE('',*,*,#1911,.F.);
#1923=CARTESIAN_POINT('',(0.,0.,22.5736923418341));
#1924=DIRECTION('',(0.,0.,-1.));
#1925=DIRECTION('',(-1.,0.,0.));
#1926=AXIS2_PLACEMENT_3D('',#1923,#1924,#1925);
#1927=CIRCLE('',#1926,22.0000000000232);
#1928=CARTESIAN_POINT('',(21.977272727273,0.99974170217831,22.5736923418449));
#1929=VERTEX_POINT('',#1928);
#1930=EDGE_CURVE('E708',#1904,#1929,#1927,.T.);
#1931=ORIENTED_EDGE('',*,*,#1930,.T.);
#1932=DIRECTION('',(0.,0.,-1.));
#1933=VECTOR('',#1932,1.);
#1934=CARTESIAN_POINT('',(21.977272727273,0.99974170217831,24.));
#1935=LINE('',#1934,#1933);
#1936=EDGE_CURVE('E935',#1929,#299,#1935,.T.);
#1937=ORIENTED_EDGE('',*,*,#1936,.T.);
#1938=EDGE_LOOP('',(#1921,#1922,#1931,#1937));
#1939=FACE_BOUND('',#1938,.T.);
#1940=ADVANCED_FACE('F1034',(#1939),#1920,.T.);
#1941=CARTESIAN_POINT('',(22.,0.,24.));
#1942=DIRECTION('',(0.,0.,-1.));
#1943=DIRECTION('',(-1.,0.,0.));
#1944=AXIS2_PLACEMENT_3D('',#1941,#1942,#1943);
#1945=CYLINDRICAL_SURFACE('',#1944,0.99999999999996);
#1946=ORIENTED_EDGE('',*,*,#417,.T.);
#1947=ORIENTED_EDGE('',*,*,#345,.T.);
#1948=ORIENTED_EDGE('',*,*,#1936,.F.);
#1949=CARTESIAN_POINT('',(21.977472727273,0.999746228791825,22.5735990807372));
#1950=CARTESIAN_POINT('',(21.9165753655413,0.99839578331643,22.6019909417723));
#1951=CARTESIAN_POINT('',(21.8558106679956,0.99143792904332,22.6304482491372));
#1952=CARTESIAN_POINT('',(21.7360950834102,0.966484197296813,22.6867407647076));
#1953=CARTESIAN_POINT('',(21.6771493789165,0.948459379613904,22.7145741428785));
#1954=CARTESIAN_POINT('',(21.5628770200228,0.901524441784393,22.768746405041));
#1955=CARTESIAN_POINT('',(21.5075556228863,0.87259890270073,22.795083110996));
#1956=CARTESIAN_POINT('',(21.4025322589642,0.804330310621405,22.8452621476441));
#1957=CARTESIAN_POINT('',(21.3528244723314,0.764998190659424,22.8691070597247));
#1958=CARTESIAN_POINT('',(21.2634574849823,0.679071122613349,22.9121103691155));
#1959=CARTESIAN_POINT('',(21.2234001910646,0.632984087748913,22.9314524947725));
#1960=CARTESIAN_POINT('',(21.1518232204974,0.533249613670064,22.9660959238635));
#1961=CARTESIAN_POINT('',(21.1202987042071,0.479606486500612,22.9813995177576));
#1962=CARTESIAN_POINT('',(21.0701845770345,0.372267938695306,23.0057669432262));
#1963=CARTESIAN_POINT('',(21.0505968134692,0.319147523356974,23.0153112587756));
#1964=CARTESIAN_POINT('',(21.0206162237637,0.209795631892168,23.0299311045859));
#1965=CARTESIAN_POINT('',(21.0102166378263,0.153566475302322,23.0350099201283));
#1966=CARTESIAN_POINT('',(20.9996589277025,0.045002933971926,23.0401663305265));
#1967=CARTESIAN_POINT('',(20.9986727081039,-0.00723343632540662,23.0406483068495));
#1968=CARTESIAN_POINT('',(21.0048311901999,-0.111102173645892,23.0376400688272));
#1969=CARTESIAN_POINT('',(21.0119743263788,-0.162734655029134,23.0341506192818));
#1970=CARTESIAN_POINT('',(21.0337628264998,-0.262539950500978,23.0235189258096));
#1971=CARTESIAN_POINT('',(21.0482051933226,-0.310768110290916,23.0164755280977));
#1972=CARTESIAN_POINT('',(21.083881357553,-0.404004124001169,22.9991044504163));
#1973=CARTESIAN_POINT('',(21.105116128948,-0.449011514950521,22.9887762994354));
#1974=CARTESIAN_POINT('',(21.1546422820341,-0.536667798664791,22.9647368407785));
#1975=CARTESIAN_POINT('',(21.1831975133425,-0.579132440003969,22.9508993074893));
#1976=CARTESIAN_POINT('',(21.2458646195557,-0.658669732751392,22.9206081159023));
#1977=CARTESIAN_POINT('',(21.2799778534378,-0.695741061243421,22.9041538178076));
#1978=CARTESIAN_POINT('',(21.3559639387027,-0.766915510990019,22.8676060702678));
#1979=CARTESIAN_POINT('',(21.3982550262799,-0.800472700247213,22.8473199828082));
#1980=CARTESIAN_POINT('',(21.4870224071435,-0.860067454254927,22.8048828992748));
#1981=CARTESIAN_POINT('',(21.533502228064,-0.886098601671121,22.7827303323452));
#1982=CARTESIAN_POINT('',(21.6341545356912,-0.932480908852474,22.7349275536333));
#1983=CARTESIAN_POINT('',(21.688634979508,-0.95202902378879,22.7091470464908));
#1984=CARTESIAN_POINT('',(21.7996956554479,-0.981412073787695,22.6568013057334));
#1985=CARTESIAN_POINT('',(21.8562724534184,-0.991262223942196,22.6302373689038));
#1986=CARTESIAN_POINT('',(21.9345827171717,-0.998090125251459,22.5936133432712));
#1987=CARTESIAN_POINT('',(21.9560235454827,-0.999264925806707,22.5836006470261));
#1988=CARTESIAN_POINT('',(21.977472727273,-0.999746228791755,22.5735990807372));
#1989=B_SPLINE_CURVE_WITH_KNOTS('',3,(#1949,#1950,#1951,#1952,#1953,#1954,#1955,#1956,#1957,
#1958,#1959,#1960,#1961,#1962,#1963,#1964,#1965,#1966,#1967,#1968,#1969,#1970,#1971,#1972,#1973,
#1974,#1975,#1976,#1977,#1978,#1979,#1980,#1981,#1982,#1983,#1984,#1985,#1986,#1987,#1988),
.UNSPECIFIED.,.F.,.F.,(4,2,2,2,2,2,2,2,2,2,2,2,2,2,2,2,2,2,2,4),(0.,0.201420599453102,
0.403370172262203,0.605606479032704,0.80763115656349,0.998728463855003,1.1897171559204,
1.36102508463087,1.53220687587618,1.6881742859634,1.84411166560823,1.99593309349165,
2.14777630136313,2.30613943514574,2.46454134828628,2.63684336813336,2.8092918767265,
2.9985827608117,3.18757619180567,3.25861009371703),.UNSPECIFIED.);
#1990=CARTESIAN_POINT('',(21.,0.,23.04));
#1991=VERTEX_POINT('',#1990);
#1992=EDGE_CURVE('E1049',#1929,#1991,#1989,.T.);
#1993=ORIENTED_EDGE('',*,*,#1992,.T.);
#1994=CARTESIAN_POINT('',(21.977272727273,-0.999741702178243,22.5736923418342));
#1995=VERTEX_POINT('',#1994);
#1996=EDGE_CURVE('E1051',#1991,#1995,#1989,.T.);
#1997=ORIENTED_EDGE('',*,*,#1996,.T.);
#1998=DIRECTION('',(0.,0.,-1.));
#1999=VECTOR('',#1998,1.);
#2000=CARTESIAN_POINT('',(21.977272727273,-0.999741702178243,24.));
#2001=LINE('',#2000,#1999);
#2002=EDGE_CURVE('E932',#1995,#416,#2001,.T.);
#2003=ORIENTED_EDGE('',*,*,#2002,.T.);
#2004=EDGE_LOOP('',(#1946,#1947,#1948,#1993,#1997,#2003));
#2005=FACE_BOUND('',#2004,.T.);
#2006=ADVANCED_FACE('F1059',(#2005),#1945,.F.);
#2007=CARTESIAN_POINT('',(-2.26537538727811E-11,5.02462654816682E-12,24.));
#2008=DIRECTION('',(0.,0.,-1.));
#2009=DIRECTION('',(-1.,0.,0.));
#2010=AXIS2_PLACEMENT_3D('',#2007,#2008,#2009);
#2011=CYLINDRICAL_SURFACE('',#2010,22.0000000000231);
#2012=ORIENTED_EDGE('',*,*,#426,.T.);
#2013=ORIENTED_EDGE('',*,*,#2002,.F.);
#2014=CARTESIAN_POINT('',(0.,0.,22.5736923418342));
#2015=DIRECTION('',(0.,0.,-1.));
#2016=DIRECTION('',(-1.,0.,0.));
#2017=AXIS2_PLACEMENT_3D('',#2014,#2015,#2016);
#2018=CIRCLE('',#2017,22.0000000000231);
#2019=CARTESIAN_POINT('',(20.686937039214,-7.4866972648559,22.5736923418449));
#2020=VERTEX_POINT('',#2019);
#2021=EDGE_CURVE('E706',#1995,#2020,#2018,.T.);
#2022=ORIENTED_EDGE('',*,*,#2021,.T.);
#2023=DIRECTION('',(0.,0.,-1.));
#2024=VECTOR('',#2023,1.);
#2025=CARTESIAN_POINT('',(20.686937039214,-7.4866972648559,24.));
#2026=LINE('',#2025,#2024);
#2027=EDGE_CURVE('E929',#2020,#425,#2026,.T.);
#2028=ORIENTED_EDGE('',*,*,#2027,.T.);
#2029=EDGE_LOOP('',(#2012,#2013,#2022,#2028));
#2030=FACE_BOUND('',#2029,.T.);
#2031=ADVANCED_FACE('F1063',(#2030),#2011,.T.);
#2032=CARTESIAN_POINT('',(20.3253497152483,-8.41903551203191,24.));
#2033=DIRECTION('',(0.,0.,-1.));
#2034=DIRECTION('',(-1.,0.,0.));
#2035=AXIS2_PLACEMENT_3D('',#2032,#2033,#2034);
#2036=CYLINDRICAL_SURFACE('',#2035,0.999999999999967);
#2037=ORIENTED_EDGE('',*,*,#480,.T.);
#2038=ORIENTED_EDGE('',*,*,#471,.T.);
#2039=ORIENTED_EDGE('',*,*,#2027,.F.);
#2040=CARTESIAN_POINT('',(20.687137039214,-7.48677485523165,22.5735923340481));
#2041=CARTESIAN_POINT('',(20.6303586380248,-7.46471723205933,22.6019842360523));
#2042=CARTESIAN_POINT('',(20.5715568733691,-7.4478909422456,22.6304416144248));
#2043=CARTESIAN_POINT('',(20.4514048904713,-7.42513027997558,22.6867343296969));
#2044=CARTESIAN_POINT('',(20.3900483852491,-7.41922462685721,22.7145678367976));
#2045=CARTESIAN_POINT('',(20.2665131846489,-7.4188549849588,22.7687404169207));
#2046=CARTESIAN_POINT('',(20.2043334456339,-7.42440725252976,22.7950773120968));
#2047=CARTESIAN_POINT('',(20.0811788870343,-7.44728679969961,22.8452567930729));
#2048=CARTESIAN_POINT('',(20.0202028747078,-7.46460175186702,22.8691019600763));
#2049=CARTESIAN_POINT('',(19.9047549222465,-7.50978719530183,22.9121058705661));
#2050=CARTESIAN_POINT('',(19.8501095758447,-7.53703611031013,22.9314483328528));
#2051=CARTESIAN_POINT('',(19.7458132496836,-7.60178616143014,22.966092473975));
#2052=CARTESIAN_POINT('',(19.6961594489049,-7.63928146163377,22.9813964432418));
#2053=CARTESIAN_POINT('',(19.608782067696,-7.71927057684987,23.0057646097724));
#2054=CARTESIAN_POINT('',(19.5703563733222,-7.76085116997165,23.0153092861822));
#2055=CARTESIAN_POINT('',(19.500809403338,-7.85040550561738,23.0299298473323));
#2056=CARTESIAN_POINT('',(19.4696827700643,-7.8983745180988,23.0350090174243));
#2057=CARTESIAN_POINT('',(19.4183819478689,-7.99463357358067,23.0401660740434));
#2058=CARTESIAN_POINT('',(19.3974801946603,-8.04251614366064,23.0406483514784));
#2059=CARTESIAN_POINT('',(19.3634198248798,-8.14083495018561,23.0376406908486));
#2060=CARTESIAN_POINT('',(19.3502597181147,-8.19127069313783,23.0341515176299));
#2061=CARTESIAN_POINT('',(19.3321946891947,-8.29181681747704,23.0235203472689));
#2062=CARTESIAN_POINT('',(19.3270810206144,-8.34190064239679,23.0164772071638));
#2063=CARTESIAN_POINT('',(19.3243605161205,-8.44169217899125,22.9991066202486));
#2064=CARTESIAN_POINT('',(19.326754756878,-8.49139983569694,22.9887787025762));
#2065=CARTESIAN_POINT('',(19.338965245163,-8.59133660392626,22.9647397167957));
#2066=CARTESIAN_POINT('',(19.3490957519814,-8.64149646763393,22.9509024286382));
#2067=CARTESIAN_POINT('',(19.3765538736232,-8.73896118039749,22.9206116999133));
#2068=CARTESIAN_POINT('',(19.3938832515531,-8.78626532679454,22.9041576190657));
#2069=CARTESIAN_POINT('',(19.4368468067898,-8.8811008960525,22.8676103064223));
#2070=CARTESIAN_POINT('',(19.4630763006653,-8.92828800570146,22.8473244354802));
#2071=CARTESIAN_POINT('',(19.52227954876,-9.01731665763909,22.8048877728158));
#2072=CARTESIAN_POINT('',(19.5552590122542,-9.05915362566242,22.7827354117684));
#2073=CARTESIAN_POINT('',(19.6304986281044,-9.14052389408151,22.7349330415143));
#2074=CARTESIAN_POINT('',(19.6733506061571,-9.1794331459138,22.7091527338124));
#2075=CARTESIAN_POINT('',(19.7647116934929,-9.24908159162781,22.6568073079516));
#2076=CARTESIAN_POINT('',(19.8132118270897,-9.27983350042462,22.6302434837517));
#2077=CARTESIAN_POINT('',(19.8830391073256,-9.31615818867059,22.5935714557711));
#2078=CARTESIAN_POINT('',(19.9024925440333,-9.32549047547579,22.5835106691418));
#2079=CARTESIAN_POINT('',(19.9222215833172,-9.334179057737,22.5734611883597));
#2080=B_SPLINE_CURVE_WITH_KNOTS('',3,(#2040,#2041,#2042,#2043,#2044,#2045,#2046,#2047,#2048,
#2049,#2050,#2051,#2052,#2053,#2054,#2055,#2056,#2057,#2058,#2059,#2060,#2061,#2062,#2063,#2064,
#2065,#2066,#2067,#2068,#2069,#2070,#2071,#2072,#2073,#2074,#2075,#2076,#2077,#2078,#2079),
.UNSPECIFIED.,.F.,.F.,(4,2,2,2,2,2,2,2,2,2,2,2,2,2,2,2,2,2,2,4),(0.,0.201420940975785,
0.403370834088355,0.605607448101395,0.80763244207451,0.998730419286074,1.18971978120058,
1.36102842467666,1.53221092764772,1.68817870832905,1.8441164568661,1.99593782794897,
2.14778097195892,2.30614369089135,2.46454521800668,2.63684671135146,2.80929454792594,
2.99858451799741,3.18757768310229,3.25895226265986),.UNSPECIFIED.);
#2081=CARTESIAN_POINT('',(19.4014701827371,-8.03635207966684,23.04));
#2082=VERTEX_POINT('',#2081);
#2083=EDGE_CURVE('E1079',#2020,#2082,#2080,.T.);
#2084=ORIENTED_EDGE('',*,*,#2083,.T.);
#2085=CARTESIAN_POINT('',(19.921767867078,-9.333979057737,22.5736923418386));
#2086=VERTEX_POINT('',#2085);
#2087=EDGE_CURVE('E1074',#2082,#2086,#2080,.T.);
#2088=ORIENTED_EDGE('',*,*,#2087,.T.);
#2089=DIRECTION('',(0.,0.,-1.));
#2090=VECTOR('',#2089,1.);
#2091=CARTESIAN_POINT('',(19.921767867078,-9.333979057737,24.));
#2092=LINE('',#2091,#2090);
#2093=EDGE_CURVE('E926',#2086,#479,#2092,.T.);
#2094=ORIENTED_EDGE('',*,*,#2093,.T.);
#2095=EDGE_LOOP('',(#2037,#2038,#2039,#2084,#2088,#2094));
#2096=FACE_BOUND('',#2095,.T.);
#2097=ADVANCED_FACE('F1066',(#2096),#2036,.F.);
#2098=CARTESIAN_POINT('',(-1.04621172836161E-11,9.4542429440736E-12,24.));
#2099=DIRECTION('',(0.,0.,-1.));
#2100=DIRECTION('',(-1.,0.,0.));
#2101=AXIS2_PLACEMENT_3D('',#2098,#2099,#2100);
#2102=CYLINDRICAL_SURFACE('',#2101,22.0000000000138);
#2103=ORIENTED_EDGE('',*,*,#489,.T.);
#2104=ORIENTED_EDGE('',*,*,#2093,.F.);
#2105=CARTESIAN_POINT('',(0.,0.,22.5736923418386));
#2106=DIRECTION('',(0.,0.,-1.));
#2107=DIRECTION('',(-1.,0.,0.));
#2108=AXIS2_PLACEMENT_3D('',#2105,#2106,#2107);
#2109=CIRCLE('',#2108,22.0000000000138);
#2110=CARTESIAN_POINT('',(16.247202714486,-14.833354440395,22.5736923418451));
#2111=VERTEX_POINT('',#2110);
#2112=EDGE_CURVE('E704',#2086,#2111,#2109,.T.);
#2113=ORIENTED_EDGE('',*,*,#2112,.T.);
#2114=DIRECTION('',(0.,0.,-1.));
#2115=VECTOR('',#2114,1.);
#2116=CARTESIAN_POINT('',(16.247202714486,-14.833354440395,24.));
#2117=LINE('',#2116,#2115);
#2118=EDGE_CURVE('E923',#2111,#488,#2117,.T.);
#2119=ORIENTED_EDGE('',*,*,#2118,.T.);
#2120=EDGE_LOOP('',(#2103,#2104,#2113,#2119));
#2121=FACE_BOUND('',#2120,.T.);
#2122=ADVANCED_FACE('F1071',(#2121),#2102,.T.);
#2123=CARTESIAN_POINT('',(15.5563491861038,-15.5563491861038,24.));
#2124=DIRECTION('',(0.,0.,-1.));
#2125=DIRECTION('',(-1.,0.,0.));
#2126=AXIS2_PLACEMENT_3D('',#2123,#2124,#2125);
#2127=CYLINDRICAL_SURFACE('',#2126,1.00000000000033);
#2128=ORIENTED_EDGE('',*,*,#606,.T.);
#2129=ORIENTED_EDGE('',*,*,#534,.T.);
#2130=ORIENTED_EDGE('',*,*,#2118,.F.);
#2131=CARTESIAN_POINT('',(16.247402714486,-14.8335456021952,22.5735633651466));
#2132=CARTESIAN_POINT('',(16.2033896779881,-14.7914358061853,22.6019554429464));
#2133=CARTESIAN_POINT('',(16.1555050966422,-14.7533846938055,22.6304131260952));
#2134=CARTESIAN_POINT('',(16.0532128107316,-14.686369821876,22.6867066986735));
#2135=CARTESIAN_POINT('',(15.9987883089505,-14.6574301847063,22.7145407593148));
#2136=CARTESIAN_POINT('',(15.8848006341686,-14.6098067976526,22.7687147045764));
#2137=CARTESIAN_POINT('',(15.825230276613,-14.5911376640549,22.7950524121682));
#2138=CARTESIAN_POINT('',(15.7026960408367,-14.5651390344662,22.8452338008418));
#2139=CARTESIAN_POINT('',(15.6397357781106,-14.5577976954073,22.8690800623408));
#2140=CARTESIAN_POINT('',(15.5157836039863,-14.5553561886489,22.912086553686));
#2141=CARTESIAN_POINT('',(15.4548693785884,-14.5596154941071,22.9314304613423));
#2142=CARTESIAN_POINT('',(15.3337310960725,-14.5795174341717,22.9660776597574));
#2143=CARTESIAN_POINT('',(15.2735066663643,-14.5951535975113,22.9813832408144));
#2144=CARTESIAN_POINT('',(15.162166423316,-14.6356102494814,23.0057545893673));
#2145=CARTESIAN_POINT('',(15.1107514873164,-14.6593183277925,23.0153008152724));
#2146=CARTESIAN_POINT('',(15.0122230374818,-14.7154368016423,23.0299244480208));
#2147=CARTESIAN_POINT('',(14.9651063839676,-14.7478407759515,23.035005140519));
#2148=CARTESIAN_POINT('',(14.8808692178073,-14.8171371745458,23.0401649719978));
#2149=CARTESIAN_POINT('',(14.8432324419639,-14.8533746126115,23.0406485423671));
#2150=CARTESIAN_POINT('',(14.7741351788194,-14.9311724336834,23.0376433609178));
#2151=CARTESIAN_POINT('',(14.7426735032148,-14.9727317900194,23.0341553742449));
#2152=CARTESIAN_POINT('',(14.6875017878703,-15.0587090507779,23.0235264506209));
#2153=CARTESIAN_POINT('',(14.663608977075,-15.1030224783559,23.0164844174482));
#2154=CARTESIAN_POINT('',(14.622902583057,-15.1941749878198,22.9991159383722));
#2155=CARTESIAN_POINT('',(14.6060900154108,-15.2410144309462,22.9887890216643));
#2156=CARTESIAN_POINT('',(14.5791223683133,-15.3380152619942,22.9647520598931));
#2157=CARTESIAN_POINT('',(14.5692840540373,-15.3882329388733,22.9509158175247));
#2158=CARTESIAN_POINT('',(14.5573491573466,-15.488785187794,22.9206270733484));
#2159=CARTESIAN_POINT('',(14.5552544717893,-15.5391197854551,22.9041739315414));
#2160=CARTESIAN_POINT('',(14.5586504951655,-15.6431771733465,22.8676285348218));
#2161=CARTESIAN_POINT('',(14.564822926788,-15.6968097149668,22.8473436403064));
#2162=CARTESIAN_POINT('',(14.5854442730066,-15.8017175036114,22.804908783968));
#2163=CARTESIAN_POINT('',(14.5999002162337,-15.8529907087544,22.7827572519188));
#2164=CARTESIAN_POINT('',(14.6382676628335,-15.9569609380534,22.7349564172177));
#2165=CARTESIAN_POINT('',(14.6629647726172,-16.0093079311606,22.7091767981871));
#2166=CARTESIAN_POINT('',(14.7207120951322,-16.1086190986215,22.6568325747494));
#2167=CARTESIAN_POINT('',(14.7537491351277,-16.1555915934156,22.6302692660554));
#2168=CARTESIAN_POINT('',(14.8043214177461,-16.2158335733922,22.5936230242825));
#2169=CARTESIAN_POINT('',(14.8186842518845,-16.2318614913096,22.5835875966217));
#2170=CARTESIAN_POINT('',(14.8335456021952,-16.247402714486,22.5735633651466));
#2171=B_SPLINE_CURVE_WITH_KNOTS('',3,(#2131,#2132,#2133,#2134,#2135,#2136,#2137,#2138,#2139,
#2140,#2141,#2142,#2143,#2144,#2145,#2146,#2147,#2148,#2149,#2150,#2151,#2152,#2153,#2154,#2155,
#2156,#2157,#2158,#2159,#2160,#2161,#2162,#2163,#2164,#2165,#2166,#2167,#2168,#2169,#2170),
.UNSPECIFIED.,.F.,.F.,(4,2,2,2,2,2,2,2,2,2,2,2,2,2,2,2,2,2,2,4),(0.,0.201422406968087,
0.403373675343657,0.605611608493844,0.807637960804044,0.998738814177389,1.18973105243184,
1.36104276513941,1.53222832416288,1.68819769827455,1.84413702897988,1.99595814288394,
2.14780102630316,2.30616203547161,2.46456183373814,2.63686071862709,2.80930601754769,
2.9985936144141,3.18758408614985,3.25877905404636),.UNSPECIFIED.);
#2172=CARTESIAN_POINT('',(14.849242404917,-14.849242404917,23.04));
#2173=VERTEX_POINT('',#2172);
#2174=EDGE_CURVE('E1086',#2111,#2173,#2171,.T.);
#2175=ORIENTED_EDGE('',*,*,#2174,.T.);
#2176=CARTESIAN_POINT('',(14.833354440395,-16.247202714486,22.5736923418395));
#2177=VERTEX_POINT('',#2176);
#2178=EDGE_CURVE('E1088',#2173,#2177,#2171,.T.);
#2179=ORIENTED_EDGE('',*,*,#2178,.T.);
#2180=DIRECTION('',(0.,0.,-1.));
#2181=VECTOR('',#2180,1.);
#2182=CARTESIAN_POINT('',(14.833354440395,-16.247202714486,24.));
#2183=LINE('',#2182,#2181);
#2184=EDGE_CURVE('E920',#2177,#605,#2183,.T.);
#2185=ORIENTED_EDGE('',*,*,#2184,.T.);
#2186=EDGE_LOOP('',(#2128,#2129,#2130,#2175,#2179,#2185));
#2187=FACE_BOUND('',#2186,.T.);
#2188=ADVANCED_FACE('F1096',(#2187),#2127,.F.);
#2189=CARTESIAN_POINT('',(-8.16881284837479E-12,8.79157857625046E-12,24.));
#2190=DIRECTION('',(0.,0.,-1.));
#2191=DIRECTION('',(-1.,0.,0.));
#2192=AXIS2_PLACEMENT_3D('',#2189,#2190,#2191);
#2193=CYLINDRICAL_SURFACE('',#2192,22.0000000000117);
#2194=ORIENTED_EDGE('',*,*,#615,.T.);
#2195=ORIENTED_EDGE('',*,*,#2184,.F.);
#2196=CARTESIAN_POINT('',(0.,0.,22.5736923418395));
#2197=DIRECTION('',(0.,0.,-1.));
#2198=DIRECTION('',(-1.,0.,0.));
#2199=AXIS2_PLACEMENT_3D('',#2196,#2197,#2198);
#2200=CIRCLE('',#2199,22.0000000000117);
#2201=CARTESIAN_POINT('',(9.3339790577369,-19.921767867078,22.5736923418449));
#2202=VERTEX_POINT('',#2201);
#2203=EDGE_CURVE('E702',#2177,#2202,#2200,.T.);
#2204=ORIENTED_EDGE('',*,*,#2203,.T.);
#2205=DIRECTION('',(0.,0.,-1.));
#2206=VECTOR('',#2205,1.);
#2207=CARTESIAN_POINT('',(9.3339790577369,-19.921767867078,24.));
#2208=LINE('',#2207,#2206);
#2209=EDGE_CURVE('E917',#2202,#614,#2208,.T.);
#2210=ORIENTED_EDGE('',*,*,#2209,.T.);
#2211=EDGE_LOOP('',(#2194,#2195,#2204,#2210));
#2212=FACE_BOUND('',#2211,.T.);
#2213=ADVANCED_FACE('F1100',(#2212),#2193,.T.);
#2214=CARTESIAN_POINT('',(8.41903551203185,-20.3253497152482,24.));
#2215=DIRECTION('',(0.,0.,-1.));
#2216=DIRECTION('',(-1.,0.,0.));
#2217=AXIS2_PLACEMENT_3D('',#2214,#2215,#2216);
#2218=CYLINDRICAL_SURFACE('',#2217,0.999999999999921);
#2219=ORIENTED_EDGE('',*,*,#669,.T.);
#2220=ORIENTED_EDGE('',*,*,#660,.T.);
#2221=ORIENTED_EDGE('',*,*,#2209,.F.);
#2222=CARTESIAN_POINT('',(9.3341790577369,-19.9222215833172,22.5734611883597));
#2223=CARTESIAN_POINT('',(9.30964258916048,-19.8664672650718,22.6018538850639));
#2224=CARTESIAN_POINT('',(9.27997543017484,-19.8129803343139,22.6303126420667));
#2225=CARTESIAN_POINT('',(9.21113560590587,-19.7119044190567,22.686609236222));
#2226=CARTESIAN_POINT('',(9.171938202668,-19.6643312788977,22.71444524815));
#2227=CARTESIAN_POINT('',(9.08486965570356,-19.5766923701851,22.768624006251));
#2228=CARTESIAN_POINT('',(9.03698628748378,-19.5366373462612,22.7949645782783));
#2229=CARTESIAN_POINT('',(8.93374305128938,-19.4657037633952,22.8451526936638));
#2230=CARTESIAN_POINT('',(8.87839105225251,-19.4348156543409,22.8690028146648));
#2231=CARTESIAN_POINT('',(8.76481700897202,-19.3851008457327,22.9120184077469));
#2232=CARTESIAN_POINT('',(8.7069118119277,-19.3657124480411,22.931367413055));
#2233=CARTESIAN_POINT('',(8.58738031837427,-19.3377165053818,22.9660253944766));
#2234=CARTESIAN_POINT('',(8.52575615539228,-19.3291028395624,22.9813366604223));
#2235=CARTESIAN_POINT('',(8.40740529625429,-19.3238482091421,23.0057192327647));
#2236=CARTESIAN_POINT('',(8.35082820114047,-19.3260650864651,23.0152709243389));
#2237=CARTESIAN_POINT('',(8.23831565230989,-19.3401859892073,23.0299053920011));
#2238=CARTESIAN_POINT('',(8.18237975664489,-19.3520828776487,23.0349914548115));
#2239=CARTESIAN_POINT('',(8.07802564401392,-19.3838508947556,23.0401610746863));
#2240=CARTESIAN_POINT('',(8.02938120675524,-19.4029189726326,23.0406492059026));
#2241=CARTESIAN_POINT('',(7.93576018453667,-19.4483378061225,23.0376527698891));
#2242=CARTESIAN_POINT('',(7.89078289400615,-19.4746871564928,23.0341689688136));
#2243=CARTESIAN_POINT('',(7.80689701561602,-19.5329937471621,23.0235479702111));
#2244=CARTESIAN_POINT('',(7.76785937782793,-19.56478422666,23.0165098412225));
#2245=CARTESIAN_POINT('',(7.69535702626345,-19.6334088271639,22.9991487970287));
#2246=CARTESIAN_POINT('',(7.66189311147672,-19.6702436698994,22.9888254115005));
#2247=CARTESIAN_POINT('',(7.5998448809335,-19.749529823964,22.9647955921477));
#2248=CARTESIAN_POINT('',(7.57153143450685,-19.7921542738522,22.9509630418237));
#2249=CARTESIAN_POINT('',(7.52201140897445,-19.8804748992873,22.9206812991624));
#2250=CARTESIAN_POINT('',(7.50080657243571,-19.9261718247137,22.9042314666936));
#2251=CARTESIAN_POINT('',(7.46410726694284,-20.0235987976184,22.8676928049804));
#2252=CARTESIAN_POINT('',(7.449276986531,-20.075506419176,22.8474113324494));
#2253=CARTESIAN_POINT('',(7.42816422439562,-20.1803123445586,22.8049828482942));
#2254=CARTESIAN_POINT('',(7.42188901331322,-20.23321145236,22.7828342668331));
#2255=CARTESIAN_POINT('',(7.41752793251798,-20.343944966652,22.7350389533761));
#2256=CARTESIAN_POINT('',(7.42030180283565,-20.4017567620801,22.7092618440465));
#2257=CARTESIAN_POINT('',(7.43562621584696,-20.5156056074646,22.6569219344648));
#2258=CARTESIAN_POINT('',(7.44816142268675,-20.5716452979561,22.6303604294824));
#2259=CARTESIAN_POINT('',(7.47182855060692,-20.6467005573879,22.5936944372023));
#2260=CARTESIAN_POINT('',(7.47897691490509,-20.6670487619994,22.5836377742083));
#2261=CARTESIAN_POINT('',(7.48677485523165,-20.687137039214,22.5735923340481));
#2262=B_SPLINE_CURVE_WITH_KNOTS('',3,(#2222,#2223,#2224,#2225,#2226,#2227,#2228,#2229,#2230,
#2231,#2232,#2233,#2234,#2235,#2236,#2237,#2238,#2239,#2240,#2241,#2242,#2243,#2244,#2245,#2246,
#2247,#2248,#2249,#2250,#2251,#2252,#2253,#2254,#2255,#2256,#2257,#2258,#2259,#2260,#2261),
.UNSPECIFIED.,.F.,.F.,(4,2,2,2,2,2,2,2,2,2,2,2,2,2,2,2,2,2,2,4),(0.,0.201427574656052,
0.403383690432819,0.605626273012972,0.807657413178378,0.998768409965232,1.18977079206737,
1.36109333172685,1.53228967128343,1.68826466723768,1.84420958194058,1.99602979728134,
2.14787175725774,2.30622670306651,2.46462043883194,2.63691028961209,2.80934647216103,
2.998624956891,3.18760666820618,3.25895217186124),.UNSPECIFIED.);
#2263=CARTESIAN_POINT('',(8.0363520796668,-19.4014701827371,23.04));
#2264=VERTEX_POINT('',#2263);
#2265=EDGE_CURVE('E1116',#2202,#2264,#2262,.T.);
#2266=ORIENTED_EDGE('',*,*,#2265,.T.);
#2267=CARTESIAN_POINT('',(7.48669726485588,-20.686937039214,22.5736923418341));
#2268=VERTEX_POINT('',#2267);
#2269=EDGE_CURVE('E1111',#2264,#2268,#2262,.T.);
#2270=ORIENTED_EDGE('',*,*,#2269,.T.);
#2271=DIRECTION('',(0.,0.,-1.));
#2272=VECTOR('',#2271,1.);
#2273=CARTESIAN_POINT('',(7.48669726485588,-20.686937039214,24.));
#2274=LINE('',#2273,#2272);
#2275=EDGE_CURVE('E914',#2268,#668,#2274,.T.);
#2276=ORIENTED_EDGE('',*,*,#2275,.T.);
#2277=EDGE_LOOP('',(#2219,#2220,#2221,#2266,#2270,#2276));
#2278=FACE_BOUND('',#2277,.T.);
#2279=ADVANCED_FACE('F1103',(#2278),#2218,.F.);
#2280=CARTESIAN_POINT('',(-5.10355646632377E-12,2.29365137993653E-11,24.));
#2281=DIRECTION('',(0.,0.,-1.));
#2282=DIRECTION('',(-1.,0.,0.));
#2283=AXIS2_PLACEMENT_3D('',#2280,#2281,#2282);
#2284=CYLINDRICAL_SURFACE('',#2283,22.0000000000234);
#2285=ORIENTED_EDGE('',*,*,#678,.T.);
#2286=ORIENTED_EDGE('',*,*,#2275,.F.);
#2287=CARTESIAN_POINT('',(0.,0.,22.5736923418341));
#2288=DIRECTION('',(0.,0.,-1.));
#2289=DIRECTION('',(-1.,0.,0.));
#2290=AXIS2_PLACEMENT_3D('',#2287,#2288,#2289);
#2291=CIRCLE('',#2290,22.0000000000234);
#2292=CARTESIAN_POINT('',(0.99974170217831,-21.977272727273,22.5736923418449));
#2293=VERTEX_POINT('',#2292);
#2294=EDGE_CURVE('E700',#2268,#2293,#2291,.T.);
#2295=ORIENTED_EDGE('',*,*,#2294,.T.);
#2296=DIRECTION('',(0.,0.,-1.));
#2297=VECTOR('',#2296,1.);
#2298=CARTESIAN_POINT('',(0.99974170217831,-21.977272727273,24.));
#2299=LINE('',#2298,#2297);
#2300=EDGE_CURVE('E911',#2293,#677,#2299,.T.);
#2301=ORIENTED_EDGE('',*,*,#2300,.T.);
#2302=EDGE_LOOP('',(#2285,#2286,#2295,#2301));
#2303=FACE_BOUND('',#2302,.T.);
#2304=ADVANCED_FACE('F1108',(#2303),#2284,.T.);
#2305=CARTESIAN_POINT('',(0.,-22.,24.));
#2306=DIRECTION('',(0.,0.,-1.));
#2307=DIRECTION('',(-1.,0.,0.));
#2308=AXIS2_PLACEMENT_3D('',#2305,#2306,#2307);
#2309=CYLINDRICAL_SURFACE('',#2308,1.);
#2310=ORIENTED_EDGE('',*,*,#795,.T.);
#2311=ORIENTED_EDGE('',*,*,#723,.T.);
#2312=ORIENTED_EDGE('',*,*,#2300,.F.);
#2313=CARTESIAN_POINT('',(0.999746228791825,-21.977472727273,22.5735990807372));
#2314=CARTESIAN_POINT('',(0.998395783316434,-21.9165753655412,22.6019909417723));
#2315=CARTESIAN_POINT('',(0.991437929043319,-21.8558106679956,22.6304482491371));
#2316=CARTESIAN_POINT('',(0.966484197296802,-21.7360950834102,22.6867407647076));
#2317=CARTESIAN_POINT('',(0.948459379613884,-21.6771493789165,22.7145741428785));
#2318=CARTESIAN_POINT('',(0.901524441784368,-21.5628770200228,22.7687464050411));
#2319=CARTESIAN_POINT('',(0.872598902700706,-21.5075556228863,22.795083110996));
#2320=CARTESIAN_POINT('',(0.804330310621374,-21.4025322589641,22.8452621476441));
#2321=CARTESIAN_POINT('',(0.764998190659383,-21.3528244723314,22.8691070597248));
#2322=CARTESIAN_POINT('',(0.679071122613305,-21.2634574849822,22.9121103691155));
#2323=CARTESIAN_POINT('',(0.632984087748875,-21.2234001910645,22.9314524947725));
#2324=CARTESIAN_POINT('',(0.533249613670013,-21.1518232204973,22.9660959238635));
#2325=CARTESIAN_POINT('',(0.479606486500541,-21.1202987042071,22.9813995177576));
#2326=CARTESIAN_POINT('',(0.37226793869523,-21.0701845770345,23.0057669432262));
#2327=CARTESIAN_POINT('',(0.31914752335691,-21.0505968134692,23.0153112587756));
#2328=CARTESIAN_POINT('',(0.209795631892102,-21.0206162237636,23.0299311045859));
#2329=CARTESIAN_POINT('',(0.153566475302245,-21.0102166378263,23.0350099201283));
#2330=CARTESIAN_POINT('',(0.0450029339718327,-20.9996589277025,23.0401663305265));
#2331=CARTESIAN_POINT('',(-0.00723343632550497,-20.9986727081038,23.0406483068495));
#2332=CARTESIAN_POINT('',(-0.111102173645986,-21.0048311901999,23.0376400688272));
#2333=CARTESIAN_POINT('',(-0.162734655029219,-21.0119743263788,23.0341506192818));
#2334=CARTESIAN_POINT('',(-0.262539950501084,-21.0337628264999,23.0235189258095));
#2335=CARTESIAN_POINT('',(-0.310768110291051,-21.0482051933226,23.0164755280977));
#2336=CARTESIAN_POINT('',(-0.404004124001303,-21.083881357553,22.9991044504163));
#2337=CARTESIAN_POINT('',(-0.449011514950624,-21.1051161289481,22.9887762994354));
#2338=CARTESIAN_POINT('',(-0.536667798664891,-21.1546422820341,22.9647368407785));
#2339=CARTESIAN_POINT('',(-0.579132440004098,-21.1831975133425,22.9508993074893));
#2340=CARTESIAN_POINT('',(-0.658669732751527,-21.2458646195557,22.9206081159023));
#2341=CARTESIAN_POINT('',(-0.695741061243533,-21.2799778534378,22.9041538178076));
#2342=CARTESIAN_POINT('',(-0.766915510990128,-21.3559639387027,22.8676060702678));
#2343=CARTESIAN_POINT('',(-0.800472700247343,-21.3982550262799,22.8473199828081));
#2344=CARTESIAN_POINT('',(-0.860067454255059,-21.4870224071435,22.8048828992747));
#2345=CARTESIAN_POINT('',(-0.886098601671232,-21.533502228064,22.7827303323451));
#2346=CARTESIAN_POINT('',(-0.932480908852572,-21.6341545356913,22.7349275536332));
#2347=CARTESIAN_POINT('',(-0.952029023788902,-21.6886349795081,22.7091470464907));
#2348=CARTESIAN_POINT('',(-0.981412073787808,-21.799695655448,22.6568013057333));
#2349=CARTESIAN_POINT('',(-0.991262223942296,-21.8562724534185,22.6302373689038));
#2350=CARTESIAN_POINT('',(-0.998090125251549,-21.9345827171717,22.5936133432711));
#2351=CARTESIAN_POINT('',(-0.999264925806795,-21.9560235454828,22.5836006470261));
#2352=CARTESIAN_POINT('',(-0.999746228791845,-21.977472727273,22.5735990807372));
#2353=B_SPLINE_CURVE_WITH_KNOTS('',3,(#2313,#2314,#2315,#2316,#2317,#2318,#2319,#2320,#2321,
#2322,#2323,#2324,#2325,#2326,#2327,#2328,#2329,#2330,#2331,#2332,#2333,#2334,#2335,#2336,#2337,
#2338,#2339,#2340,#2341,#2342,#2343,#2344,#2345,#2346,#2347,#2348,#2349,#2350,#2351,#2352),
.UNSPECIFIED.,.F.,.F.,(4,2,2,2,2,2,2,2,2,2,2,2,2,2,2,2,2,2,2,4),(0.,0.201420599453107,
0.403370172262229,0.605606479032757,0.807631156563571,0.998728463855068,1.18971715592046,
1.36102508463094,1.53220687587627,1.6881742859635,1.84411166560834,1.99593309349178,
2.14777630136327,2.30613943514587,2.4645413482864,2.63684336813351,2.80929187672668,
2.99858276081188,3.18757619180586,3.25861009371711),.UNSPECIFIED.);
#2354=CARTESIAN_POINT('',(0.,-21.,23.04));
#2355=VERTEX_POINT('',#2354);
#2356=EDGE_CURVE('E1123',#2293,#2355,#2353,.T.);
#2357=ORIENTED_EDGE('',*,*,#2356,.T.);
#2358=CARTESIAN_POINT('',(-0.999741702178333,-21.977272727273,22.5736923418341));
#2359=VERTEX_POINT('',#2358);
#2360=EDGE_CURVE('E1125',#2355,#2359,#2353,.T.);
#2361=ORIENTED_EDGE('',*,*,#2360,.T.);
#2362=DIRECTION('',(0.,0.,-1.));
#2363=VECTOR('',#2362,1.);
#2364=CARTESIAN_POINT('',(-0.999741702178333,-21.977272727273,24.));
#2365=LINE('',#2364,#2363);
#2366=EDGE_CURVE('E908',#2359,#794,#2365,.T.);
#2367=ORIENTED_EDGE('',*,*,#2366,.T.);
#2368=EDGE_LOOP('',(#2310,#2311,#2312,#2357,#2361,#2367));
#2369=FACE_BOUND('',#2368,.T.);
#2370=ADVANCED_FACE('F1133',(#2369),#2309,.F.);
#2371=CARTESIAN_POINT('',(5.11353112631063E-12,2.29712082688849E-11,24.));
#2372=DIRECTION('',(0.,0.,-1.));
#2373=DIRECTION('',(-1.,0.,0.));
#2374=AXIS2_PLACEMENT_3D('',#2371,#2372,#2373);
#2375=CYLINDRICAL_SURFACE('',#2374,22.0000000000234);
#2376=ORIENTED_EDGE('',*,*,#804,.T.);
#2377=ORIENTED_EDGE('',*,*,#2366,.F.);
#2378=CARTESIAN_POINT('',(0.,0.,22.5736923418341));
#2379=DIRECTION('',(0.,0.,-1.));
#2380=DIRECTION('',(-1.,0.,0.));
#2381=AXIS2_PLACEMENT_3D('',#2378,#2379,#2380);
#2382=CIRCLE('',#2381,22.0000000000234);
#2383=CARTESIAN_POINT('',(-7.4866972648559,-20.686937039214,22.5736923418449));
#2384=VERTEX_POINT('',#2383);
#2385=EDGE_CURVE('E698',#2359,#2384,#2382,.T.);
#2386=ORIENTED_EDGE('',*,*,#2385,.T.);
#2387=DIRECTION('',(0.,0.,-1.));
#2388=VECTOR('',#2387,1.);
#2389=CARTESIAN_POINT('',(-7.4866972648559,-20.686937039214,24.));
#2390=LINE('',#2389,#2388);
#2391=EDGE_CURVE('E905',#2384,#803,#2390,.T.);
#2392=ORIENTED_EDGE('',*,*,#2391,.T.);
#2393=EDGE_LOOP('',(#2376,#2377,#2386,#2392));
#2394=FACE_BOUND('',#2393,.T.);
#2395=ADVANCED_FACE('F1137',(#2394),#2375,.T.);
#2396=CARTESIAN_POINT('',(-8.41903551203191,-20.3253497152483,24.));
#2397=DIRECTION('',(0.,0.,-1.));
#2398=DIRECTION('',(-1.,0.,0.));
#2399=AXIS2_PLACEMENT_3D('',#2396,#2397,#2398);
#2400=CYLINDRICAL_SURFACE('',#2399,0.999999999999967);
#2401=ORIENTED_EDGE('',*,*,#858,.T.);
#2402=ORIENTED_EDGE('',*,*,#849,.T.);
#2403=ORIENTED_EDGE('',*,*,#2391,.F.);
#2404=CARTESIAN_POINT('',(-7.48677485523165,-20.687137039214,22.5735923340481));
#2405=CARTESIAN_POINT('',(-7.46471723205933,-20.6303586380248,22.6019842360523));
#2406=CARTESIAN_POINT('',(-7.4478909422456,-20.5715568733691,22.6304416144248));
#2407=CARTESIAN_POINT('',(-7.42513027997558,-20.4514048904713,22.6867343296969));
#2408=CARTESIAN_POINT('',(-7.41922462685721,-20.3900483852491,22.7145678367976));
#2409=CARTESIAN_POINT('',(-7.4188549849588,-20.2665131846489,22.7687404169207));
#2410=CARTESIAN_POINT('',(-7.42440725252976,-20.2043334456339,22.7950773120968));
#2411=CARTESIAN_POINT('',(-7.44728679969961,-20.0811788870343,22.8452567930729));
#2412=CARTESIAN_POINT('',(-7.46460175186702,-20.0202028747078,22.8691019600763));
#2413=CARTESIAN_POINT('',(-7.50978719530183,-19.9047549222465,22.9121058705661));
#2414=CARTESIAN_POINT('',(-7.53703611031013,-19.8501095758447,22.9314483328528));
#2415=CARTESIAN_POINT('',(-7.60178616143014,-19.7458132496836,22.966092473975));
#2416=CARTESIAN_POINT('',(-7.63928146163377,-19.6961594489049,22.9813964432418));
#2417=CARTESIAN_POINT('',(-7.71927057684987,-19.608782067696,23.0057646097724));
#2418=CARTESIAN_POINT('',(-7.76085116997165,-19.5703563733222,23.0153092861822));
#2419=CARTESIAN_POINT('',(-7.85040550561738,-19.500809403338,23.0299298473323));
#2420=CARTESIAN_POINT('',(-7.8983745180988,-19.4696827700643,23.0350090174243));
#2421=CARTESIAN_POINT('',(-7.99463357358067,-19.4183819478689,23.0401660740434));
#2422=CARTESIAN_POINT('',(-8.04251614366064,-19.3974801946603,23.0406483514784));
#2423=CARTESIAN_POINT('',(-8.14083495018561,-19.3634198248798,23.0376406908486));
#2424=CARTESIAN_POINT('',(-8.19127069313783,-19.3502597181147,23.0341515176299));
#2425=CARTESIAN_POINT('',(-8.29181681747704,-19.3321946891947,23.0235203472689));
#2426=CARTESIAN_POINT('',(-8.34190064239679,-19.3270810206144,23.0164772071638));
#2427=CARTESIAN_POINT('',(-8.44169217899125,-19.3243605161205,22.9991066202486));
#2428=CARTESIAN_POINT('',(-8.49139983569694,-19.326754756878,22.9887787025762));
#2429=CARTESIAN_POINT('',(-8.59133660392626,-19.338965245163,22.9647397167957));
#2430=CARTESIAN_POINT('',(-8.64149646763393,-19.3490957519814,22.9509024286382));
#2431=CARTESIAN_POINT('',(-8.73896118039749,-19.3765538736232,22.9206116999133));
#2432=CARTESIAN_POINT('',(-8.78626532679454,-19.3938832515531,22.9041576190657));
#2433=CARTESIAN_POINT('',(-8.8811008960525,-19.4368468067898,22.8676103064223));
#2434=CARTESIAN_POINT('',(-8.92828800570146,-19.4630763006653,22.8473244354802));
#2435=CARTESIAN_POINT('',(-9.01731665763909,-19.52227954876,22.8048877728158));
#2436=CARTESIAN_POINT('',(-9.05915362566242,-19.5552590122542,22.7827354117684));
#2437=CARTESIAN_POINT('',(-9.14052389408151,-19.6304986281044,22.7349330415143));
#2438=CARTESIAN_POINT('',(-9.1794331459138,-19.6733506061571,22.7091527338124));
#2439=CARTESIAN_POINT('',(-9.24908159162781,-19.7647116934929,22.6568073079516));
#2440=CARTESIAN_POINT('',(-9.27983350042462,-19.8132118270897,22.6302434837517));
#2441=CARTESIAN_POINT('',(-9.31615818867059,-19.8830391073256,22.5935714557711));
#2442=CARTESIAN_POINT('',(-9.32549047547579,-19.9024925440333,22.5835106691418));
#2443=CARTESIAN_POINT('',(-9.334179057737,-19.9222215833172,22.5734611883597));
#2444=B_SPLINE_CURVE_WITH_KNOTS('',3,(#2404,#2405,#2406,#2407,#2408,#2409,#2410,#2411,#2412,
#2413,#2414,#2415,#2416,#2417,#2418,#2419,#2420,#2421,#2422,#2423,#2424,#2425,#2426,#2427,#2428,
#2429,#2430,#2431,#2432,#2433,#2434,#2435,#2436,#2437,#2438,#2439,#2440,#2441,#2442,#2443),
.UNSPECIFIED.,.F.,.F.,(4,2,2,2,2,2,2,2,2,2,2,2,2,2,2,2,2,2,2,4),(0.,0.201420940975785,
0.403370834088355,0.605607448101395,0.80763244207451,0.998730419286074,1.18971978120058,
1.36102842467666,1.53221092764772,1.68817870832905,1.8441164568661,1.99593782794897,
2.14778097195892,2.30614369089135,2.46454521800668,2.63684671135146,2.80929454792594,
2.99858451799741,3.18757768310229,3.25895226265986),.UNSPECIFIED.);
#2445=CARTESIAN_POINT('',(-8.03635207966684,-19.4014701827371,23.04));
#2446=VERTEX_POINT('',#2445);
#2447=EDGE_CURVE('E1151',#2384,#2446,#2444,.T.);
#2448=ORIENTED_EDGE('',*,*,#2447,.T.);
#2449=CARTESIAN_POINT('',(-9.333979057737,-19.921767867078,22.5736923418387));
#2450=VERTEX_POINT('',#2449);
#2451=EDGE_CURVE('E1146',#2446,#2450,#2444,.T.);
#2452=ORIENTED_EDGE('',*,*,#2451,.T.);
#2453=DIRECTION('',(0.,0.,-1.));
#2454=VECTOR('',#2453,1.);
#2455=CARTESIAN_POINT('',(-9.333979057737,-19.921767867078,24.));
#2456=LINE('',#2455,#2454);
#2457=EDGE_CURVE('E897',#2450,#857,#2456,.T.);
#2458=ORIENTED_EDGE('',*,*,#2457,.T.);
#2459=EDGE_LOOP('',(#2401,#2402,#2403,#2448,#2452,#2458));
#2460=FACE_BOUND('',#2459,.T.);
#2461=ADVANCED_FACE('F1140',(#2460),#2400,.F.);
#2462=CARTESIAN_POINT('',(9.31719978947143E-12,1.02591546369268E-11,24.));
#2463=DIRECTION('',(0.,0.,-1.));
#2464=DIRECTION('',(-1.,0.,0.));
#2465=AXIS2_PLACEMENT_3D('',#2462,#2463,#2464);
#2466=CYLINDRICAL_SURFACE('',#2465,22.0000000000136);
#2467=ORIENTED_EDGE('',*,*,#867,.T.);
#2468=ORIENTED_EDGE('',*,*,#2457,.F.);
#2469=CARTESIAN_POINT('',(0.,0.,22.5736923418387));
#2470=DIRECTION('',(0.,0.,-1.));
#2471=DIRECTION('',(-1.,0.,0.));
#2472=AXIS2_PLACEMENT_3D('',#2469,#2470,#2471);
#2473=CIRCLE('',#2472,22.0000000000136);
#2474=CARTESIAN_POINT('',(-14.833354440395,-16.247202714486,22.5736923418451));
#2475=VERTEX_POINT('',#2474);
#2476=EDGE_CURVE('E696',#2450,#2475,#2473,.T.);
#2477=ORIENTED_EDGE('',*,*,#2476,.T.);
#2478=DIRECTION('',(0.,0.,-1.));
#2479=VECTOR('',#2478,1.);
#2480=CARTESIAN_POINT('',(-14.833354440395,-16.247202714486,24.));
#2481=LINE('',#2480,#2479);
#2482=EDGE_CURVE('E894',#2475,#866,#2481,.T.);
#2483=ORIENTED_EDGE('',*,*,#2482,.T.);
#2484=EDGE_LOOP('',(#2467,#2468,#2477,#2483));
#2485=FACE_BOUND('',#2484,.T.);
#2486=ADVANCED_FACE('F866',(#2485),#2466,.T.);
#2487=CARTESIAN_POINT('',(-15.5563491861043,-15.5563491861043,24.));
#2488=DIRECTION('',(0.,0.,-1.));
#2489=DIRECTION('',(-1.,0.,0.));
#2490=AXIS2_PLACEMENT_3D('',#2487,#2488,#2489);
#2491=CYLINDRICAL_SURFACE('',#2490,1.00000000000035);
#2492=ORIENTED_EDGE('',*,*,#984,.T.);
#2493=ORIENTED_EDGE('',*,*,#912,.T.);
#2494=ORIENTED_EDGE('',*,*,#2482,.F.);
#2495=CARTESIAN_POINT('',(-14.8335456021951,-16.247402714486,22.5735633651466));
#2496=CARTESIAN_POINT('',(-14.7914358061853,-16.203389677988,22.6019554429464));
#2497=CARTESIAN_POINT('',(-14.7533846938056,-16.1555050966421,22.6304131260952));
#2498=CARTESIAN_POINT('',(-14.6863698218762,-16.0532128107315,22.6867066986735));
#2499=CARTESIAN_POINT('',(-14.6574301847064,-15.9987883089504,22.7145407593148));
#2500=CARTESIAN_POINT('',(-14.6098067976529,-15.8848006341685,22.7687147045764));
#2501=CARTESIAN_POINT('',(-14.5911376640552,-15.8252302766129,22.7950524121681));
#2502=CARTESIAN_POINT('',(-14.5651390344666,-15.7026960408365,22.8452338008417));
#2503=CARTESIAN_POINT('',(-14.5577976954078,-15.6397357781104,22.8690800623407));
#2504=CARTESIAN_POINT('',(-14.5553561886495,-15.5157836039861,22.9120865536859));
#2505=CARTESIAN_POINT('',(-14.5596154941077,-15.4548693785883,22.9314304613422));
#2506=CARTESIAN_POINT('',(-14.5795174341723,-15.3337310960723,22.9660776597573));
#2507=CARTESIAN_POINT('',(-14.595153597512,-15.2735066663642,22.9813832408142));
#2508=CARTESIAN_POINT('',(-14.6356102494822,-15.162166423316,23.0057545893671));
#2509=CARTESIAN_POINT('',(-14.6593183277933,-15.1107514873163,23.0153008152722));
#2510=CARTESIAN_POINT('',(-14.7154368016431,-15.0122230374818,23.0299244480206));
#2511=CARTESIAN_POINT('',(-14.7478407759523,-14.9651063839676,23.0350051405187));
#2512=CARTESIAN_POINT('',(-14.8171371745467,-14.8808692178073,23.0401649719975));
#2513=CARTESIAN_POINT('',(-14.8533746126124,-14.843232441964,23.0406485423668));
#2514=CARTESIAN_POINT('',(-14.9311724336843,-14.7741351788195,23.0376433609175));
#2515=CARTESIAN_POINT('',(-14.9727317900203,-14.742673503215,23.0341553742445));
#2516=CARTESIAN_POINT('',(-15.0587090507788,-14.6875017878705,23.0235264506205));
#2517=CARTESIAN_POINT('',(-15.1030224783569,-14.6636089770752,23.0164844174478));
#2518=CARTESIAN_POINT('',(-15.1941749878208,-14.6229025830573,22.9991159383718));
#2519=CARTESIAN_POINT('',(-15.2410144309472,-14.6060900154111,22.9887890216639));
#2520=CARTESIAN_POINT('',(-15.3380152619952,-14.5791223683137,22.9647520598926));
#2521=CARTESIAN_POINT('',(-15.3882329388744,-14.5692840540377,22.9509158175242));
#2522=CARTESIAN_POINT('',(-15.4887851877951,-14.557349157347,22.9206270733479));
#2523=CARTESIAN_POINT('',(-15.5391197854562,-14.5552544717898,22.9041739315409));
#2524=CARTESIAN_POINT('',(-15.6431771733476,-14.558650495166,22.8676285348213));
#2525=CARTESIAN_POINT('',(-15.6968097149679,-14.5648229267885,22.8473436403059));
#2526=CARTESIAN_POINT('',(-15.8017175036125,-14.5854442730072,22.8049087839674));
#2527=CARTESIAN_POINT('',(-15.8529907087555,-14.5999002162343,22.7827572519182));
#2528=CARTESIAN_POINT('',(-15.9569609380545,-14.6382676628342,22.7349564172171));
#2529=CARTESIAN_POINT('',(-16.0093079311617,-14.662964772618,22.7091767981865));
#2530=CARTESIAN_POINT('',(-16.1086190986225,-14.720712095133,22.6568325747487));
#2531=CARTESIAN_POINT('',(-16.1555915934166,-14.7537491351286,22.6302692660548));
#2532=CARTESIAN_POINT('',(-16.2158335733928,-14.8043214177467,22.5936230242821));
#2533=CARTESIAN_POINT('',(-16.2318614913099,-14.8186842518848,22.5835875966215));
#2534=CARTESIAN_POINT('',(-16.247402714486,-14.8335456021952,22.5735633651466));
#2535=B_SPLINE_CURVE_WITH_KNOTS('',3,(#2495,#2496,#2497,#2498,#2499,#2500,#2501,#2502,#2503,
#2504,#2505,#2506,#2507,#2508,#2509,#2510,#2511,#2512,#2513,#2514,#2515,#2516,#2517,#2518,#2519,
#2520,#2521,#2522,#2523,#2524,#2525,#2526,#2527,#2528,#2529,#2530,#2531,#2532,#2533,#2534),
.UNSPECIFIED.,.F.,.F.,(4,2,2,2,2,2,2,2,2,2,2,2,2,2,2,2,2,2,2,4),(0.,0.201422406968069,
0.403373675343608,0.605611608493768,0.807637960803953,0.998738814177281,1.18973105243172,
1.36104276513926,1.53222832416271,1.68819769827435,1.84413702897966,1.99595814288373,
2.14780102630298,2.30616203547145,2.464561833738,2.63686071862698,2.80930601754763,
2.99859361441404,3.18758408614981,3.25877905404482),.UNSPECIFIED.);
#2536=CARTESIAN_POINT('',(-14.8492424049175,-14.8492424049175,23.04));
#2537=VERTEX_POINT('',#2536);
#2538=EDGE_CURVE('E874',#2475,#2537,#2535,.T.);
#2539=ORIENTED_EDGE('',*,*,#2538,.T.);
#2540=CARTESIAN_POINT('',(-16.247202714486,-14.833354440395,22.5736923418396));
#2541=VERTEX_POINT('',#2540);
#2542=EDGE_CURVE('E869',#2537,#2541,#2535,.T.);
#2543=ORIENTED_EDGE('',*,*,#2542,.T.);
#2544=DIRECTION('',(0.,0.,-1.));
#2545=VECTOR('',#2544,1.);
#2546=CARTESIAN_POINT('',(-16.247202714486,-14.833354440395,24.));
#2547=LINE('',#2546,#2545);
#2548=EDGE_CURVE('E892',#2541,#983,#2547,.T.);
#2549=ORIENTED_EDGE('',*,*,#2548,.T.);
#2550=EDGE_LOOP('',(#2492,#2493,#2494,#2539,#2543,#2549));
#2551=FACE_BOUND('',#2550,.T.);
#2552=ADVANCED_FACE('F861',(#2551),#2491,.F.);
#2553=CARTESIAN_POINT('',(8.58167703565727E-12,8.02830024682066E-12,24.));
#2554=DIRECTION('',(0.,0.,-1.));
#2555=DIRECTION('',(-1.,0.,0.));
#2556=AXIS2_PLACEMENT_3D('',#2553,#2554,#2555);
#2557=CYLINDRICAL_SURFACE('',#2556,22.0000000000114);
#2558=ORIENTED_EDGE('',*,*,#993,.T.);
#2559=ORIENTED_EDGE('',*,*,#2548,.F.);
#2560=CARTESIAN_POINT('',(0.,0.,22.5736923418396));
#2561=DIRECTION('',(0.,0.,-1.));
#2562=DIRECTION('',(-1.,0.,0.));
#2563=AXIS2_PLACEMENT_3D('',#2560,#2561,#2562);
#2564=CIRCLE('',#2563,22.0000000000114);
#2565=CARTESIAN_POINT('',(-19.921767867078,-9.3339790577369,22.5736923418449));
#2566=VERTEX_POINT('',#2565);
#2567=EDGE_CURVE('E694',#2541,#2566,#2564,.T.);
#2568=ORIENTED_EDGE('',*,*,#2567,.T.);
#2569=DIRECTION('',(0.,0.,-1.));
#2570=VECTOR('',#2569,1.);
#2571=CARTESIAN_POINT('',(-19.921767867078,-9.3339790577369,24.));
#2572=LINE('',#2571,#2570);
#2573=EDGE_CURVE('E884',#2566,#992,#2572,.T.);
#2574=ORIENTED_EDGE('',*,*,#2573,.T.);
#2575=EDGE_LOOP('',(#2558,#2559,#2568,#2574));
#2576=FACE_BOUND('',#2575,.T.);
#2577=ADVANCED_FACE('F853',(#2576),#2557,.T.);
#2578=CARTESIAN_POINT('',(-20.3253497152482,-8.41903551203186,24.));
#2579=DIRECTION('',(0.,0.,-1.));
#2580=DIRECTION('',(-1.,0.,0.));
#2581=AXIS2_PLACEMENT_3D('',#2578,#2579,#2580);
#2582=CYLINDRICAL_SURFACE('',#2581,0.999999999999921);
#2583=ORIENTED_EDGE('',*,*,#1255,.T.);
#2584=ORIENTED_EDGE('',*,*,#1038,.T.);
#2585=ORIENTED_EDGE('',*,*,#2573,.F.);
#2586=CARTESIAN_POINT('',(-19.9222215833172,-9.3341790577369,22.5734611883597));
#2587=CARTESIAN_POINT('',(-19.8664672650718,-9.30964258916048,22.6018538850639));
#2588=CARTESIAN_POINT('',(-19.8129803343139,-9.27997543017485,22.6303126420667));
#2589=CARTESIAN_POINT('',(-19.7119044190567,-9.21113560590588,22.686609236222));
#2590=CARTESIAN_POINT('',(-19.6643312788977,-9.171938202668,22.71444524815));
#2591=CARTESIAN_POINT('',(-19.5766923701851,-9.08486965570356,22.768624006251));
#2592=CARTESIAN_POINT('',(-19.5366373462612,-9.03698628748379,22.7949645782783));
#2593=CARTESIAN_POINT('',(-19.4657037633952,-8.93374305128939,22.8451526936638));
#2594=CARTESIAN_POINT('',(-19.4348156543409,-8.87839105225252,22.8690028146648));
#2595=CARTESIAN_POINT('',(-19.3851008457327,-8.76481700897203,22.9120184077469));
#2596=CARTESIAN_POINT('',(-19.3657124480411,-8.70691181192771,22.931367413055));
#2597=CARTESIAN_POINT('',(-19.3377165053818,-8.58738031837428,22.9660253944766));
#2598=CARTESIAN_POINT('',(-19.3291028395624,-8.52575615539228,22.9813366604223));
#2599=CARTESIAN_POINT('',(-19.3238482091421,-8.40740529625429,23.0057192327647));
#2600=CARTESIAN_POINT('',(-19.3260650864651,-8.35082820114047,23.0152709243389));
#2601=CARTESIAN_POINT('',(-19.3401859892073,-8.23831565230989,23.0299053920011));
#2602=CARTESIAN_POINT('',(-19.3520828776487,-8.18237975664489,23.0349914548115));
#2603=CARTESIAN_POINT('',(-19.3838508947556,-8.07802564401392,23.0401610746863));
#2604=CARTESIAN_POINT('',(-19.4029189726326,-8.02938120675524,23.0406492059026));
#2605=CARTESIAN_POINT('',(-19.4483378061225,-7.93576018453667,23.0376527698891));
#2606=CARTESIAN_POINT('',(-19.4746871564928,-7.89078289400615,23.0341689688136));
#2607=CARTESIAN_POINT('',(-19.5329937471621,-7.80689701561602,23.0235479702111));
#2608=CARTESIAN_POINT('',(-19.56478422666,-7.76785937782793,23.0165098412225));
#2609=CARTESIAN_POINT('',(-19.6334088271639,-7.69535702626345,22.9991487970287));
#2610=CARTESIAN_POINT('',(-19.6702436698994,-7.66189311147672,22.9888254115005));
#2611=CARTESIAN_POINT('',(-19.749529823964,-7.5998448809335,22.9647955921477));
#2612=CARTESIAN_POINT('',(-19.7921542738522,-7.57153143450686,22.9509630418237));
#2613=CARTESIAN_POINT('',(-19.8804748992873,-7.52201140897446,22.9206812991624));
#2614=CARTESIAN_POINT('',(-19.9261718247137,-7.50080657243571,22.9042314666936));
#2615=CARTESIAN_POINT('',(-20.0235987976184,-7.46410726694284,22.8676928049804));
#2616=CARTESIAN_POINT('',(-20.075506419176,-7.44927698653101,22.8474113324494));
#2617=CARTESIAN_POINT('',(-20.1803123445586,-7.42816422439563,22.8049828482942));
#2618=CARTESIAN_POINT('',(-20.23321145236,-7.42188901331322,22.7828342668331));
#2619=CARTESIAN_POINT('',(-20.343944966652,-7.41752793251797,22.7350389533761));
#2620=CARTESIAN_POINT('',(-20.4017567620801,-7.42030180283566,22.7092618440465));
#2621=CARTESIAN_POINT('',(-20.5156056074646,-7.43562621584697,22.6569219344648));
#2622=CARTESIAN_POINT('',(-20.5716452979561,-7.44816142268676,22.6303604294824));
#2623=CARTESIAN_POINT('',(-20.6467005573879,-7.47182855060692,22.5936944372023));
#2624=CARTESIAN_POINT('',(-20.6670487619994,-7.47897691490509,22.5836377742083));
#2625=CARTESIAN_POINT('',(-20.687137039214,-7.48677485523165,22.5735923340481));
#2626=B_SPLINE_CURVE_WITH_KNOTS('',3,(#2586,#2587,#2588,#2589,#2590,#2591,#2592,#2593,#2594,
#2595,#2596,#2597,#2598,#2599,#2600,#2601,#2602,#2603,#2604,#2605,#2606,#2607,#2608,#2609,#2610,
#2611,#2612,#2613,#2614,#2615,#2616,#2617,#2618,#2619,#2620,#2621,#2622,#2623,#2624,#2625),
.UNSPECIFIED.,.F.,.F.,(4,2,2,2,2,2,2,2,2,2,2,2,2,2,2,2,2,2,2,4),(0.,0.201427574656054,
0.40338369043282,0.605626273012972,0.807657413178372,0.998768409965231,1.18977079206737,
1.36109333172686,1.53228967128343,1.68826466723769,1.84420958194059,1.99602979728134,
2.14787175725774,2.30622670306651,2.46462043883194,2.63691028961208,2.80934647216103,
2.998624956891,3.18760666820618,3.25895217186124),.UNSPECIFIED.);
#2627=CARTESIAN_POINT('',(-19.4014701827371,-8.0363520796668,23.04));
#2628=VERTEX_POINT('',#2627);
#2629=EDGE_CURVE('E834',#2566,#2628,#2626,.T.);
#2630=ORIENTED_EDGE('',*,*,#2629,.T.);
#2631=CARTESIAN_POINT('',(-20.686937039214,-7.4866972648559,22.573692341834));
#2632=VERTEX_POINT('',#2631);
#2633=EDGE_CURVE('E833',#2628,#2632,#2626,.T.);
#2634=ORIENTED_EDGE('',*,*,#2633,.T.);
#2635=DIRECTION('',(0.,0.,-1.));
#2636=VECTOR('',#2635,1.);
#2637=CARTESIAN_POINT('',(-20.686937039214,-7.4866972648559,24.));
#2638=LINE('',#2637,#2636);
#2639=EDGE_CURVE('E899',#2632,#1254,#2638,.T.);
#2640=ORIENTED_EDGE('',*,*,#2639,.T.);
#2641=EDGE_LOOP('',(#2583,#2584,#2585,#2630,#2634,#2640));
#2642=FACE_BOUND('',#2641,.T.);
#2643=ADVANCED_FACE('F849',(#2642),#2582,.F.);
#2644=CARTESIAN_POINT('',(2.30839652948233E-11,5.14432246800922E-12,24.));
#2645=DIRECTION('',(0.,0.,-1.));
#2646=DIRECTION('',(-1.,0.,0.));
#2647=AXIS2_PLACEMENT_3D('',#2644,#2645,#2646);
#2648=CYLINDRICAL_SURFACE('',#2647,22.0000000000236);
#2649=ORIENTED_EDGE('',*,*,#1264,.T.);
#2650=ORIENTED_EDGE('',*,*,#2639,.F.);
#2651=CARTESIAN_POINT('',(0.,0.,22.573692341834));
#2652=DIRECTION('',(0.,0.,-1.));
#2653=DIRECTION('',(-1.,0.,0.));
#2654=AXIS2_PLACEMENT_3D('',#2651,#2652,#2653);
#2655=CIRCLE('',#2654,22.0000000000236);
#2656=CARTESIAN_POINT('',(-21.977272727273,-0.99974170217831,22.5736923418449));
#2657=VERTEX_POINT('',#2656);
#2658=EDGE_CURVE('E692',#2632,#2657,#2655,.T.);
#2659=ORIENTED_EDGE('',*,*,#2658,.T.);
#2660=DIRECTION('',(0.,0.,-1.));
#2661=VECTOR('',#2660,1.);
#2662=CARTESIAN_POINT('',(-21.977272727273,-0.99974170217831,24.));
#2663=LINE('',#2662,#2661);
#2664=EDGE_CURVE('E332',#2657,#1263,#2663,.T.);
#2665=ORIENTED_EDGE('',*,*,#2664,.T.);
#2666=EDGE_LOOP('',(#2649,#2650,#2659,#2665));
#2667=FACE_BOUND('',#2666,.T.);
#2668=ADVANCED_FACE('F845',(#2667),#2648,.T.);
#2669=CARTESIAN_POINT('',(-22.,0.,24.));
#2670=DIRECTION('',(0.,0.,-1.));
#2671=DIRECTION('',(-1.,0.,0.));
#2672=AXIS2_PLACEMENT_3D('',#2669,#2670,#2671);
#2673=CYLINDRICAL_SURFACE('',#2672,1.);
#2674=ORIENTED_EDGE('',*,*,#970,.T.);
#2675=ORIENTED_EDGE('',*,*,#1266,.T.);
#2676=ORIENTED_EDGE('',*,*,#2664,.F.);
#2677=CARTESIAN_POINT('',(-21.977472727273,-0.999746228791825,22.5735990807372));
#2678=CARTESIAN_POINT('',(-21.9165753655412,-0.998395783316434,22.6019909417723));
#2679=CARTESIAN_POINT('',(-21.8558106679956,-0.991437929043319,22.6304482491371));
#2680=CARTESIAN_POINT('',(-21.7360950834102,-0.966484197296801,22.6867407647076));
#2681=CARTESIAN_POINT('',(-21.6771493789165,-0.948459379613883,22.7145741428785));
#2682=CARTESIAN_POINT('',(-21.5628770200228,-0.901524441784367,22.7687464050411));
#2683=CARTESIAN_POINT('',(-21.5075556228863,-0.872598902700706,22.795083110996));
#2684=CARTESIAN_POINT('',(-21.4025322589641,-0.804330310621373,22.8452621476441));
#2685=CARTESIAN_POINT('',(-21.3528244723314,-0.764998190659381,22.8691070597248));
#2686=CARTESIAN_POINT('',(-21.2634574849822,-0.679071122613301,22.9121103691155));
#2687=CARTESIAN_POINT('',(-21.2234001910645,-0.632984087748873,22.9314524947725));
#2688=CARTESIAN_POINT('',(-21.1518232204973,-0.53324961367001,22.9660959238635));
#2689=CARTESIAN_POINT('',(-21.1202987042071,-0.479606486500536,22.9813995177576));
#2690=CARTESIAN_POINT('',(-21.0701845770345,-0.372267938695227,23.0057669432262));
#2691=CARTESIAN_POINT('',(-21.0505968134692,-0.319147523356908,23.0153112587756));
#2692=CARTESIAN_POINT('',(-21.0206162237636,-0.2097956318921,23.0299311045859));
#2693=CARTESIAN_POINT('',(-21.0102166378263,-0.15356647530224,23.0350099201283));
#2694=CARTESIAN_POINT('',(-20.9996589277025,-0.0450029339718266,23.0401663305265));
#2695=CARTESIAN_POINT('',(-20.9986727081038,0.00723343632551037,23.0406483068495));
#2696=CARTESIAN_POINT('',(-21.0048311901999,0.111102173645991,23.0376400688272));
#2697=CARTESIAN_POINT('',(-21.0119743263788,0.162734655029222,23.0341506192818));
#2698=CARTESIAN_POINT('',(-21.0337628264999,0.262539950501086,23.0235189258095));
#2699=CARTESIAN_POINT('',(-21.0482051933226,0.310768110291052,23.0164755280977));
#2700=CARTESIAN_POINT('',(-21.083881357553,0.404004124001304,22.9991044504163));
#2701=CARTESIAN_POINT('',(-21.1051161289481,0.449011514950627,22.9887762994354));
#2702=CARTESIAN_POINT('',(-21.1546422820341,0.536667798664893,22.9647368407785));
#2703=CARTESIAN_POINT('',(-21.1831975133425,0.579132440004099,22.9508993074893));
#2704=CARTESIAN_POINT('',(-21.2458646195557,0.658669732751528,22.9206081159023));
#2705=CARTESIAN_POINT('',(-21.2799778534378,0.695741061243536,22.9041538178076));
#2706=CARTESIAN_POINT('',(-21.3559639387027,0.766915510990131,22.8676060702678));
#2707=CARTESIAN_POINT('',(-21.39825502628,0.800472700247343,22.8473199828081));
#2708=CARTESIAN_POINT('',(-21.4870224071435,0.860067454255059,22.8048828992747));
#2709=CARTESIAN_POINT('',(-21.533502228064,0.886098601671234,22.7827303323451));
#2710=CARTESIAN_POINT('',(-21.6341545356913,0.932480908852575,22.7349275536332));
#2711=CARTESIAN_POINT('',(-21.6886349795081,0.952029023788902,22.7091470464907));
#2712=CARTESIAN_POINT('',(-21.799695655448,0.981412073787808,22.6568013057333));
#2713=CARTESIAN_POINT('',(-21.8562724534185,0.991262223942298,22.6302373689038));
#2714=CARTESIAN_POINT('',(-21.9345827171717,0.99809012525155,22.5936133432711));
#2715=CARTESIAN_POINT('',(-21.9560235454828,0.999264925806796,22.5836006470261));
#2716=CARTESIAN_POINT('',(-21.977472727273,0.999746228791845,22.5735990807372));
#2717=B_SPLINE_CURVE_WITH_KNOTS('',3,(#2677,#2678,#2679,#2680,#2681,#2682,#2683,#2684,#2685,
#2686,#2687,#2688,#2689,#2690,#2691,#2692,#2693,#2694,#2695,#2696,#2697,#2698,#2699,#2700,#2701,
#2702,#2703,#2704,#2705,#2706,#2707,#2708,#2709,#2710,#2711,#2712,#2713,#2714,#2715,#2716),
.UNSPECIFIED.,.F.,.F.,(4,2,2,2,2,2,2,2,2,2,2,2,2,2,2,2,2,2,2,4),(0.,0.20142059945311,
0.40337017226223,0.605606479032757,0.807631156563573,0.998728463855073,1.18971715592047,
1.36102508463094,1.53220687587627,1.6881742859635,1.84411166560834,1.99593309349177,
2.14777630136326,2.30613943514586,2.4645413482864,2.63684336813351,2.80929187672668,
2.99858276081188,3.18757619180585,3.25861009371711),.UNSPECIFIED.);
#2718=CARTESIAN_POINT('',(-21.,0.,23.04));
#2719=VERTEX_POINT('',#2718);
#2720=EDGE_CURVE('E36',#2657,#2719,#2717,.T.);
#2721=ORIENTED_EDGE('',*,*,#2720,.T.);
#2722=EDGE_CURVE('E316',#2719,#1283,#2717,.T.);
#2723=ORIENTED_EDGE('',*,*,#2722,.T.);
#2724=ORIENTED_EDGE('',*,*,#1284,.T.);
#2725=EDGE_LOOP('',(#2674,#2675,#2676,#2721,#2723,#2724));
#2726=FACE_BOUND('',#2725,.T.);
#2727=ADVANCED_FACE('F318',(#2726),#2673,.F.);
#2728=CARTESIAN_POINT('',(0.,7.7272727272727,22.4));
#2729=DIRECTION('',(0.,0.,1.));
#2730=DIRECTION('',(1.,0.,0.));
#2731=AXIS2_PLACEMENT_3D('',#2728,#2729,#2730);
#2732=PLANE('',#2731);
#2733=CARTESIAN_POINT('',(0.,0.,22.4));
#2734=DIRECTION('',(0.,0.,-1.));
#2735=DIRECTION('',(-1.,0.,0.));
#2736=AXIS2_PLACEMENT_3D('',#2733,#2734,#2735);
#2737=CIRCLE('',#2736,7.7272727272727);
#2738=CARTESIAN_POINT('',(-7.7272727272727,0.,22.4));
#2739=VERTEX_POINT('',#2738);
#2740=EDGE_CURVE('E795',#2739,#2739,#2737,.T.);
#2741=ORIENTED_EDGE('',*,*,#2740,.F.);
#2742=EDGE_LOOP('',(#2741));
#2743=FACE_BOUND('',#2742,.T.);
#2744=ADVANCED_FACE('F377',(#2743),#2732,.T.);
#2745=CARTESIAN_POINT('',(0.,0.,24.));
#2746=DIRECTION('',(0.,0.,1.));
#2747=DIRECTION('',(1.,0.,0.));
#2748=AXIS2_PLACEMENT_3D('',#2745,#2746,#2747);
#2749=CONICAL_SURFACE('',#2748,9.3272727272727,0.785398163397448);
#2750=ORIENTED_EDGE('',*,*,#2740,.T.);
#2751=EDGE_LOOP('',(#2750));
#2752=FACE_BOUND('',#2751,.T.);
#2753=CARTESIAN_POINT('',(0.,0.,24.));
#2754=DIRECTION('',(0.,0.,-1.));
#2755=DIRECTION('',(-1.,0.,0.));
#2756=AXIS2_PLACEMENT_3D('',#2753,#2754,#2755);
#2757=CIRCLE('',#2756,9.3272727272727);
#2758=CARTESIAN_POINT('',(-9.3272727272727,0.,24.));
#2759=VERTEX_POINT('',#2758);
#2760=EDGE_CURVE('E792',#2759,#2759,#2757,.T.);
#2761=ORIENTED_EDGE('',*,*,#2760,.F.);
#2762=EDGE_LOOP('',(#2761));
#2763=FACE_BOUND('',#2762,.T.);
#2764=ADVANCED_FACE('F381',(#2752,#2763),#2749,.F.);
#2765=CARTESIAN_POINT('',(0.,19.5,24.));
#2766=DIRECTION('',(0.,0.,1.));
#2767=DIRECTION('',(1.,0.,0.));
#2768=AXIS2_PLACEMENT_3D('',#2765,#2766,#2767);
#2769=PLANE('',#2768);
#2770=ORIENTED_EDGE('',*,*,#2760,.T.);
#2771=EDGE_LOOP('',(#2770));
#2772=FACE_BOUND('',#2771,.T.);
#2773=CARTESIAN_POINT('',(0.,0.,24.));
#2774=DIRECTION('',(0.,0.,-1.));
#2775=DIRECTION('',(-1.,0.,0.));
#2776=AXIS2_PLACEMENT_3D('',#2773,#2774,#2775);
#2777=CIRCLE('',#2776,19.499999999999);
#2778=CARTESIAN_POINT('',(-19.499999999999,0.,24.));
#2779=VERTEX_POINT('',#2778);
#2780=EDGE_CURVE('E787',#2779,#2779,#2777,.T.);
#2781=ORIENTED_EDGE('',*,*,#2780,.F.);
#2782=EDGE_LOOP('',(#2781));
#2783=FACE_BOUND('',#2782,.T.);
#2784=ADVANCED_FACE('F385',(#2772,#2783),#2769,.T.);
#2785=CARTESIAN_POINT('',(0.,0.,23.499999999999));
#2786=DIRECTION('',(0.,0.,-1.));
#2787=DIRECTION('',(-1.,0.,0.));
#2788=AXIS2_PLACEMENT_3D('',#2785,#2786,#2787);
#2789=TOROIDAL_SURFACE('',#2788,19.499999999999,0.500000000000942);
#2790=ORIENTED_EDGE('',*,*,#2780,.T.);
#2791=EDGE_LOOP('',(#2790));
#2792=FACE_BOUND('',#2791,.T.);
#2793=CARTESIAN_POINT('',(0.,0.,23.5));
#2794=DIRECTION('',(0.,0.,-1.));
#2795=DIRECTION('',(-1.,0.,0.));
#2796=AXIS2_PLACEMENT_3D('',#2793,#2794,#2795);
#2797=CIRCLE('',#2796,20.);
#2798=CARTESIAN_POINT('',(-20.,0.,23.5));
#2799=VERTEX_POINT('',#2798);
#2800=EDGE_CURVE('E784',#2799,#2799,#2797,.T.);
#2801=ORIENTED_EDGE('',*,*,#2800,.F.);
#2802=EDGE_LOOP('',(#2801));
#2803=FACE_BOUND('',#2802,.T.);
#2804=ADVANCED_FACE('F389',(#2792,#2803),#2789,.T.);
#2805=CARTESIAN_POINT('',(0.,0.,24.));
#2806=DIRECTION('',(0.,0.,-1.));
#2807=DIRECTION('',(-1.,0.,0.));
#2808=AXIS2_PLACEMENT_3D('',#2805,#2806,#2807);
#2809=CYLINDRICAL_SURFACE('',#2808,20.);
#2810=ORIENTED_EDGE('',*,*,#2800,.T.);
#2811=EDGE_LOOP('',(#2810));
#2812=FACE_BOUND('',#2811,.T.);
#2813=CARTESIAN_POINT('',(0.,0.,23.04));
#2814=DIRECTION('',(0.,0.,-1.));
#2815=DIRECTION('',(-1.,0.,0.));
#2816=AXIS2_PLACEMENT_3D('',#2813,#2814,#2815);
#2817=CIRCLE('',#2816,20.);
#2818=CARTESIAN_POINT('',(-20.,0.,23.04));
#2819=VERTEX_POINT('',#2818);
#2820=EDGE_CURVE('E779',#2819,#2819,#2817,.T.);
#2821=ORIENTED_EDGE('',*,*,#2820,.F.);
#2822=EDGE_LOOP('',(#2821));
#2823=FACE_BOUND('',#2822,.T.);
#2824=ADVANCED_FACE('F393',(#2812,#2823),#2809,.T.);
#2825=CARTESIAN_POINT('',(0.,0.,22.10738468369));
#2826=DIRECTION('',(0.,0.,-1.));
#2827=DIRECTION('',(-1.,0.,0.));
#2828=AXIS2_PLACEMENT_3D('',#2825,#2826,#2827);
#2829=CONICAL_SURFACE('',#2828,23.,1.13446401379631);
#2830=ORIENTED_EDGE('',*,*,#1359,.F.);
#2831=CARTESIAN_POINT('',(0.,0.,23.04));
#2832=DIRECTION('',(0.,0.,-1.));
#2833=DIRECTION('',(-1.,0.,0.));
#2834=AXIS2_PLACEMENT_3D('',#2831,#2832,#2833);
#2835=CIRCLE('',#2834,21.);
#2836=EDGE_CURVE('E730',#1354,#1445,#2835,.T.);
#2837=ORIENTED_EDGE('',*,*,#2836,.T.);
#2838=ORIENTED_EDGE('',*,*,#1446,.F.);
#2839=ORIENTED_EDGE('',*,*,#1384,.F.);
#2840=EDGE_LOOP('',(#2830,#2837,#2838,#2839));
#2841=FACE_BOUND('',#2840,.T.);
#2842=ADVANCED_FACE('F396',(#2841),#2829,.T.);
#2843=ORIENTED_EDGE('',*,*,#1450,.F.);
#2844=EDGE_CURVE('E777',#1445,#1536,#2835,.T.);
#2845=ORIENTED_EDGE('',*,*,#2844,.T.);
#2846=ORIENTED_EDGE('',*,*,#1537,.F.);
#2847=ORIENTED_EDGE('',*,*,#1475,.F.);
#2848=EDGE_LOOP('',(#2843,#2845,#2846,#2847));
#2849=FACE_BOUND('',#2848,.T.);
#2850=ADVANCED_FACE('F970',(#2849),#2829,.T.);
#2851=ORIENTED_EDGE('',*,*,#1541,.F.);
#2852=EDGE_CURVE('E1267',#1536,#1627,#2835,.T.);
#2853=ORIENTED_EDGE('',*,*,#2852,.T.);
#2854=ORIENTED_EDGE('',*,*,#1628,.F.);
#2855=ORIENTED_EDGE('',*,*,#1566,.F.);
#2856=EDGE_LOOP('',(#2851,#2853,#2854,#2855));
#2857=FACE_BOUND('',#2856,.T.);
#2858=ADVANCED_FACE('F1274',(#2857),#2829,.T.);
#2859=ORIENTED_EDGE('',*,*,#1632,.F.);
#2860=EDGE_CURVE('E1263',#1627,#1718,#2835,.T.);
#2861=ORIENTED_EDGE('',*,*,#2860,.T.);
#2862=ORIENTED_EDGE('',*,*,#1719,.F.);
#2863=ORIENTED_EDGE('',*,*,#1657,.F.);
#2864=EDGE_LOOP('',(#2859,#2861,#2862,#2863));
#2865=FACE_BOUND('',#2864,.T.);
#2866=ADVANCED_FACE('F1468',(#2865),#2829,.T.);
#2867=ORIENTED_EDGE('',*,*,#1723,.F.);
#2868=EDGE_CURVE('E1258',#1718,#1809,#2835,.T.);
#2869=ORIENTED_EDGE('',*,*,#2868,.T.);
#2870=ORIENTED_EDGE('',*,*,#1810,.F.);
#2871=ORIENTED_EDGE('',*,*,#1748,.F.);
#2872=EDGE_LOOP('',(#2867,#2869,#2870,#2871));
#2873=FACE_BOUND('',#2872,.T.);
#2874=ADVANCED_FACE('F1475',(#2873),#2829,.T.);
#2875=ORIENTED_EDGE('',*,*,#1814,.F.);
#2876=EDGE_CURVE('E1255',#1809,#1900,#2835,.T.);
#2877=ORIENTED_EDGE('',*,*,#2876,.T.);
#2878=ORIENTED_EDGE('',*,*,#1901,.F.);
#2879=ORIENTED_EDGE('',*,*,#1839,.F.);
#2880=EDGE_LOOP('',(#2875,#2877,#2878,#2879));
#2881=FACE_BOUND('',#2880,.T.);
#2882=ADVANCED_FACE('F1482',(#2881),#2829,.T.);
#2883=ORIENTED_EDGE('',*,*,#1905,.F.);
#2884=EDGE_CURVE('E1254',#1900,#1991,#2835,.T.);
#2885=ORIENTED_EDGE('',*,*,#2884,.T.);
#2886=ORIENTED_EDGE('',*,*,#1992,.F.);
#2887=ORIENTED_EDGE('',*,*,#1930,.F.);
#2888=EDGE_LOOP('',(#2883,#2885,#2886,#2887));
#2889=FACE_BOUND('',#2888,.T.);
#2890=ADVANCED_FACE('F1244',(#2889),#2829,.T.);
#2891=ORIENTED_EDGE('',*,*,#1996,.F.);
#2892=EDGE_CURVE('E1250',#1991,#2082,#2835,.T.);
#2893=ORIENTED_EDGE('',*,*,#2892,.T.);
#2894=ORIENTED_EDGE('',*,*,#2083,.F.);
#2895=ORIENTED_EDGE('',*,*,#2021,.F.);
#2896=EDGE_LOOP('',(#2891,#2893,#2894,#2895));
#2897=FACE_BOUND('',#2896,.T.);
#2898=ADVANCED_FACE('F1238',(#2897),#2829,.T.);
#2899=ORIENTED_EDGE('',*,*,#2087,.F.);
#2900=EDGE_CURVE('E1214',#2082,#2173,#2835,.T.);
#2901=ORIENTED_EDGE('',*,*,#2900,.T.);
#2902=ORIENTED_EDGE('',*,*,#2174,.F.);
#2903=ORIENTED_EDGE('',*,*,#2112,.F.);
#2904=EDGE_LOOP('',(#2899,#2901,#2902,#2903));
#2905=FACE_BOUND('',#2904,.T.);
#2906=ADVANCED_FACE('F1233',(#2905),#2829,.T.);
#2907=ORIENTED_EDGE('',*,*,#2178,.F.);
#2908=EDGE_CURVE('E1202',#2173,#2264,#2835,.T.);
#2909=ORIENTED_EDGE('',*,*,#2908,.T.);
#2910=ORIENTED_EDGE('',*,*,#2265,.F.);
#2911=ORIENTED_EDGE('',*,*,#2203,.F.);
#2912=EDGE_LOOP('',(#2907,#2909,#2910,#2911));
#2913=FACE_BOUND('',#2912,.T.);
#2914=ADVANCED_FACE('F1199',(#2913),#2829,.T.);
#2915=ORIENTED_EDGE('',*,*,#2269,.F.);
#2916=EDGE_CURVE('E1208',#2264,#2355,#2835,.T.);
#2917=ORIENTED_EDGE('',*,*,#2916,.T.);
#2918=ORIENTED_EDGE('',*,*,#2356,.F.);
#2919=ORIENTED_EDGE('',*,*,#2294,.F.);
#2920=EDGE_LOOP('',(#2915,#2917,#2918,#2919));
#2921=FACE_BOUND('',#2920,.T.);
#2922=ADVANCED_FACE('F1207',(#2921),#2829,.T.);
#2923=ORIENTED_EDGE('',*,*,#2360,.F.);
#2924=EDGE_CURVE('E1213',#2355,#2446,#2835,.T.);
#2925=ORIENTED_EDGE('',*,*,#2924,.T.);
#2926=ORIENTED_EDGE('',*,*,#2447,.F.);
#2927=ORIENTED_EDGE('',*,*,#2385,.F.);
#2928=EDGE_LOOP('',(#2923,#2925,#2926,#2927));
#2929=FACE_BOUND('',#2928,.T.);
#2930=ADVANCED_FACE('F1219',(#2929),#2829,.T.);
#2931=ORIENTED_EDGE('',*,*,#2451,.F.);
#2932=EDGE_CURVE('E783',#2446,#2537,#2835,.T.);
#2933=ORIENTED_EDGE('',*,*,#2932,.T.);
#2934=ORIENTED_EDGE('',*,*,#2538,.F.);
#2935=ORIENTED_EDGE('',*,*,#2476,.F.);
#2936=EDGE_LOOP('',(#2931,#2933,#2934,#2935));
#2937=FACE_BOUND('',#2936,.T.);
#2938=ADVANCED_FACE('F1217',(#2937),#2829,.T.);
#2939=ORIENTED_EDGE('',*,*,#2542,.F.);
#2940=EDGE_CURVE('E778',#2537,#2628,#2835,.T.);
#2941=ORIENTED_EDGE('',*,*,#2940,.T.);
#2942=ORIENTED_EDGE('',*,*,#2629,.F.);
#2943=ORIENTED_EDGE('',*,*,#2567,.F.);
#2944=EDGE_LOOP('',(#2939,#2941,#2942,#2943));
#2945=FACE_BOUND('',#2944,.T.);
#2946=ADVANCED_FACE('F408',(#2945),#2829,.T.);
#2947=ORIENTED_EDGE('',*,*,#2633,.F.);
#2948=EDGE_CURVE('E776',#2628,#2719,#2835,.T.);
#2949=ORIENTED_EDGE('',*,*,#2948,.T.);
#2950=ORIENTED_EDGE('',*,*,#2720,.F.);
#2951=ORIENTED_EDGE('',*,*,#2658,.F.);
#2952=EDGE_LOOP('',(#2947,#2949,#2950,#2951));
#2953=FACE_BOUND('',#2952,.T.);
#2954=ADVANCED_FACE('F368',(#2953),#2829,.T.);
#2955=CARTESIAN_POINT('',(0.,21.,23.04));
#2956=DIRECTION('',(0.,0.,1.));
#2957=DIRECTION('',(1.,0.,0.));
#2958=AXIS2_PLACEMENT_3D('',#2955,#2956,#2957);
#2959=PLANE('',#2958);
#2960=ORIENTED_EDGE('',*,*,#2820,.T.);
#2961=EDGE_LOOP('',(#2960));
#2962=FACE_BOUND('',#2961,.T.);
#2963=EDGE_CURVE('E339',#2719,#1354,#2835,.T.);
#2964=ORIENTED_EDGE('',*,*,#2963,.F.);
#2965=ORIENTED_EDGE('',*,*,#2948,.F.);
#2966=ORIENTED_EDGE('',*,*,#2940,.F.);
#2967=ORIENTED_EDGE('',*,*,#2932,.F.);
#2968=ORIENTED_EDGE('',*,*,#2924,.F.);
#2969=ORIENTED_EDGE('',*,*,#2916,.F.);
#2970=ORIENTED_EDGE('',*,*,#2908,.F.);
#2971=ORIENTED_EDGE('',*,*,#2900,.F.);
#2972=ORIENTED_EDGE('',*,*,#2892,.F.);
#2973=ORIENTED_EDGE('',*,*,#2884,.F.);
#2974=ORIENTED_EDGE('',*,*,#2876,.F.);
#2975=ORIENTED_EDGE('',*,*,#2868,.F.);
#2976=ORIENTED_EDGE('',*,*,#2860,.F.);
#2977=ORIENTED_EDGE('',*,*,#2852,.F.);
#2978=ORIENTED_EDGE('',*,*,#2844,.F.);
#2979=ORIENTED_EDGE('',*,*,#2836,.F.);
#2980=EDGE_LOOP('',(#2964,#2965,#2966,#2967,#2968,#2969,#2970,#2971,#2972,#2973,#2974,#2975,
#2976,#2977,#2978,#2979));
#2981=FACE_BOUND('',#2980,.T.);
#2982=ADVANCED_FACE('F398',(#2962,#2981),#2959,.T.);
#2983=ORIENTED_EDGE('',*,*,#1293,.F.);
#2984=ORIENTED_EDGE('',*,*,#2722,.F.);
#2985=ORIENTED_EDGE('',*,*,#2963,.T.);
#2986=ORIENTED_EDGE('',*,*,#1355,.F.);
#2987=EDGE_LOOP('',(#2983,#2984,#2985,#2986));
#2988=FACE_BOUND('',#2987,.T.);
#2989=ADVANCED_FACE('F336',(#2988),#2829,.T.);
#2990=CARTESIAN_POINT('',(0.,0.,-15.556349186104));
#2991=DIRECTION('',(0.,0.,1.));
#2992=DIRECTION('',(1.,0.,0.));
#2993=AXIS2_PLACEMENT_3D('',#2990,#2991,#2992);
#2994=CYLINDRICAL_SURFACE('',#2993,5.5);
#2995=ORIENTED_EDGE('',*,*,#42,.T.);
#2996=EDGE_LOOP('',(#2995));
#2997=FACE_BOUND('',#2996,.T.);
#2998=CARTESIAN_POINT('',(0.,0.,0.));
#2999=DIRECTION('',(0.,0.,-1.));
#3000=DIRECTION('',(-1.,0.,0.));
#3001=AXIS2_PLACEMENT_3D('',#2998,#2999,#3000);
#3002=CIRCLE('',#3001,5.5);
#3003=CARTESIAN_POINT('',(-5.5,0.,0.));
#3004=VERTEX_POINT('',#3003);
#3005=EDGE_CURVE('E333',#3004,#3004,#3002,.T.);
#3006=ORIENTED_EDGE('',*,*,#3005,.F.);
#3007=EDGE_LOOP('',(#3006));
#3008=FACE_BOUND('',#3007,.T.);
#3009=ADVANCED_FACE('F407',(#2997,#3008),#2994,.T.);
#3010=CARTESIAN_POINT('',(0.,0.,0.));
#3011=DIRECTION('',(0.,0.,-1.));
#3012=DIRECTION('',(-1.,0.,0.));
#3013=AXIS2_PLACEMENT_3D('',#3010,#3011,#3012);
#3014=PLANE('',#3013);
#3015=CARTESIAN_POINT('',(0.,0.,0.));
#3016=DIRECTION('',(0.,0.,-1.));
#3017=DIRECTION('',(-1.,0.,0.));
#3018=AXIS2_PLACEMENT_3D('',#3015,#3016,#3017);
#3019=CIRCLE('',#3018,4.);
#3020=CARTESIAN_POINT('',(-4.,0.,0.));
#3021=VERTEX_POINT('',#3020);
#3022=EDGE_CURVE('E2561',#3021,#3021,#3019,.T.);
#3023=ORIENTED_EDGE('',*,*,#3022,.F.);
#3024=EDGE_LOOP('',(#3023));
#3025=FACE_BOUND('',#3024,.T.);
#3026=ORIENTED_EDGE('',*,*,#3005,.T.);
#3027=EDGE_LOOP('',(#3026));
#3028=FACE_BOUND('',#3027,.T.);
#3029=ADVANCED_FACE('F16',(#3025,#3028),#3014,.T.);
#3030=CARTESIAN_POINT('',(0.,0.,13.));
#3031=DIRECTION('',(0.,0.,-1.));
#3032=DIRECTION('',(-1.,0.,0.));
#3033=AXIS2_PLACEMENT_3D('',#3030,#3031,#3032);
#3034=CYLINDRICAL_SURFACE('',#3033,4.);
#3035=CARTESIAN_POINT('',(0.,0.,13.));
#3036=DIRECTION('',(0.,0.,-1.));
#3037=DIRECTION('',(-1.,0.,0.));
#3038=AXIS2_PLACEMENT_3D('',#3035,#3036,#3037);
#3039=CIRCLE('',#3038,4.);
#3040=CARTESIAN_POINT('',(-4.,0.,13.));
#3041=VERTEX_POINT('',#3040);
#3042=EDGE_CURVE('E2559',#3041,#3041,#3039,.T.);
#3043=ORIENTED_EDGE('',*,*,#3042,.F.);
#3044=EDGE_LOOP('',(#3043));
#3045=FACE_BOUND('',#3044,.T.);
#3046=ORIENTED_EDGE('',*,*,#3022,.T.);
#3047=EDGE_LOOP('',(#3046));
#3048=FACE_BOUND('',#3047,.T.);
#3049=ADVANCED_FACE('F2026',(#3045,#3048),#3034,.F.);
#3050=CARTESIAN_POINT('',(0.,0.,13.));
#3051=DIRECTION('',(0.,0.,-1.));
#3052=DIRECTION('',(-1.,0.,0.));
#3053=AXIS2_PLACEMENT_3D('',#3050,#3051,#3052);
#3054=PLANE('',#3053);
#3055=ORIENTED_EDGE('',*,*,#3042,.T.);
#3056=EDGE_LOOP('',(#3055));
#3057=FACE_BOUND('',#3056,.T.);
#3058=ADVANCED_FACE('F2465',(#3057),#3054,.T.);
#3059=CLOSED_SHELL('',(#46,#162,#225,#288,#351,#414,#477,#540,#603,#666,#729,#792,#855,#918,
#981,#1044,#1064,#1084,#1104,#1124,#1144,#1164,#1184,#1204,#1224,#1252,#1271,#1303,#1369,#1394,
#1460,#1485,#1551,#1576,#1642,#1667,#1733,#1758,#1824,#1849,#1915,#1940,#2006,#2031,#2097,#2122,
#2188,#2213,#2279,#2304,#2370,#2395,#2461,#2486,#2552,#2577,#2643,#2668,#2727,#2744,#2764,#2784,
#2804,#2824,#2842,#2850,#2858,#2866,#2874,#2882,#2890,#2898,#2906,#2914,#2922,#2930,#2938,#2946,
#2954,#2982,#2989,#3009,#3029,#3049,#3058));
#3060=MANIFOLD_SOLID_BREP('B1',#3059);
#3061=ADVANCED_BREP_SHAPE_REPRESENTATION('',(#18,#3060),#14);
#3062=SHAPE_DEFINITION_REPRESENTATION(#9,#3061);
ENDSEC;
END-ISO-10303-21;
